VERSION 5.8 ;
BUSBITCHARS "[]" ;
DIVIDERCHAR "/" ;
UNITS
    DATABASE MICRONS 1000 ;
END UNITS

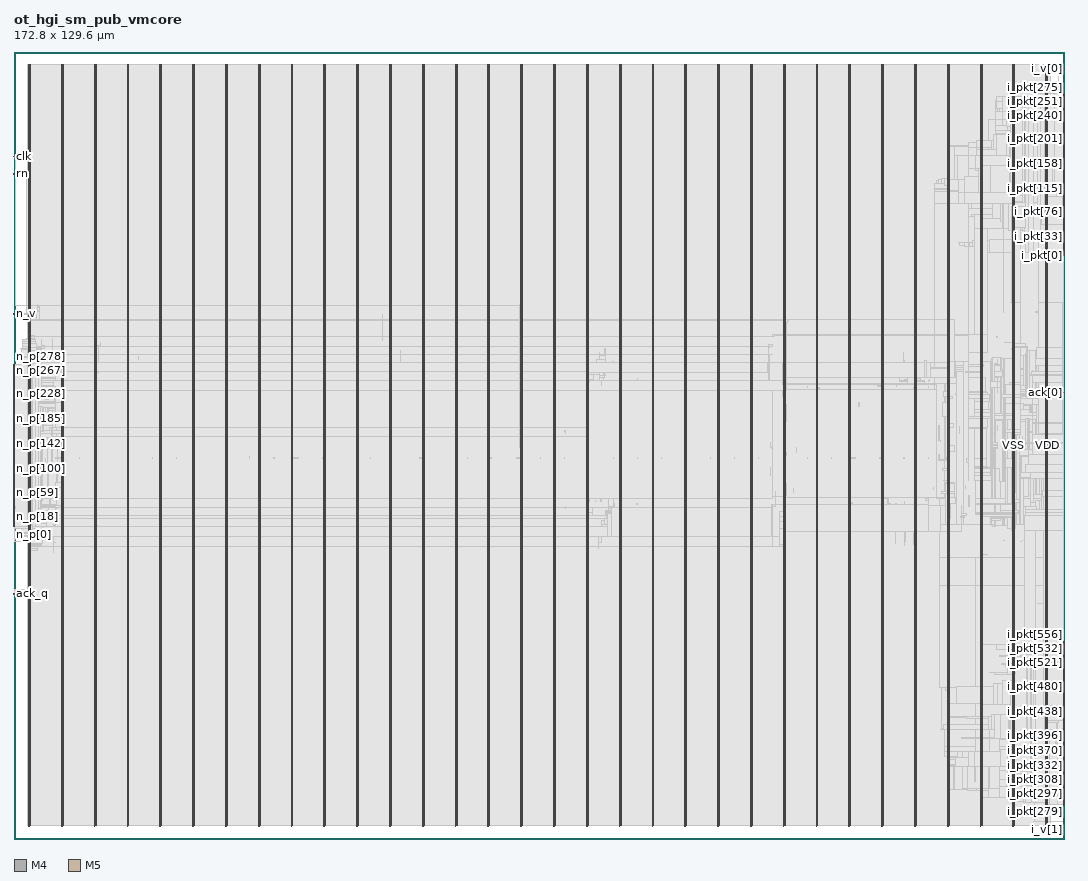
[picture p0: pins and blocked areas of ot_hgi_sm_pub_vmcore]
MACRO ot_hgi_sm_pub_vmcore
  FOREIGN ot_hgi_sm_pub_vmcore 0 0 ;
  CLASS BLOCK ;
  SIZE 172.8 BY 129.6 ;
  PIN ack[0]
    DIRECTION OUTPUT ;
    USE SIGNAL ;
    PORT
      LAYER M4 ;
        RECT  172.758 73.44 172.842 73.464 ;
    END
  END ack[0]
  PIN ack[1]
    DIRECTION OUTPUT ;
    USE SIGNAL ;
    PORT
      LAYER M4 ;
        RECT  172.758 73.536 172.842 73.56 ;
    END
  END ack[1]
  PIN ack_q
    DIRECTION INPUT ;
    USE SIGNAL ;
    PORT
      LAYER M4 ;
        RECT  -0.042 40.32 0.042 40.344 ;
    END
  END ack_q
  PIN clk
    DIRECTION INPUT ;
    USE SIGNAL ;
    PORT
      LAYER M4 ;
        RECT  -0.042 112.32 0.042 112.344 ;
    END
  END clk
  PIN i_pkt[0]
    DIRECTION INPUT ;
    USE SIGNAL ;
    PORT
      LAYER M4 ;
        RECT  172.758 96 172.842 96.024 ;
    END
  END i_pkt[0]
  PIN i_pkt[100]
    DIRECTION INPUT ;
    USE SIGNAL ;
    PORT
      LAYER M4 ;
        RECT  172.758 105.6 172.842 105.624 ;
    END
  END i_pkt[100]
  PIN i_pkt[101]
    DIRECTION INPUT ;
    USE SIGNAL ;
    PORT
      LAYER M4 ;
        RECT  172.758 105.696 172.842 105.72 ;
    END
  END i_pkt[101]
  PIN i_pkt[102]
    DIRECTION INPUT ;
    USE SIGNAL ;
    PORT
      LAYER M4 ;
        RECT  172.758 105.792 172.842 105.816 ;
    END
  END i_pkt[102]
  PIN i_pkt[103]
    DIRECTION INPUT ;
    USE SIGNAL ;
    PORT
      LAYER M4 ;
        RECT  172.758 105.888 172.842 105.912 ;
    END
  END i_pkt[103]
  PIN i_pkt[104]
    DIRECTION INPUT ;
    USE SIGNAL ;
    PORT
      LAYER M4 ;
        RECT  172.758 105.984 172.842 106.008 ;
    END
  END i_pkt[104]
  PIN i_pkt[105]
    DIRECTION INPUT ;
    USE SIGNAL ;
    PORT
      LAYER M4 ;
        RECT  172.758 106.08 172.842 106.104 ;
    END
  END i_pkt[105]
  PIN i_pkt[106]
    DIRECTION INPUT ;
    USE SIGNAL ;
    PORT
      LAYER M4 ;
        RECT  172.758 106.176 172.842 106.2 ;
    END
  END i_pkt[106]
  PIN i_pkt[107]
    DIRECTION INPUT ;
    USE SIGNAL ;
    PORT
      LAYER M4 ;
        RECT  172.758 106.272 172.842 106.296 ;
    END
  END i_pkt[107]
  PIN i_pkt[108]
    DIRECTION INPUT ;
    USE SIGNAL ;
    PORT
      LAYER M4 ;
        RECT  172.758 106.368 172.842 106.392 ;
    END
  END i_pkt[108]
  PIN i_pkt[109]
    DIRECTION INPUT ;
    USE SIGNAL ;
    PORT
      LAYER M4 ;
        RECT  172.758 106.464 172.842 106.488 ;
    END
  END i_pkt[109]
  PIN i_pkt[10]
    DIRECTION INPUT ;
    USE SIGNAL ;
    PORT
      LAYER M4 ;
        RECT  172.758 96.96 172.842 96.984 ;
    END
  END i_pkt[10]
  PIN i_pkt[110]
    DIRECTION INPUT ;
    USE SIGNAL ;
    PORT
      LAYER M4 ;
        RECT  172.758 106.56 172.842 106.584 ;
    END
  END i_pkt[110]
  PIN i_pkt[111]
    DIRECTION INPUT ;
    USE SIGNAL ;
    PORT
      LAYER M4 ;
        RECT  172.758 106.656 172.842 106.68 ;
    END
  END i_pkt[111]
  PIN i_pkt[112]
    DIRECTION INPUT ;
    USE SIGNAL ;
    PORT
      LAYER M4 ;
        RECT  172.758 106.752 172.842 106.776 ;
    END
  END i_pkt[112]
  PIN i_pkt[113]
    DIRECTION INPUT ;
    USE SIGNAL ;
    PORT
      LAYER M4 ;
        RECT  172.758 106.848 172.842 106.872 ;
    END
  END i_pkt[113]
  PIN i_pkt[114]
    DIRECTION INPUT ;
    USE SIGNAL ;
    PORT
      LAYER M4 ;
        RECT  172.758 106.944 172.842 106.968 ;
    END
  END i_pkt[114]
  PIN i_pkt[115]
    DIRECTION INPUT ;
    USE SIGNAL ;
    PORT
      LAYER M4 ;
        RECT  172.758 107.04 172.842 107.064 ;
    END
  END i_pkt[115]
  PIN i_pkt[116]
    DIRECTION INPUT ;
    USE SIGNAL ;
    PORT
      LAYER M4 ;
        RECT  172.758 107.136 172.842 107.16 ;
    END
  END i_pkt[116]
  PIN i_pkt[117]
    DIRECTION INPUT ;
    USE SIGNAL ;
    PORT
      LAYER M4 ;
        RECT  172.758 107.232 172.842 107.256 ;
    END
  END i_pkt[117]
  PIN i_pkt[118]
    DIRECTION INPUT ;
    USE SIGNAL ;
    PORT
      LAYER M4 ;
        RECT  172.758 107.328 172.842 107.352 ;
    END
  END i_pkt[118]
  PIN i_pkt[119]
    DIRECTION INPUT ;
    USE SIGNAL ;
    PORT
      LAYER M4 ;
        RECT  172.758 107.424 172.842 107.448 ;
    END
  END i_pkt[119]
  PIN i_pkt[11]
    DIRECTION INPUT ;
    USE SIGNAL ;
    PORT
      LAYER M4 ;
        RECT  172.758 97.056 172.842 97.08 ;
    END
  END i_pkt[11]
  PIN i_pkt[120]
    DIRECTION INPUT ;
    USE SIGNAL ;
    PORT
      LAYER M4 ;
        RECT  172.758 107.52 172.842 107.544 ;
    END
  END i_pkt[120]
  PIN i_pkt[121]
    DIRECTION INPUT ;
    USE SIGNAL ;
    PORT
      LAYER M4 ;
        RECT  172.758 107.616 172.842 107.64 ;
    END
  END i_pkt[121]
  PIN i_pkt[122]
    DIRECTION INPUT ;
    USE SIGNAL ;
    PORT
      LAYER M4 ;
        RECT  172.758 107.712 172.842 107.736 ;
    END
  END i_pkt[122]
  PIN i_pkt[123]
    DIRECTION INPUT ;
    USE SIGNAL ;
    PORT
      LAYER M4 ;
        RECT  172.758 107.808 172.842 107.832 ;
    END
  END i_pkt[123]
  PIN i_pkt[124]
    DIRECTION INPUT ;
    USE SIGNAL ;
    PORT
      LAYER M4 ;
        RECT  172.758 107.904 172.842 107.928 ;
    END
  END i_pkt[124]
  PIN i_pkt[125]
    DIRECTION INPUT ;
    USE SIGNAL ;
    PORT
      LAYER M4 ;
        RECT  172.758 108 172.842 108.024 ;
    END
  END i_pkt[125]
  PIN i_pkt[126]
    DIRECTION INPUT ;
    USE SIGNAL ;
    PORT
      LAYER M4 ;
        RECT  172.758 108.096 172.842 108.12 ;
    END
  END i_pkt[126]
  PIN i_pkt[127]
    DIRECTION INPUT ;
    USE SIGNAL ;
    PORT
      LAYER M4 ;
        RECT  172.758 108.192 172.842 108.216 ;
    END
  END i_pkt[127]
  PIN i_pkt[128]
    DIRECTION INPUT ;
    USE SIGNAL ;
    PORT
      LAYER M4 ;
        RECT  172.758 108.288 172.842 108.312 ;
    END
  END i_pkt[128]
  PIN i_pkt[129]
    DIRECTION INPUT ;
    USE SIGNAL ;
    PORT
      LAYER M4 ;
        RECT  172.758 108.384 172.842 108.408 ;
    END
  END i_pkt[129]
  PIN i_pkt[12]
    DIRECTION INPUT ;
    USE SIGNAL ;
    PORT
      LAYER M4 ;
        RECT  172.758 97.152 172.842 97.176 ;
    END
  END i_pkt[12]
  PIN i_pkt[130]
    DIRECTION INPUT ;
    USE SIGNAL ;
    PORT
      LAYER M4 ;
        RECT  172.758 108.48 172.842 108.504 ;
    END
  END i_pkt[130]
  PIN i_pkt[131]
    DIRECTION INPUT ;
    USE SIGNAL ;
    PORT
      LAYER M4 ;
        RECT  172.758 108.576 172.842 108.6 ;
    END
  END i_pkt[131]
  PIN i_pkt[132]
    DIRECTION INPUT ;
    USE SIGNAL ;
    PORT
      LAYER M4 ;
        RECT  172.758 108.672 172.842 108.696 ;
    END
  END i_pkt[132]
  PIN i_pkt[133]
    DIRECTION INPUT ;
    USE SIGNAL ;
    PORT
      LAYER M4 ;
        RECT  172.758 108.768 172.842 108.792 ;
    END
  END i_pkt[133]
  PIN i_pkt[134]
    DIRECTION INPUT ;
    USE SIGNAL ;
    PORT
      LAYER M4 ;
        RECT  172.758 108.864 172.842 108.888 ;
    END
  END i_pkt[134]
  PIN i_pkt[135]
    DIRECTION INPUT ;
    USE SIGNAL ;
    PORT
      LAYER M4 ;
        RECT  172.758 108.96 172.842 108.984 ;
    END
  END i_pkt[135]
  PIN i_pkt[136]
    DIRECTION INPUT ;
    USE SIGNAL ;
    PORT
      LAYER M4 ;
        RECT  172.758 109.056 172.842 109.08 ;
    END
  END i_pkt[136]
  PIN i_pkt[137]
    DIRECTION INPUT ;
    USE SIGNAL ;
    PORT
      LAYER M4 ;
        RECT  172.758 109.152 172.842 109.176 ;
    END
  END i_pkt[137]
  PIN i_pkt[138]
    DIRECTION INPUT ;
    USE SIGNAL ;
    PORT
      LAYER M4 ;
        RECT  172.758 109.248 172.842 109.272 ;
    END
  END i_pkt[138]
  PIN i_pkt[139]
    DIRECTION INPUT ;
    USE SIGNAL ;
    PORT
      LAYER M4 ;
        RECT  172.758 109.344 172.842 109.368 ;
    END
  END i_pkt[139]
  PIN i_pkt[13]
    DIRECTION INPUT ;
    USE SIGNAL ;
    PORT
      LAYER M4 ;
        RECT  172.758 97.248 172.842 97.272 ;
    END
  END i_pkt[13]
  PIN i_pkt[140]
    DIRECTION INPUT ;
    USE SIGNAL ;
    PORT
      LAYER M4 ;
        RECT  172.758 109.44 172.842 109.464 ;
    END
  END i_pkt[140]
  PIN i_pkt[141]
    DIRECTION INPUT ;
    USE SIGNAL ;
    PORT
      LAYER M4 ;
        RECT  172.758 109.536 172.842 109.56 ;
    END
  END i_pkt[141]
  PIN i_pkt[142]
    DIRECTION INPUT ;
    USE SIGNAL ;
    PORT
      LAYER M4 ;
        RECT  172.758 109.632 172.842 109.656 ;
    END
  END i_pkt[142]
  PIN i_pkt[143]
    DIRECTION INPUT ;
    USE SIGNAL ;
    PORT
      LAYER M4 ;
        RECT  172.758 109.728 172.842 109.752 ;
    END
  END i_pkt[143]
  PIN i_pkt[144]
    DIRECTION INPUT ;
    USE SIGNAL ;
    PORT
      LAYER M4 ;
        RECT  172.758 109.824 172.842 109.848 ;
    END
  END i_pkt[144]
  PIN i_pkt[145]
    DIRECTION INPUT ;
    USE SIGNAL ;
    PORT
      LAYER M4 ;
        RECT  172.758 109.92 172.842 109.944 ;
    END
  END i_pkt[145]
  PIN i_pkt[146]
    DIRECTION INPUT ;
    USE SIGNAL ;
    PORT
      LAYER M4 ;
        RECT  172.758 110.016 172.842 110.04 ;
    END
  END i_pkt[146]
  PIN i_pkt[147]
    DIRECTION INPUT ;
    USE SIGNAL ;
    PORT
      LAYER M4 ;
        RECT  172.758 110.112 172.842 110.136 ;
    END
  END i_pkt[147]
  PIN i_pkt[148]
    DIRECTION INPUT ;
    USE SIGNAL ;
    PORT
      LAYER M4 ;
        RECT  172.758 110.208 172.842 110.232 ;
    END
  END i_pkt[148]
  PIN i_pkt[149]
    DIRECTION INPUT ;
    USE SIGNAL ;
    PORT
      LAYER M4 ;
        RECT  172.758 110.304 172.842 110.328 ;
    END
  END i_pkt[149]
  PIN i_pkt[14]
    DIRECTION INPUT ;
    USE SIGNAL ;
    PORT
      LAYER M4 ;
        RECT  172.758 97.344 172.842 97.368 ;
    END
  END i_pkt[14]
  PIN i_pkt[150]
    DIRECTION INPUT ;
    USE SIGNAL ;
    PORT
      LAYER M4 ;
        RECT  172.758 110.4 172.842 110.424 ;
    END
  END i_pkt[150]
  PIN i_pkt[151]
    DIRECTION INPUT ;
    USE SIGNAL ;
    PORT
      LAYER M4 ;
        RECT  172.758 110.496 172.842 110.52 ;
    END
  END i_pkt[151]
  PIN i_pkt[152]
    DIRECTION INPUT ;
    USE SIGNAL ;
    PORT
      LAYER M4 ;
        RECT  172.758 110.592 172.842 110.616 ;
    END
  END i_pkt[152]
  PIN i_pkt[153]
    DIRECTION INPUT ;
    USE SIGNAL ;
    PORT
      LAYER M4 ;
        RECT  172.758 110.688 172.842 110.712 ;
    END
  END i_pkt[153]
  PIN i_pkt[154]
    DIRECTION INPUT ;
    USE SIGNAL ;
    PORT
      LAYER M4 ;
        RECT  172.758 110.784 172.842 110.808 ;
    END
  END i_pkt[154]
  PIN i_pkt[155]
    DIRECTION INPUT ;
    USE SIGNAL ;
    PORT
      LAYER M4 ;
        RECT  172.758 110.88 172.842 110.904 ;
    END
  END i_pkt[155]
  PIN i_pkt[156]
    DIRECTION INPUT ;
    USE SIGNAL ;
    PORT
      LAYER M4 ;
        RECT  172.758 110.976 172.842 111 ;
    END
  END i_pkt[156]
  PIN i_pkt[157]
    DIRECTION INPUT ;
    USE SIGNAL ;
    PORT
      LAYER M4 ;
        RECT  172.758 111.072 172.842 111.096 ;
    END
  END i_pkt[157]
  PIN i_pkt[158]
    DIRECTION INPUT ;
    USE SIGNAL ;
    PORT
      LAYER M4 ;
        RECT  172.758 111.168 172.842 111.192 ;
    END
  END i_pkt[158]
  PIN i_pkt[159]
    DIRECTION INPUT ;
    USE SIGNAL ;
    PORT
      LAYER M4 ;
        RECT  172.758 111.264 172.842 111.288 ;
    END
  END i_pkt[159]
  PIN i_pkt[15]
    DIRECTION INPUT ;
    USE SIGNAL ;
    PORT
      LAYER M4 ;
        RECT  172.758 97.44 172.842 97.464 ;
    END
  END i_pkt[15]
  PIN i_pkt[160]
    DIRECTION INPUT ;
    USE SIGNAL ;
    PORT
      LAYER M4 ;
        RECT  172.758 111.36 172.842 111.384 ;
    END
  END i_pkt[160]
  PIN i_pkt[161]
    DIRECTION INPUT ;
    USE SIGNAL ;
    PORT
      LAYER M4 ;
        RECT  172.758 111.456 172.842 111.48 ;
    END
  END i_pkt[161]
  PIN i_pkt[162]
    DIRECTION INPUT ;
    USE SIGNAL ;
    PORT
      LAYER M4 ;
        RECT  172.758 111.552 172.842 111.576 ;
    END
  END i_pkt[162]
  PIN i_pkt[163]
    DIRECTION INPUT ;
    USE SIGNAL ;
    PORT
      LAYER M4 ;
        RECT  172.758 111.648 172.842 111.672 ;
    END
  END i_pkt[163]
  PIN i_pkt[164]
    DIRECTION INPUT ;
    USE SIGNAL ;
    PORT
      LAYER M4 ;
        RECT  172.758 111.744 172.842 111.768 ;
    END
  END i_pkt[164]
  PIN i_pkt[165]
    DIRECTION INPUT ;
    USE SIGNAL ;
    PORT
      LAYER M4 ;
        RECT  172.758 111.84 172.842 111.864 ;
    END
  END i_pkt[165]
  PIN i_pkt[166]
    DIRECTION INPUT ;
    USE SIGNAL ;
    PORT
      LAYER M4 ;
        RECT  172.758 111.936 172.842 111.96 ;
    END
  END i_pkt[166]
  PIN i_pkt[167]
    DIRECTION INPUT ;
    USE SIGNAL ;
    PORT
      LAYER M4 ;
        RECT  172.758 112.032 172.842 112.056 ;
    END
  END i_pkt[167]
  PIN i_pkt[168]
    DIRECTION INPUT ;
    USE SIGNAL ;
    PORT
      LAYER M4 ;
        RECT  172.758 112.128 172.842 112.152 ;
    END
  END i_pkt[168]
  PIN i_pkt[169]
    DIRECTION INPUT ;
    USE SIGNAL ;
    PORT
      LAYER M4 ;
        RECT  172.758 112.224 172.842 112.248 ;
    END
  END i_pkt[169]
  PIN i_pkt[16]
    DIRECTION INPUT ;
    USE SIGNAL ;
    PORT
      LAYER M4 ;
        RECT  172.758 97.536 172.842 97.56 ;
    END
  END i_pkt[16]
  PIN i_pkt[170]
    DIRECTION INPUT ;
    USE SIGNAL ;
    PORT
      LAYER M4 ;
        RECT  172.758 112.32 172.842 112.344 ;
    END
  END i_pkt[170]
  PIN i_pkt[171]
    DIRECTION INPUT ;
    USE SIGNAL ;
    PORT
      LAYER M4 ;
        RECT  172.758 112.416 172.842 112.44 ;
    END
  END i_pkt[171]
  PIN i_pkt[172]
    DIRECTION INPUT ;
    USE SIGNAL ;
    PORT
      LAYER M4 ;
        RECT  172.758 112.512 172.842 112.536 ;
    END
  END i_pkt[172]
  PIN i_pkt[173]
    DIRECTION INPUT ;
    USE SIGNAL ;
    PORT
      LAYER M4 ;
        RECT  172.758 112.608 172.842 112.632 ;
    END
  END i_pkt[173]
  PIN i_pkt[174]
    DIRECTION INPUT ;
    USE SIGNAL ;
    PORT
      LAYER M4 ;
        RECT  172.758 112.704 172.842 112.728 ;
    END
  END i_pkt[174]
  PIN i_pkt[175]
    DIRECTION INPUT ;
    USE SIGNAL ;
    PORT
      LAYER M4 ;
        RECT  172.758 112.8 172.842 112.824 ;
    END
  END i_pkt[175]
  PIN i_pkt[176]
    DIRECTION INPUT ;
    USE SIGNAL ;
    PORT
      LAYER M4 ;
        RECT  172.758 112.896 172.842 112.92 ;
    END
  END i_pkt[176]
  PIN i_pkt[177]
    DIRECTION INPUT ;
    USE SIGNAL ;
    PORT
      LAYER M4 ;
        RECT  172.758 112.992 172.842 113.016 ;
    END
  END i_pkt[177]
  PIN i_pkt[178]
    DIRECTION INPUT ;
    USE SIGNAL ;
    PORT
      LAYER M4 ;
        RECT  172.758 113.088 172.842 113.112 ;
    END
  END i_pkt[178]
  PIN i_pkt[179]
    DIRECTION INPUT ;
    USE SIGNAL ;
    PORT
      LAYER M4 ;
        RECT  172.758 113.184 172.842 113.208 ;
    END
  END i_pkt[179]
  PIN i_pkt[17]
    DIRECTION INPUT ;
    USE SIGNAL ;
    PORT
      LAYER M4 ;
        RECT  172.758 97.632 172.842 97.656 ;
    END
  END i_pkt[17]
  PIN i_pkt[180]
    DIRECTION INPUT ;
    USE SIGNAL ;
    PORT
      LAYER M4 ;
        RECT  172.758 113.28 172.842 113.304 ;
    END
  END i_pkt[180]
  PIN i_pkt[181]
    DIRECTION INPUT ;
    USE SIGNAL ;
    PORT
      LAYER M4 ;
        RECT  172.758 113.376 172.842 113.4 ;
    END
  END i_pkt[181]
  PIN i_pkt[182]
    DIRECTION INPUT ;
    USE SIGNAL ;
    PORT
      LAYER M4 ;
        RECT  172.758 113.472 172.842 113.496 ;
    END
  END i_pkt[182]
  PIN i_pkt[183]
    DIRECTION INPUT ;
    USE SIGNAL ;
    PORT
      LAYER M4 ;
        RECT  172.758 113.568 172.842 113.592 ;
    END
  END i_pkt[183]
  PIN i_pkt[184]
    DIRECTION INPUT ;
    USE SIGNAL ;
    PORT
      LAYER M4 ;
        RECT  172.758 113.664 172.842 113.688 ;
    END
  END i_pkt[184]
  PIN i_pkt[185]
    DIRECTION INPUT ;
    USE SIGNAL ;
    PORT
      LAYER M4 ;
        RECT  172.758 113.76 172.842 113.784 ;
    END
  END i_pkt[185]
  PIN i_pkt[186]
    DIRECTION INPUT ;
    USE SIGNAL ;
    PORT
      LAYER M4 ;
        RECT  172.758 113.856 172.842 113.88 ;
    END
  END i_pkt[186]
  PIN i_pkt[187]
    DIRECTION INPUT ;
    USE SIGNAL ;
    PORT
      LAYER M4 ;
        RECT  172.758 113.952 172.842 113.976 ;
    END
  END i_pkt[187]
  PIN i_pkt[188]
    DIRECTION INPUT ;
    USE SIGNAL ;
    PORT
      LAYER M4 ;
        RECT  172.758 114.048 172.842 114.072 ;
    END
  END i_pkt[188]
  PIN i_pkt[189]
    DIRECTION INPUT ;
    USE SIGNAL ;
    PORT
      LAYER M4 ;
        RECT  172.758 114.144 172.842 114.168 ;
    END
  END i_pkt[189]
  PIN i_pkt[18]
    DIRECTION INPUT ;
    USE SIGNAL ;
    PORT
      LAYER M4 ;
        RECT  172.758 97.728 172.842 97.752 ;
    END
  END i_pkt[18]
  PIN i_pkt[190]
    DIRECTION INPUT ;
    USE SIGNAL ;
    PORT
      LAYER M4 ;
        RECT  172.758 114.24 172.842 114.264 ;
    END
  END i_pkt[190]
  PIN i_pkt[191]
    DIRECTION INPUT ;
    USE SIGNAL ;
    PORT
      LAYER M4 ;
        RECT  172.758 114.336 172.842 114.36 ;
    END
  END i_pkt[191]
  PIN i_pkt[192]
    DIRECTION INPUT ;
    USE SIGNAL ;
    PORT
      LAYER M4 ;
        RECT  172.758 114.432 172.842 114.456 ;
    END
  END i_pkt[192]
  PIN i_pkt[193]
    DIRECTION INPUT ;
    USE SIGNAL ;
    PORT
      LAYER M4 ;
        RECT  172.758 114.528 172.842 114.552 ;
    END
  END i_pkt[193]
  PIN i_pkt[194]
    DIRECTION INPUT ;
    USE SIGNAL ;
    PORT
      LAYER M4 ;
        RECT  172.758 114.624 172.842 114.648 ;
    END
  END i_pkt[194]
  PIN i_pkt[195]
    DIRECTION INPUT ;
    USE SIGNAL ;
    PORT
      LAYER M4 ;
        RECT  172.758 114.72 172.842 114.744 ;
    END
  END i_pkt[195]
  PIN i_pkt[196]
    DIRECTION INPUT ;
    USE SIGNAL ;
    PORT
      LAYER M4 ;
        RECT  172.758 114.816 172.842 114.84 ;
    END
  END i_pkt[196]
  PIN i_pkt[197]
    DIRECTION INPUT ;
    USE SIGNAL ;
    PORT
      LAYER M4 ;
        RECT  172.758 114.912 172.842 114.936 ;
    END
  END i_pkt[197]
  PIN i_pkt[198]
    DIRECTION INPUT ;
    USE SIGNAL ;
    PORT
      LAYER M4 ;
        RECT  172.758 115.008 172.842 115.032 ;
    END
  END i_pkt[198]
  PIN i_pkt[199]
    DIRECTION INPUT ;
    USE SIGNAL ;
    PORT
      LAYER M4 ;
        RECT  172.758 115.104 172.842 115.128 ;
    END
  END i_pkt[199]
  PIN i_pkt[19]
    DIRECTION INPUT ;
    USE SIGNAL ;
    PORT
      LAYER M4 ;
        RECT  172.758 97.824 172.842 97.848 ;
    END
  END i_pkt[19]
  PIN i_pkt[1]
    DIRECTION INPUT ;
    USE SIGNAL ;
    PORT
      LAYER M4 ;
        RECT  172.758 96.096 172.842 96.12 ;
    END
  END i_pkt[1]
  PIN i_pkt[200]
    DIRECTION INPUT ;
    USE SIGNAL ;
    PORT
      LAYER M4 ;
        RECT  172.758 115.2 172.842 115.224 ;
    END
  END i_pkt[200]
  PIN i_pkt[201]
    DIRECTION INPUT ;
    USE SIGNAL ;
    PORT
      LAYER M4 ;
        RECT  172.758 115.296 172.842 115.32 ;
    END
  END i_pkt[201]
  PIN i_pkt[202]
    DIRECTION INPUT ;
    USE SIGNAL ;
    PORT
      LAYER M4 ;
        RECT  172.758 115.392 172.842 115.416 ;
    END
  END i_pkt[202]
  PIN i_pkt[203]
    DIRECTION INPUT ;
    USE SIGNAL ;
    PORT
      LAYER M4 ;
        RECT  172.758 115.488 172.842 115.512 ;
    END
  END i_pkt[203]
  PIN i_pkt[204]
    DIRECTION INPUT ;
    USE SIGNAL ;
    PORT
      LAYER M4 ;
        RECT  172.758 115.584 172.842 115.608 ;
    END
  END i_pkt[204]
  PIN i_pkt[205]
    DIRECTION INPUT ;
    USE SIGNAL ;
    PORT
      LAYER M4 ;
        RECT  172.758 115.68 172.842 115.704 ;
    END
  END i_pkt[205]
  PIN i_pkt[206]
    DIRECTION INPUT ;
    USE SIGNAL ;
    PORT
      LAYER M4 ;
        RECT  172.758 115.776 172.842 115.8 ;
    END
  END i_pkt[206]
  PIN i_pkt[207]
    DIRECTION INPUT ;
    USE SIGNAL ;
    PORT
      LAYER M4 ;
        RECT  172.758 115.872 172.842 115.896 ;
    END
  END i_pkt[207]
  PIN i_pkt[208]
    DIRECTION INPUT ;
    USE SIGNAL ;
    PORT
      LAYER M4 ;
        RECT  172.758 115.968 172.842 115.992 ;
    END
  END i_pkt[208]
  PIN i_pkt[209]
    DIRECTION INPUT ;
    USE SIGNAL ;
    PORT
      LAYER M4 ;
        RECT  172.758 116.064 172.842 116.088 ;
    END
  END i_pkt[209]
  PIN i_pkt[20]
    DIRECTION INPUT ;
    USE SIGNAL ;
    PORT
      LAYER M4 ;
        RECT  172.758 97.92 172.842 97.944 ;
    END
  END i_pkt[20]
  PIN i_pkt[210]
    DIRECTION INPUT ;
    USE SIGNAL ;
    PORT
      LAYER M4 ;
        RECT  172.758 116.16 172.842 116.184 ;
    END
  END i_pkt[210]
  PIN i_pkt[211]
    DIRECTION INPUT ;
    USE SIGNAL ;
    PORT
      LAYER M4 ;
        RECT  172.758 116.256 172.842 116.28 ;
    END
  END i_pkt[211]
  PIN i_pkt[212]
    DIRECTION INPUT ;
    USE SIGNAL ;
    PORT
      LAYER M4 ;
        RECT  172.758 116.352 172.842 116.376 ;
    END
  END i_pkt[212]
  PIN i_pkt[213]
    DIRECTION INPUT ;
    USE SIGNAL ;
    PORT
      LAYER M4 ;
        RECT  172.758 116.448 172.842 116.472 ;
    END
  END i_pkt[213]
  PIN i_pkt[214]
    DIRECTION INPUT ;
    USE SIGNAL ;
    PORT
      LAYER M4 ;
        RECT  172.758 116.544 172.842 116.568 ;
    END
  END i_pkt[214]
  PIN i_pkt[215]
    DIRECTION INPUT ;
    USE SIGNAL ;
    PORT
      LAYER M4 ;
        RECT  172.758 116.64 172.842 116.664 ;
    END
  END i_pkt[215]
  PIN i_pkt[216]
    DIRECTION INPUT ;
    USE SIGNAL ;
    PORT
      LAYER M4 ;
        RECT  172.758 116.736 172.842 116.76 ;
    END
  END i_pkt[216]
  PIN i_pkt[217]
    DIRECTION INPUT ;
    USE SIGNAL ;
    PORT
      LAYER M4 ;
        RECT  172.758 116.832 172.842 116.856 ;
    END
  END i_pkt[217]
  PIN i_pkt[218]
    DIRECTION INPUT ;
    USE SIGNAL ;
    PORT
      LAYER M4 ;
        RECT  172.758 116.928 172.842 116.952 ;
    END
  END i_pkt[218]
  PIN i_pkt[219]
    DIRECTION INPUT ;
    USE SIGNAL ;
    PORT
      LAYER M4 ;
        RECT  172.758 117.024 172.842 117.048 ;
    END
  END i_pkt[219]
  PIN i_pkt[21]
    DIRECTION INPUT ;
    USE SIGNAL ;
    PORT
      LAYER M4 ;
        RECT  172.758 98.016 172.842 98.04 ;
    END
  END i_pkt[21]
  PIN i_pkt[220]
    DIRECTION INPUT ;
    USE SIGNAL ;
    PORT
      LAYER M4 ;
        RECT  172.758 117.12 172.842 117.144 ;
    END
  END i_pkt[220]
  PIN i_pkt[221]
    DIRECTION INPUT ;
    USE SIGNAL ;
    PORT
      LAYER M4 ;
        RECT  172.758 117.216 172.842 117.24 ;
    END
  END i_pkt[221]
  PIN i_pkt[222]
    DIRECTION INPUT ;
    USE SIGNAL ;
    PORT
      LAYER M4 ;
        RECT  172.758 117.312 172.842 117.336 ;
    END
  END i_pkt[222]
  PIN i_pkt[223]
    DIRECTION INPUT ;
    USE SIGNAL ;
    PORT
      LAYER M4 ;
        RECT  172.758 117.408 172.842 117.432 ;
    END
  END i_pkt[223]
  PIN i_pkt[224]
    DIRECTION INPUT ;
    USE SIGNAL ;
    PORT
      LAYER M4 ;
        RECT  172.758 117.504 172.842 117.528 ;
    END
  END i_pkt[224]
  PIN i_pkt[225]
    DIRECTION INPUT ;
    USE SIGNAL ;
    PORT
      LAYER M4 ;
        RECT  172.758 117.6 172.842 117.624 ;
    END
  END i_pkt[225]
  PIN i_pkt[226]
    DIRECTION INPUT ;
    USE SIGNAL ;
    PORT
      LAYER M4 ;
        RECT  172.758 117.696 172.842 117.72 ;
    END
  END i_pkt[226]
  PIN i_pkt[227]
    DIRECTION INPUT ;
    USE SIGNAL ;
    PORT
      LAYER M4 ;
        RECT  172.758 117.792 172.842 117.816 ;
    END
  END i_pkt[227]
  PIN i_pkt[228]
    DIRECTION INPUT ;
    USE SIGNAL ;
    PORT
      LAYER M4 ;
        RECT  172.758 117.888 172.842 117.912 ;
    END
  END i_pkt[228]
  PIN i_pkt[229]
    DIRECTION INPUT ;
    USE SIGNAL ;
    PORT
      LAYER M4 ;
        RECT  172.758 117.984 172.842 118.008 ;
    END
  END i_pkt[229]
  PIN i_pkt[22]
    DIRECTION INPUT ;
    USE SIGNAL ;
    PORT
      LAYER M4 ;
        RECT  172.758 98.112 172.842 98.136 ;
    END
  END i_pkt[22]
  PIN i_pkt[230]
    DIRECTION INPUT ;
    USE SIGNAL ;
    PORT
      LAYER M4 ;
        RECT  172.758 118.08 172.842 118.104 ;
    END
  END i_pkt[230]
  PIN i_pkt[231]
    DIRECTION INPUT ;
    USE SIGNAL ;
    PORT
      LAYER M4 ;
        RECT  172.758 118.176 172.842 118.2 ;
    END
  END i_pkt[231]
  PIN i_pkt[232]
    DIRECTION INPUT ;
    USE SIGNAL ;
    PORT
      LAYER M4 ;
        RECT  172.758 118.272 172.842 118.296 ;
    END
  END i_pkt[232]
  PIN i_pkt[233]
    DIRECTION INPUT ;
    USE SIGNAL ;
    PORT
      LAYER M4 ;
        RECT  172.758 118.368 172.842 118.392 ;
    END
  END i_pkt[233]
  PIN i_pkt[234]
    DIRECTION INPUT ;
    USE SIGNAL ;
    PORT
      LAYER M4 ;
        RECT  172.758 118.464 172.842 118.488 ;
    END
  END i_pkt[234]
  PIN i_pkt[235]
    DIRECTION INPUT ;
    USE SIGNAL ;
    PORT
      LAYER M4 ;
        RECT  172.758 118.56 172.842 118.584 ;
    END
  END i_pkt[235]
  PIN i_pkt[236]
    DIRECTION INPUT ;
    USE SIGNAL ;
    PORT
      LAYER M4 ;
        RECT  172.758 118.656 172.842 118.68 ;
    END
  END i_pkt[236]
  PIN i_pkt[237]
    DIRECTION INPUT ;
    USE SIGNAL ;
    PORT
      LAYER M4 ;
        RECT  172.758 118.752 172.842 118.776 ;
    END
  END i_pkt[237]
  PIN i_pkt[238]
    DIRECTION INPUT ;
    USE SIGNAL ;
    PORT
      LAYER M4 ;
        RECT  172.758 118.848 172.842 118.872 ;
    END
  END i_pkt[238]
  PIN i_pkt[239]
    DIRECTION INPUT ;
    USE SIGNAL ;
    PORT
      LAYER M4 ;
        RECT  172.758 118.944 172.842 118.968 ;
    END
  END i_pkt[239]
  PIN i_pkt[23]
    DIRECTION INPUT ;
    USE SIGNAL ;
    PORT
      LAYER M4 ;
        RECT  172.758 98.208 172.842 98.232 ;
    END
  END i_pkt[23]
  PIN i_pkt[240]
    DIRECTION INPUT ;
    USE SIGNAL ;
    PORT
      LAYER M4 ;
        RECT  172.758 119.04 172.842 119.064 ;
    END
  END i_pkt[240]
  PIN i_pkt[241]
    DIRECTION INPUT ;
    USE SIGNAL ;
    PORT
      LAYER M4 ;
        RECT  172.758 119.136 172.842 119.16 ;
    END
  END i_pkt[241]
  PIN i_pkt[242]
    DIRECTION INPUT ;
    USE SIGNAL ;
    PORT
      LAYER M4 ;
        RECT  172.758 119.232 172.842 119.256 ;
    END
  END i_pkt[242]
  PIN i_pkt[243]
    DIRECTION INPUT ;
    USE SIGNAL ;
    PORT
      LAYER M4 ;
        RECT  172.758 119.328 172.842 119.352 ;
    END
  END i_pkt[243]
  PIN i_pkt[244]
    DIRECTION INPUT ;
    USE SIGNAL ;
    PORT
      LAYER M4 ;
        RECT  172.758 119.424 172.842 119.448 ;
    END
  END i_pkt[244]
  PIN i_pkt[245]
    DIRECTION INPUT ;
    USE SIGNAL ;
    PORT
      LAYER M4 ;
        RECT  172.758 119.52 172.842 119.544 ;
    END
  END i_pkt[245]
  PIN i_pkt[246]
    DIRECTION INPUT ;
    USE SIGNAL ;
    PORT
      LAYER M4 ;
        RECT  172.758 119.616 172.842 119.64 ;
    END
  END i_pkt[246]
  PIN i_pkt[247]
    DIRECTION INPUT ;
    USE SIGNAL ;
    PORT
      LAYER M4 ;
        RECT  172.758 119.712 172.842 119.736 ;
    END
  END i_pkt[247]
  PIN i_pkt[248]
    DIRECTION INPUT ;
    USE SIGNAL ;
    PORT
      LAYER M4 ;
        RECT  172.758 119.808 172.842 119.832 ;
    END
  END i_pkt[248]
  PIN i_pkt[249]
    DIRECTION INPUT ;
    USE SIGNAL ;
    PORT
      LAYER M4 ;
        RECT  172.758 119.904 172.842 119.928 ;
    END
  END i_pkt[249]
  PIN i_pkt[24]
    DIRECTION INPUT ;
    USE SIGNAL ;
    PORT
      LAYER M4 ;
        RECT  172.758 98.304 172.842 98.328 ;
    END
  END i_pkt[24]
  PIN i_pkt[250]
    DIRECTION INPUT ;
    USE SIGNAL ;
    PORT
      LAYER M4 ;
        RECT  172.758 120 172.842 120.024 ;
    END
  END i_pkt[250]
  PIN i_pkt[251]
    DIRECTION INPUT ;
    USE SIGNAL ;
    PORT
      LAYER M4 ;
        RECT  172.758 120.096 172.842 120.12 ;
    END
  END i_pkt[251]
  PIN i_pkt[252]
    DIRECTION INPUT ;
    USE SIGNAL ;
    PORT
      LAYER M4 ;
        RECT  172.758 120.192 172.842 120.216 ;
    END
  END i_pkt[252]
  PIN i_pkt[253]
    DIRECTION INPUT ;
    USE SIGNAL ;
    PORT
      LAYER M4 ;
        RECT  172.758 120.288 172.842 120.312 ;
    END
  END i_pkt[253]
  PIN i_pkt[254]
    DIRECTION INPUT ;
    USE SIGNAL ;
    PORT
      LAYER M4 ;
        RECT  172.758 120.384 172.842 120.408 ;
    END
  END i_pkt[254]
  PIN i_pkt[255]
    DIRECTION INPUT ;
    USE SIGNAL ;
    PORT
      LAYER M4 ;
        RECT  172.758 120.48 172.842 120.504 ;
    END
  END i_pkt[255]
  PIN i_pkt[256]
    DIRECTION INPUT ;
    USE SIGNAL ;
    PORT
      LAYER M4 ;
        RECT  172.758 120.576 172.842 120.6 ;
    END
  END i_pkt[256]
  PIN i_pkt[257]
    DIRECTION INPUT ;
    USE SIGNAL ;
    PORT
      LAYER M4 ;
        RECT  172.758 120.672 172.842 120.696 ;
    END
  END i_pkt[257]
  PIN i_pkt[258]
    DIRECTION INPUT ;
    USE SIGNAL ;
    PORT
      LAYER M4 ;
        RECT  172.758 120.768 172.842 120.792 ;
    END
  END i_pkt[258]
  PIN i_pkt[259]
    DIRECTION INPUT ;
    USE SIGNAL ;
    PORT
      LAYER M4 ;
        RECT  172.758 120.864 172.842 120.888 ;
    END
  END i_pkt[259]
  PIN i_pkt[25]
    DIRECTION INPUT ;
    USE SIGNAL ;
    PORT
      LAYER M4 ;
        RECT  172.758 98.4 172.842 98.424 ;
    END
  END i_pkt[25]
  PIN i_pkt[260]
    DIRECTION INPUT ;
    USE SIGNAL ;
    PORT
      LAYER M4 ;
        RECT  172.758 120.96 172.842 120.984 ;
    END
  END i_pkt[260]
  PIN i_pkt[261]
    DIRECTION INPUT ;
    USE SIGNAL ;
    PORT
      LAYER M4 ;
        RECT  172.758 121.056 172.842 121.08 ;
    END
  END i_pkt[261]
  PIN i_pkt[262]
    DIRECTION INPUT ;
    USE SIGNAL ;
    PORT
      LAYER M4 ;
        RECT  172.758 121.152 172.842 121.176 ;
    END
  END i_pkt[262]
  PIN i_pkt[263]
    DIRECTION INPUT ;
    USE SIGNAL ;
    PORT
      LAYER M4 ;
        RECT  172.758 121.248 172.842 121.272 ;
    END
  END i_pkt[263]
  PIN i_pkt[264]
    DIRECTION INPUT ;
    USE SIGNAL ;
    PORT
      LAYER M4 ;
        RECT  172.758 121.344 172.842 121.368 ;
    END
  END i_pkt[264]
  PIN i_pkt[265]
    DIRECTION INPUT ;
    USE SIGNAL ;
    PORT
      LAYER M4 ;
        RECT  172.758 121.44 172.842 121.464 ;
    END
  END i_pkt[265]
  PIN i_pkt[266]
    DIRECTION INPUT ;
    USE SIGNAL ;
    PORT
      LAYER M4 ;
        RECT  172.758 121.536 172.842 121.56 ;
    END
  END i_pkt[266]
  PIN i_pkt[267]
    DIRECTION INPUT ;
    USE SIGNAL ;
    PORT
      LAYER M4 ;
        RECT  172.758 121.632 172.842 121.656 ;
    END
  END i_pkt[267]
  PIN i_pkt[268]
    DIRECTION INPUT ;
    USE SIGNAL ;
    PORT
      LAYER M4 ;
        RECT  172.758 121.728 172.842 121.752 ;
    END
  END i_pkt[268]
  PIN i_pkt[269]
    DIRECTION INPUT ;
    USE SIGNAL ;
    PORT
      LAYER M4 ;
        RECT  172.758 121.824 172.842 121.848 ;
    END
  END i_pkt[269]
  PIN i_pkt[26]
    DIRECTION INPUT ;
    USE SIGNAL ;
    PORT
      LAYER M4 ;
        RECT  172.758 98.496 172.842 98.52 ;
    END
  END i_pkt[26]
  PIN i_pkt[270]
    DIRECTION INPUT ;
    USE SIGNAL ;
    PORT
      LAYER M4 ;
        RECT  172.758 121.92 172.842 121.944 ;
    END
  END i_pkt[270]
  PIN i_pkt[271]
    DIRECTION INPUT ;
    USE SIGNAL ;
    PORT
      LAYER M4 ;
        RECT  172.758 122.016 172.842 122.04 ;
    END
  END i_pkt[271]
  PIN i_pkt[272]
    DIRECTION INPUT ;
    USE SIGNAL ;
    PORT
      LAYER M4 ;
        RECT  172.758 122.112 172.842 122.136 ;
    END
  END i_pkt[272]
  PIN i_pkt[273]
    DIRECTION INPUT ;
    USE SIGNAL ;
    PORT
      LAYER M4 ;
        RECT  172.758 122.208 172.842 122.232 ;
    END
  END i_pkt[273]
  PIN i_pkt[274]
    DIRECTION INPUT ;
    USE SIGNAL ;
    PORT
      LAYER M4 ;
        RECT  172.758 122.304 172.842 122.328 ;
    END
  END i_pkt[274]
  PIN i_pkt[275]
    DIRECTION INPUT ;
    USE SIGNAL ;
    PORT
      LAYER M4 ;
        RECT  172.758 122.4 172.842 122.424 ;
    END
  END i_pkt[275]
  PIN i_pkt[276]
    DIRECTION INPUT ;
    USE SIGNAL ;
    PORT
      LAYER M4 ;
        RECT  172.758 122.496 172.842 122.52 ;
    END
  END i_pkt[276]
  PIN i_pkt[277]
    DIRECTION INPUT ;
    USE SIGNAL ;
    PORT
      LAYER M4 ;
        RECT  172.758 122.592 172.842 122.616 ;
    END
  END i_pkt[277]
  PIN i_pkt[278]
    DIRECTION INPUT ;
    USE SIGNAL ;
    PORT
      LAYER M4 ;
        RECT  172.758 122.688 172.842 122.712 ;
    END
  END i_pkt[278]
  PIN i_pkt[279]
    DIRECTION INPUT ;
    USE SIGNAL ;
    PORT
      LAYER M4 ;
        RECT  172.758 5.76 172.842 5.784 ;
    END
  END i_pkt[279]
  PIN i_pkt[27]
    DIRECTION INPUT ;
    USE SIGNAL ;
    PORT
      LAYER M4 ;
        RECT  172.758 98.592 172.842 98.616 ;
    END
  END i_pkt[27]
  PIN i_pkt[280]
    DIRECTION INPUT ;
    USE SIGNAL ;
    PORT
      LAYER M4 ;
        RECT  172.758 5.856 172.842 5.88 ;
    END
  END i_pkt[280]
  PIN i_pkt[281]
    DIRECTION INPUT ;
    USE SIGNAL ;
    PORT
      LAYER M4 ;
        RECT  172.758 5.952 172.842 5.976 ;
    END
  END i_pkt[281]
  PIN i_pkt[282]
    DIRECTION INPUT ;
    USE SIGNAL ;
    PORT
      LAYER M4 ;
        RECT  172.758 6.048 172.842 6.072 ;
    END
  END i_pkt[282]
  PIN i_pkt[283]
    DIRECTION INPUT ;
    USE SIGNAL ;
    PORT
      LAYER M4 ;
        RECT  172.758 6.144 172.842 6.168 ;
    END
  END i_pkt[283]
  PIN i_pkt[284]
    DIRECTION INPUT ;
    USE SIGNAL ;
    PORT
      LAYER M4 ;
        RECT  172.758 6.24 172.842 6.264 ;
    END
  END i_pkt[284]
  PIN i_pkt[285]
    DIRECTION INPUT ;
    USE SIGNAL ;
    PORT
      LAYER M4 ;
        RECT  172.758 6.336 172.842 6.36 ;
    END
  END i_pkt[285]
  PIN i_pkt[286]
    DIRECTION INPUT ;
    USE SIGNAL ;
    PORT
      LAYER M4 ;
        RECT  172.758 6.432 172.842 6.456 ;
    END
  END i_pkt[286]
  PIN i_pkt[287]
    DIRECTION INPUT ;
    USE SIGNAL ;
    PORT
      LAYER M4 ;
        RECT  172.758 6.528 172.842 6.552 ;
    END
  END i_pkt[287]
  PIN i_pkt[288]
    DIRECTION INPUT ;
    USE SIGNAL ;
    PORT
      LAYER M4 ;
        RECT  172.758 6.624 172.842 6.648 ;
    END
  END i_pkt[288]
  PIN i_pkt[289]
    DIRECTION INPUT ;
    USE SIGNAL ;
    PORT
      LAYER M4 ;
        RECT  172.758 6.72 172.842 6.744 ;
    END
  END i_pkt[289]
  PIN i_pkt[28]
    DIRECTION INPUT ;
    USE SIGNAL ;
    PORT
      LAYER M4 ;
        RECT  172.758 98.688 172.842 98.712 ;
    END
  END i_pkt[28]
  PIN i_pkt[290]
    DIRECTION INPUT ;
    USE SIGNAL ;
    PORT
      LAYER M4 ;
        RECT  172.758 6.816 172.842 6.84 ;
    END
  END i_pkt[290]
  PIN i_pkt[291]
    DIRECTION INPUT ;
    USE SIGNAL ;
    PORT
      LAYER M4 ;
        RECT  172.758 6.912 172.842 6.936 ;
    END
  END i_pkt[291]
  PIN i_pkt[292]
    DIRECTION INPUT ;
    USE SIGNAL ;
    PORT
      LAYER M4 ;
        RECT  172.758 7.008 172.842 7.032 ;
    END
  END i_pkt[292]
  PIN i_pkt[293]
    DIRECTION INPUT ;
    USE SIGNAL ;
    PORT
      LAYER M4 ;
        RECT  172.758 7.104 172.842 7.128 ;
    END
  END i_pkt[293]
  PIN i_pkt[294]
    DIRECTION INPUT ;
    USE SIGNAL ;
    PORT
      LAYER M4 ;
        RECT  172.758 7.2 172.842 7.224 ;
    END
  END i_pkt[294]
  PIN i_pkt[295]
    DIRECTION INPUT ;
    USE SIGNAL ;
    PORT
      LAYER M4 ;
        RECT  172.758 7.296 172.842 7.32 ;
    END
  END i_pkt[295]
  PIN i_pkt[296]
    DIRECTION INPUT ;
    USE SIGNAL ;
    PORT
      LAYER M4 ;
        RECT  172.758 7.392 172.842 7.416 ;
    END
  END i_pkt[296]
  PIN i_pkt[297]
    DIRECTION INPUT ;
    USE SIGNAL ;
    PORT
      LAYER M4 ;
        RECT  172.758 7.488 172.842 7.512 ;
    END
  END i_pkt[297]
  PIN i_pkt[298]
    DIRECTION INPUT ;
    USE SIGNAL ;
    PORT
      LAYER M4 ;
        RECT  172.758 7.584 172.842 7.608 ;
    END
  END i_pkt[298]
  PIN i_pkt[299]
    DIRECTION INPUT ;
    USE SIGNAL ;
    PORT
      LAYER M4 ;
        RECT  172.758 7.68 172.842 7.704 ;
    END
  END i_pkt[299]
  PIN i_pkt[29]
    DIRECTION INPUT ;
    USE SIGNAL ;
    PORT
      LAYER M4 ;
        RECT  172.758 98.784 172.842 98.808 ;
    END
  END i_pkt[29]
  PIN i_pkt[2]
    DIRECTION INPUT ;
    USE SIGNAL ;
    PORT
      LAYER M4 ;
        RECT  172.758 96.192 172.842 96.216 ;
    END
  END i_pkt[2]
  PIN i_pkt[300]
    DIRECTION INPUT ;
    USE SIGNAL ;
    PORT
      LAYER M4 ;
        RECT  172.758 7.776 172.842 7.8 ;
    END
  END i_pkt[300]
  PIN i_pkt[301]
    DIRECTION INPUT ;
    USE SIGNAL ;
    PORT
      LAYER M4 ;
        RECT  172.758 7.872 172.842 7.896 ;
    END
  END i_pkt[301]
  PIN i_pkt[302]
    DIRECTION INPUT ;
    USE SIGNAL ;
    PORT
      LAYER M4 ;
        RECT  172.758 7.968 172.842 7.992 ;
    END
  END i_pkt[302]
  PIN i_pkt[303]
    DIRECTION INPUT ;
    USE SIGNAL ;
    PORT
      LAYER M4 ;
        RECT  172.758 8.064 172.842 8.088 ;
    END
  END i_pkt[303]
  PIN i_pkt[304]
    DIRECTION INPUT ;
    USE SIGNAL ;
    PORT
      LAYER M4 ;
        RECT  172.758 8.16 172.842 8.184 ;
    END
  END i_pkt[304]
  PIN i_pkt[305]
    DIRECTION INPUT ;
    USE SIGNAL ;
    PORT
      LAYER M4 ;
        RECT  172.758 8.256 172.842 8.28 ;
    END
  END i_pkt[305]
  PIN i_pkt[306]
    DIRECTION INPUT ;
    USE SIGNAL ;
    PORT
      LAYER M4 ;
        RECT  172.758 8.352 172.842 8.376 ;
    END
  END i_pkt[306]
  PIN i_pkt[307]
    DIRECTION INPUT ;
    USE SIGNAL ;
    PORT
      LAYER M4 ;
        RECT  172.758 8.448 172.842 8.472 ;
    END
  END i_pkt[307]
  PIN i_pkt[308]
    DIRECTION INPUT ;
    USE SIGNAL ;
    PORT
      LAYER M4 ;
        RECT  172.758 8.544 172.842 8.568 ;
    END
  END i_pkt[308]
  PIN i_pkt[309]
    DIRECTION INPUT ;
    USE SIGNAL ;
    PORT
      LAYER M4 ;
        RECT  172.758 8.64 172.842 8.664 ;
    END
  END i_pkt[309]
  PIN i_pkt[30]
    DIRECTION INPUT ;
    USE SIGNAL ;
    PORT
      LAYER M4 ;
        RECT  172.758 98.88 172.842 98.904 ;
    END
  END i_pkt[30]
  PIN i_pkt[310]
    DIRECTION INPUT ;
    USE SIGNAL ;
    PORT
      LAYER M4 ;
        RECT  172.758 8.736 172.842 8.76 ;
    END
  END i_pkt[310]
  PIN i_pkt[311]
    DIRECTION INPUT ;
    USE SIGNAL ;
    PORT
      LAYER M4 ;
        RECT  172.758 8.832 172.842 8.856 ;
    END
  END i_pkt[311]
  PIN i_pkt[312]
    DIRECTION INPUT ;
    USE SIGNAL ;
    PORT
      LAYER M4 ;
        RECT  172.758 8.928 172.842 8.952 ;
    END
  END i_pkt[312]
  PIN i_pkt[313]
    DIRECTION INPUT ;
    USE SIGNAL ;
    PORT
      LAYER M4 ;
        RECT  172.758 9.024 172.842 9.048 ;
    END
  END i_pkt[313]
  PIN i_pkt[314]
    DIRECTION INPUT ;
    USE SIGNAL ;
    PORT
      LAYER M4 ;
        RECT  172.758 9.12 172.842 9.144 ;
    END
  END i_pkt[314]
  PIN i_pkt[315]
    DIRECTION INPUT ;
    USE SIGNAL ;
    PORT
      LAYER M4 ;
        RECT  172.758 9.216 172.842 9.24 ;
    END
  END i_pkt[315]
  PIN i_pkt[316]
    DIRECTION INPUT ;
    USE SIGNAL ;
    PORT
      LAYER M4 ;
        RECT  172.758 9.312 172.842 9.336 ;
    END
  END i_pkt[316]
  PIN i_pkt[317]
    DIRECTION INPUT ;
    USE SIGNAL ;
    PORT
      LAYER M4 ;
        RECT  172.758 9.408 172.842 9.432 ;
    END
  END i_pkt[317]
  PIN i_pkt[318]
    DIRECTION INPUT ;
    USE SIGNAL ;
    PORT
      LAYER M4 ;
        RECT  172.758 9.504 172.842 9.528 ;
    END
  END i_pkt[318]
  PIN i_pkt[319]
    DIRECTION INPUT ;
    USE SIGNAL ;
    PORT
      LAYER M4 ;
        RECT  172.758 9.6 172.842 9.624 ;
    END
  END i_pkt[319]
  PIN i_pkt[31]
    DIRECTION INPUT ;
    USE SIGNAL ;
    PORT
      LAYER M4 ;
        RECT  172.758 98.976 172.842 99 ;
    END
  END i_pkt[31]
  PIN i_pkt[320]
    DIRECTION INPUT ;
    USE SIGNAL ;
    PORT
      LAYER M4 ;
        RECT  172.758 9.696 172.842 9.72 ;
    END
  END i_pkt[320]
  PIN i_pkt[321]
    DIRECTION INPUT ;
    USE SIGNAL ;
    PORT
      LAYER M4 ;
        RECT  172.758 9.792 172.842 9.816 ;
    END
  END i_pkt[321]
  PIN i_pkt[322]
    DIRECTION INPUT ;
    USE SIGNAL ;
    PORT
      LAYER M4 ;
        RECT  172.758 9.888 172.842 9.912 ;
    END
  END i_pkt[322]
  PIN i_pkt[323]
    DIRECTION INPUT ;
    USE SIGNAL ;
    PORT
      LAYER M4 ;
        RECT  172.758 9.984 172.842 10.008 ;
    END
  END i_pkt[323]
  PIN i_pkt[324]
    DIRECTION INPUT ;
    USE SIGNAL ;
    PORT
      LAYER M4 ;
        RECT  172.758 10.08 172.842 10.104 ;
    END
  END i_pkt[324]
  PIN i_pkt[325]
    DIRECTION INPUT ;
    USE SIGNAL ;
    PORT
      LAYER M4 ;
        RECT  172.758 10.176 172.842 10.2 ;
    END
  END i_pkt[325]
  PIN i_pkt[326]
    DIRECTION INPUT ;
    USE SIGNAL ;
    PORT
      LAYER M4 ;
        RECT  172.758 10.272 172.842 10.296 ;
    END
  END i_pkt[326]
  PIN i_pkt[327]
    DIRECTION INPUT ;
    USE SIGNAL ;
    PORT
      LAYER M4 ;
        RECT  172.758 10.368 172.842 10.392 ;
    END
  END i_pkt[327]
  PIN i_pkt[328]
    DIRECTION INPUT ;
    USE SIGNAL ;
    PORT
      LAYER M4 ;
        RECT  172.758 10.464 172.842 10.488 ;
    END
  END i_pkt[328]
  PIN i_pkt[329]
    DIRECTION INPUT ;
    USE SIGNAL ;
    PORT
      LAYER M4 ;
        RECT  172.758 10.56 172.842 10.584 ;
    END
  END i_pkt[329]
  PIN i_pkt[32]
    DIRECTION INPUT ;
    USE SIGNAL ;
    PORT
      LAYER M4 ;
        RECT  172.758 99.072 172.842 99.096 ;
    END
  END i_pkt[32]
  PIN i_pkt[330]
    DIRECTION INPUT ;
    USE SIGNAL ;
    PORT
      LAYER M4 ;
        RECT  172.758 10.656 172.842 10.68 ;
    END
  END i_pkt[330]
  PIN i_pkt[331]
    DIRECTION INPUT ;
    USE SIGNAL ;
    PORT
      LAYER M4 ;
        RECT  172.758 10.752 172.842 10.776 ;
    END
  END i_pkt[331]
  PIN i_pkt[332]
    DIRECTION INPUT ;
    USE SIGNAL ;
    PORT
      LAYER M4 ;
        RECT  172.758 10.848 172.842 10.872 ;
    END
  END i_pkt[332]
  PIN i_pkt[333]
    DIRECTION INPUT ;
    USE SIGNAL ;
    PORT
      LAYER M4 ;
        RECT  172.758 10.944 172.842 10.968 ;
    END
  END i_pkt[333]
  PIN i_pkt[334]
    DIRECTION INPUT ;
    USE SIGNAL ;
    PORT
      LAYER M4 ;
        RECT  172.758 11.04 172.842 11.064 ;
    END
  END i_pkt[334]
  PIN i_pkt[335]
    DIRECTION INPUT ;
    USE SIGNAL ;
    PORT
      LAYER M4 ;
        RECT  172.758 11.136 172.842 11.16 ;
    END
  END i_pkt[335]
  PIN i_pkt[336]
    DIRECTION INPUT ;
    USE SIGNAL ;
    PORT
      LAYER M4 ;
        RECT  172.758 11.232 172.842 11.256 ;
    END
  END i_pkt[336]
  PIN i_pkt[337]
    DIRECTION INPUT ;
    USE SIGNAL ;
    PORT
      LAYER M4 ;
        RECT  172.758 11.328 172.842 11.352 ;
    END
  END i_pkt[337]
  PIN i_pkt[338]
    DIRECTION INPUT ;
    USE SIGNAL ;
    PORT
      LAYER M4 ;
        RECT  172.758 11.424 172.842 11.448 ;
    END
  END i_pkt[338]
  PIN i_pkt[339]
    DIRECTION INPUT ;
    USE SIGNAL ;
    PORT
      LAYER M4 ;
        RECT  172.758 11.52 172.842 11.544 ;
    END
  END i_pkt[339]
  PIN i_pkt[33]
    DIRECTION INPUT ;
    USE SIGNAL ;
    PORT
      LAYER M4 ;
        RECT  172.758 99.168 172.842 99.192 ;
    END
  END i_pkt[33]
  PIN i_pkt[340]
    DIRECTION INPUT ;
    USE SIGNAL ;
    PORT
      LAYER M4 ;
        RECT  172.758 11.616 172.842 11.64 ;
    END
  END i_pkt[340]
  PIN i_pkt[341]
    DIRECTION INPUT ;
    USE SIGNAL ;
    PORT
      LAYER M4 ;
        RECT  172.758 11.712 172.842 11.736 ;
    END
  END i_pkt[341]
  PIN i_pkt[342]
    DIRECTION INPUT ;
    USE SIGNAL ;
    PORT
      LAYER M4 ;
        RECT  172.758 11.808 172.842 11.832 ;
    END
  END i_pkt[342]
  PIN i_pkt[343]
    DIRECTION INPUT ;
    USE SIGNAL ;
    PORT
      LAYER M4 ;
        RECT  172.758 11.904 172.842 11.928 ;
    END
  END i_pkt[343]
  PIN i_pkt[344]
    DIRECTION INPUT ;
    USE SIGNAL ;
    PORT
      LAYER M4 ;
        RECT  172.758 12 172.842 12.024 ;
    END
  END i_pkt[344]
  PIN i_pkt[345]
    DIRECTION INPUT ;
    USE SIGNAL ;
    PORT
      LAYER M4 ;
        RECT  172.758 12.096 172.842 12.12 ;
    END
  END i_pkt[345]
  PIN i_pkt[346]
    DIRECTION INPUT ;
    USE SIGNAL ;
    PORT
      LAYER M4 ;
        RECT  172.758 12.192 172.842 12.216 ;
    END
  END i_pkt[346]
  PIN i_pkt[347]
    DIRECTION INPUT ;
    USE SIGNAL ;
    PORT
      LAYER M4 ;
        RECT  172.758 12.288 172.842 12.312 ;
    END
  END i_pkt[347]
  PIN i_pkt[348]
    DIRECTION INPUT ;
    USE SIGNAL ;
    PORT
      LAYER M4 ;
        RECT  172.758 12.384 172.842 12.408 ;
    END
  END i_pkt[348]
  PIN i_pkt[349]
    DIRECTION INPUT ;
    USE SIGNAL ;
    PORT
      LAYER M4 ;
        RECT  172.758 12.48 172.842 12.504 ;
    END
  END i_pkt[349]
  PIN i_pkt[34]
    DIRECTION INPUT ;
    USE SIGNAL ;
    PORT
      LAYER M4 ;
        RECT  172.758 99.264 172.842 99.288 ;
    END
  END i_pkt[34]
  PIN i_pkt[350]
    DIRECTION INPUT ;
    USE SIGNAL ;
    PORT
      LAYER M4 ;
        RECT  172.758 12.576 172.842 12.6 ;
    END
  END i_pkt[350]
  PIN i_pkt[351]
    DIRECTION INPUT ;
    USE SIGNAL ;
    PORT
      LAYER M4 ;
        RECT  172.758 12.672 172.842 12.696 ;
    END
  END i_pkt[351]
  PIN i_pkt[352]
    DIRECTION INPUT ;
    USE SIGNAL ;
    PORT
      LAYER M4 ;
        RECT  172.758 12.768 172.842 12.792 ;
    END
  END i_pkt[352]
  PIN i_pkt[353]
    DIRECTION INPUT ;
    USE SIGNAL ;
    PORT
      LAYER M4 ;
        RECT  172.758 12.864 172.842 12.888 ;
    END
  END i_pkt[353]
  PIN i_pkt[354]
    DIRECTION INPUT ;
    USE SIGNAL ;
    PORT
      LAYER M4 ;
        RECT  172.758 12.96 172.842 12.984 ;
    END
  END i_pkt[354]
  PIN i_pkt[355]
    DIRECTION INPUT ;
    USE SIGNAL ;
    PORT
      LAYER M4 ;
        RECT  172.758 13.056 172.842 13.08 ;
    END
  END i_pkt[355]
  PIN i_pkt[356]
    DIRECTION INPUT ;
    USE SIGNAL ;
    PORT
      LAYER M4 ;
        RECT  172.758 13.152 172.842 13.176 ;
    END
  END i_pkt[356]
  PIN i_pkt[357]
    DIRECTION INPUT ;
    USE SIGNAL ;
    PORT
      LAYER M4 ;
        RECT  172.758 13.248 172.842 13.272 ;
    END
  END i_pkt[357]
  PIN i_pkt[358]
    DIRECTION INPUT ;
    USE SIGNAL ;
    PORT
      LAYER M4 ;
        RECT  172.758 13.344 172.842 13.368 ;
    END
  END i_pkt[358]
  PIN i_pkt[359]
    DIRECTION INPUT ;
    USE SIGNAL ;
    PORT
      LAYER M4 ;
        RECT  172.758 13.44 172.842 13.464 ;
    END
  END i_pkt[359]
  PIN i_pkt[35]
    DIRECTION INPUT ;
    USE SIGNAL ;
    PORT
      LAYER M4 ;
        RECT  172.758 99.36 172.842 99.384 ;
    END
  END i_pkt[35]
  PIN i_pkt[360]
    DIRECTION INPUT ;
    USE SIGNAL ;
    PORT
      LAYER M4 ;
        RECT  172.758 13.536 172.842 13.56 ;
    END
  END i_pkt[360]
  PIN i_pkt[361]
    DIRECTION INPUT ;
    USE SIGNAL ;
    PORT
      LAYER M4 ;
        RECT  172.758 13.632 172.842 13.656 ;
    END
  END i_pkt[361]
  PIN i_pkt[362]
    DIRECTION INPUT ;
    USE SIGNAL ;
    PORT
      LAYER M4 ;
        RECT  172.758 13.728 172.842 13.752 ;
    END
  END i_pkt[362]
  PIN i_pkt[363]
    DIRECTION INPUT ;
    USE SIGNAL ;
    PORT
      LAYER M4 ;
        RECT  172.758 13.824 172.842 13.848 ;
    END
  END i_pkt[363]
  PIN i_pkt[364]
    DIRECTION INPUT ;
    USE SIGNAL ;
    PORT
      LAYER M4 ;
        RECT  172.758 13.92 172.842 13.944 ;
    END
  END i_pkt[364]
  PIN i_pkt[365]
    DIRECTION INPUT ;
    USE SIGNAL ;
    PORT
      LAYER M4 ;
        RECT  172.758 14.016 172.842 14.04 ;
    END
  END i_pkt[365]
  PIN i_pkt[366]
    DIRECTION INPUT ;
    USE SIGNAL ;
    PORT
      LAYER M4 ;
        RECT  172.758 14.112 172.842 14.136 ;
    END
  END i_pkt[366]
  PIN i_pkt[367]
    DIRECTION INPUT ;
    USE SIGNAL ;
    PORT
      LAYER M4 ;
        RECT  172.758 14.208 172.842 14.232 ;
    END
  END i_pkt[367]
  PIN i_pkt[368]
    DIRECTION INPUT ;
    USE SIGNAL ;
    PORT
      LAYER M4 ;
        RECT  172.758 14.304 172.842 14.328 ;
    END
  END i_pkt[368]
  PIN i_pkt[369]
    DIRECTION INPUT ;
    USE SIGNAL ;
    PORT
      LAYER M4 ;
        RECT  172.758 14.4 172.842 14.424 ;
    END
  END i_pkt[369]
  PIN i_pkt[36]
    DIRECTION INPUT ;
    USE SIGNAL ;
    PORT
      LAYER M4 ;
        RECT  172.758 99.456 172.842 99.48 ;
    END
  END i_pkt[36]
  PIN i_pkt[370]
    DIRECTION INPUT ;
    USE SIGNAL ;
    PORT
      LAYER M4 ;
        RECT  172.758 14.496 172.842 14.52 ;
    END
  END i_pkt[370]
  PIN i_pkt[371]
    DIRECTION INPUT ;
    USE SIGNAL ;
    PORT
      LAYER M4 ;
        RECT  172.758 14.592 172.842 14.616 ;
    END
  END i_pkt[371]
  PIN i_pkt[372]
    DIRECTION INPUT ;
    USE SIGNAL ;
    PORT
      LAYER M4 ;
        RECT  172.758 14.688 172.842 14.712 ;
    END
  END i_pkt[372]
  PIN i_pkt[373]
    DIRECTION INPUT ;
    USE SIGNAL ;
    PORT
      LAYER M4 ;
        RECT  172.758 14.784 172.842 14.808 ;
    END
  END i_pkt[373]
  PIN i_pkt[374]
    DIRECTION INPUT ;
    USE SIGNAL ;
    PORT
      LAYER M4 ;
        RECT  172.758 14.88 172.842 14.904 ;
    END
  END i_pkt[374]
  PIN i_pkt[375]
    DIRECTION INPUT ;
    USE SIGNAL ;
    PORT
      LAYER M4 ;
        RECT  172.758 14.976 172.842 15 ;
    END
  END i_pkt[375]
  PIN i_pkt[376]
    DIRECTION INPUT ;
    USE SIGNAL ;
    PORT
      LAYER M4 ;
        RECT  172.758 15.072 172.842 15.096 ;
    END
  END i_pkt[376]
  PIN i_pkt[377]
    DIRECTION INPUT ;
    USE SIGNAL ;
    PORT
      LAYER M4 ;
        RECT  172.758 15.168 172.842 15.192 ;
    END
  END i_pkt[377]
  PIN i_pkt[378]
    DIRECTION INPUT ;
    USE SIGNAL ;
    PORT
      LAYER M4 ;
        RECT  172.758 15.264 172.842 15.288 ;
    END
  END i_pkt[378]
  PIN i_pkt[379]
    DIRECTION INPUT ;
    USE SIGNAL ;
    PORT
      LAYER M4 ;
        RECT  172.758 15.36 172.842 15.384 ;
    END
  END i_pkt[379]
  PIN i_pkt[37]
    DIRECTION INPUT ;
    USE SIGNAL ;
    PORT
      LAYER M4 ;
        RECT  172.758 99.552 172.842 99.576 ;
    END
  END i_pkt[37]
  PIN i_pkt[380]
    DIRECTION INPUT ;
    USE SIGNAL ;
    PORT
      LAYER M4 ;
        RECT  172.758 15.456 172.842 15.48 ;
    END
  END i_pkt[380]
  PIN i_pkt[381]
    DIRECTION INPUT ;
    USE SIGNAL ;
    PORT
      LAYER M4 ;
        RECT  172.758 15.552 172.842 15.576 ;
    END
  END i_pkt[381]
  PIN i_pkt[382]
    DIRECTION INPUT ;
    USE SIGNAL ;
    PORT
      LAYER M4 ;
        RECT  172.758 15.648 172.842 15.672 ;
    END
  END i_pkt[382]
  PIN i_pkt[383]
    DIRECTION INPUT ;
    USE SIGNAL ;
    PORT
      LAYER M4 ;
        RECT  172.758 15.744 172.842 15.768 ;
    END
  END i_pkt[383]
  PIN i_pkt[384]
    DIRECTION INPUT ;
    USE SIGNAL ;
    PORT
      LAYER M4 ;
        RECT  172.758 15.84 172.842 15.864 ;
    END
  END i_pkt[384]
  PIN i_pkt[385]
    DIRECTION INPUT ;
    USE SIGNAL ;
    PORT
      LAYER M4 ;
        RECT  172.758 15.936 172.842 15.96 ;
    END
  END i_pkt[385]
  PIN i_pkt[386]
    DIRECTION INPUT ;
    USE SIGNAL ;
    PORT
      LAYER M4 ;
        RECT  172.758 16.032 172.842 16.056 ;
    END
  END i_pkt[386]
  PIN i_pkt[387]
    DIRECTION INPUT ;
    USE SIGNAL ;
    PORT
      LAYER M4 ;
        RECT  172.758 16.128 172.842 16.152 ;
    END
  END i_pkt[387]
  PIN i_pkt[388]
    DIRECTION INPUT ;
    USE SIGNAL ;
    PORT
      LAYER M4 ;
        RECT  172.758 16.224 172.842 16.248 ;
    END
  END i_pkt[388]
  PIN i_pkt[389]
    DIRECTION INPUT ;
    USE SIGNAL ;
    PORT
      LAYER M4 ;
        RECT  172.758 16.32 172.842 16.344 ;
    END
  END i_pkt[389]
  PIN i_pkt[38]
    DIRECTION INPUT ;
    USE SIGNAL ;
    PORT
      LAYER M4 ;
        RECT  172.758 99.648 172.842 99.672 ;
    END
  END i_pkt[38]
  PIN i_pkt[390]
    DIRECTION INPUT ;
    USE SIGNAL ;
    PORT
      LAYER M4 ;
        RECT  172.758 16.416 172.842 16.44 ;
    END
  END i_pkt[390]
  PIN i_pkt[391]
    DIRECTION INPUT ;
    USE SIGNAL ;
    PORT
      LAYER M4 ;
        RECT  172.758 16.512 172.842 16.536 ;
    END
  END i_pkt[391]
  PIN i_pkt[392]
    DIRECTION INPUT ;
    USE SIGNAL ;
    PORT
      LAYER M4 ;
        RECT  172.758 16.608 172.842 16.632 ;
    END
  END i_pkt[392]
  PIN i_pkt[393]
    DIRECTION INPUT ;
    USE SIGNAL ;
    PORT
      LAYER M4 ;
        RECT  172.758 16.704 172.842 16.728 ;
    END
  END i_pkt[393]
  PIN i_pkt[394]
    DIRECTION INPUT ;
    USE SIGNAL ;
    PORT
      LAYER M4 ;
        RECT  172.758 16.8 172.842 16.824 ;
    END
  END i_pkt[394]
  PIN i_pkt[395]
    DIRECTION INPUT ;
    USE SIGNAL ;
    PORT
      LAYER M4 ;
        RECT  172.758 16.896 172.842 16.92 ;
    END
  END i_pkt[395]
  PIN i_pkt[396]
    DIRECTION INPUT ;
    USE SIGNAL ;
    PORT
      LAYER M4 ;
        RECT  172.758 16.992 172.842 17.016 ;
    END
  END i_pkt[396]
  PIN i_pkt[397]
    DIRECTION INPUT ;
    USE SIGNAL ;
    PORT
      LAYER M4 ;
        RECT  172.758 17.088 172.842 17.112 ;
    END
  END i_pkt[397]
  PIN i_pkt[398]
    DIRECTION INPUT ;
    USE SIGNAL ;
    PORT
      LAYER M4 ;
        RECT  172.758 17.184 172.842 17.208 ;
    END
  END i_pkt[398]
  PIN i_pkt[399]
    DIRECTION INPUT ;
    USE SIGNAL ;
    PORT
      LAYER M4 ;
        RECT  172.758 17.28 172.842 17.304 ;
    END
  END i_pkt[399]
  PIN i_pkt[39]
    DIRECTION INPUT ;
    USE SIGNAL ;
    PORT
      LAYER M4 ;
        RECT  172.758 99.744 172.842 99.768 ;
    END
  END i_pkt[39]
  PIN i_pkt[3]
    DIRECTION INPUT ;
    USE SIGNAL ;
    PORT
      LAYER M4 ;
        RECT  172.758 96.288 172.842 96.312 ;
    END
  END i_pkt[3]
  PIN i_pkt[400]
    DIRECTION INPUT ;
    USE SIGNAL ;
    PORT
      LAYER M4 ;
        RECT  172.758 17.376 172.842 17.4 ;
    END
  END i_pkt[400]
  PIN i_pkt[401]
    DIRECTION INPUT ;
    USE SIGNAL ;
    PORT
      LAYER M4 ;
        RECT  172.758 17.472 172.842 17.496 ;
    END
  END i_pkt[401]
  PIN i_pkt[402]
    DIRECTION INPUT ;
    USE SIGNAL ;
    PORT
      LAYER M4 ;
        RECT  172.758 17.568 172.842 17.592 ;
    END
  END i_pkt[402]
  PIN i_pkt[403]
    DIRECTION INPUT ;
    USE SIGNAL ;
    PORT
      LAYER M4 ;
        RECT  172.758 17.664 172.842 17.688 ;
    END
  END i_pkt[403]
  PIN i_pkt[404]
    DIRECTION INPUT ;
    USE SIGNAL ;
    PORT
      LAYER M4 ;
        RECT  172.758 17.76 172.842 17.784 ;
    END
  END i_pkt[404]
  PIN i_pkt[405]
    DIRECTION INPUT ;
    USE SIGNAL ;
    PORT
      LAYER M4 ;
        RECT  172.758 17.856 172.842 17.88 ;
    END
  END i_pkt[405]
  PIN i_pkt[406]
    DIRECTION INPUT ;
    USE SIGNAL ;
    PORT
      LAYER M4 ;
        RECT  172.758 17.952 172.842 17.976 ;
    END
  END i_pkt[406]
  PIN i_pkt[407]
    DIRECTION INPUT ;
    USE SIGNAL ;
    PORT
      LAYER M4 ;
        RECT  172.758 18.048 172.842 18.072 ;
    END
  END i_pkt[407]
  PIN i_pkt[408]
    DIRECTION INPUT ;
    USE SIGNAL ;
    PORT
      LAYER M4 ;
        RECT  172.758 18.144 172.842 18.168 ;
    END
  END i_pkt[408]
  PIN i_pkt[409]
    DIRECTION INPUT ;
    USE SIGNAL ;
    PORT
      LAYER M4 ;
        RECT  172.758 18.24 172.842 18.264 ;
    END
  END i_pkt[409]
  PIN i_pkt[40]
    DIRECTION INPUT ;
    USE SIGNAL ;
    PORT
      LAYER M4 ;
        RECT  172.758 99.84 172.842 99.864 ;
    END
  END i_pkt[40]
  PIN i_pkt[410]
    DIRECTION INPUT ;
    USE SIGNAL ;
    PORT
      LAYER M4 ;
        RECT  172.758 18.336 172.842 18.36 ;
    END
  END i_pkt[410]
  PIN i_pkt[411]
    DIRECTION INPUT ;
    USE SIGNAL ;
    PORT
      LAYER M4 ;
        RECT  172.758 18.432 172.842 18.456 ;
    END
  END i_pkt[411]
  PIN i_pkt[412]
    DIRECTION INPUT ;
    USE SIGNAL ;
    PORT
      LAYER M4 ;
        RECT  172.758 18.528 172.842 18.552 ;
    END
  END i_pkt[412]
  PIN i_pkt[413]
    DIRECTION INPUT ;
    USE SIGNAL ;
    PORT
      LAYER M4 ;
        RECT  172.758 18.624 172.842 18.648 ;
    END
  END i_pkt[413]
  PIN i_pkt[414]
    DIRECTION INPUT ;
    USE SIGNAL ;
    PORT
      LAYER M4 ;
        RECT  172.758 18.72 172.842 18.744 ;
    END
  END i_pkt[414]
  PIN i_pkt[415]
    DIRECTION INPUT ;
    USE SIGNAL ;
    PORT
      LAYER M4 ;
        RECT  172.758 18.816 172.842 18.84 ;
    END
  END i_pkt[415]
  PIN i_pkt[416]
    DIRECTION INPUT ;
    USE SIGNAL ;
    PORT
      LAYER M4 ;
        RECT  172.758 18.912 172.842 18.936 ;
    END
  END i_pkt[416]
  PIN i_pkt[417]
    DIRECTION INPUT ;
    USE SIGNAL ;
    PORT
      LAYER M4 ;
        RECT  172.758 19.008 172.842 19.032 ;
    END
  END i_pkt[417]
  PIN i_pkt[418]
    DIRECTION INPUT ;
    USE SIGNAL ;
    PORT
      LAYER M4 ;
        RECT  172.758 19.104 172.842 19.128 ;
    END
  END i_pkt[418]
  PIN i_pkt[419]
    DIRECTION INPUT ;
    USE SIGNAL ;
    PORT
      LAYER M4 ;
        RECT  172.758 19.2 172.842 19.224 ;
    END
  END i_pkt[419]
  PIN i_pkt[41]
    DIRECTION INPUT ;
    USE SIGNAL ;
    PORT
      LAYER M4 ;
        RECT  172.758 99.936 172.842 99.96 ;
    END
  END i_pkt[41]
  PIN i_pkt[420]
    DIRECTION INPUT ;
    USE SIGNAL ;
    PORT
      LAYER M4 ;
        RECT  172.758 19.296 172.842 19.32 ;
    END
  END i_pkt[420]
  PIN i_pkt[421]
    DIRECTION INPUT ;
    USE SIGNAL ;
    PORT
      LAYER M4 ;
        RECT  172.758 19.392 172.842 19.416 ;
    END
  END i_pkt[421]
  PIN i_pkt[422]
    DIRECTION INPUT ;
    USE SIGNAL ;
    PORT
      LAYER M4 ;
        RECT  172.758 19.488 172.842 19.512 ;
    END
  END i_pkt[422]
  PIN i_pkt[423]
    DIRECTION INPUT ;
    USE SIGNAL ;
    PORT
      LAYER M4 ;
        RECT  172.758 19.584 172.842 19.608 ;
    END
  END i_pkt[423]
  PIN i_pkt[424]
    DIRECTION INPUT ;
    USE SIGNAL ;
    PORT
      LAYER M4 ;
        RECT  172.758 19.68 172.842 19.704 ;
    END
  END i_pkt[424]
  PIN i_pkt[425]
    DIRECTION INPUT ;
    USE SIGNAL ;
    PORT
      LAYER M4 ;
        RECT  172.758 19.776 172.842 19.8 ;
    END
  END i_pkt[425]
  PIN i_pkt[426]
    DIRECTION INPUT ;
    USE SIGNAL ;
    PORT
      LAYER M4 ;
        RECT  172.758 19.872 172.842 19.896 ;
    END
  END i_pkt[426]
  PIN i_pkt[427]
    DIRECTION INPUT ;
    USE SIGNAL ;
    PORT
      LAYER M4 ;
        RECT  172.758 19.968 172.842 19.992 ;
    END
  END i_pkt[427]
  PIN i_pkt[428]
    DIRECTION INPUT ;
    USE SIGNAL ;
    PORT
      LAYER M4 ;
        RECT  172.758 20.064 172.842 20.088 ;
    END
  END i_pkt[428]
  PIN i_pkt[429]
    DIRECTION INPUT ;
    USE SIGNAL ;
    PORT
      LAYER M4 ;
        RECT  172.758 20.16 172.842 20.184 ;
    END
  END i_pkt[429]
  PIN i_pkt[42]
    DIRECTION INPUT ;
    USE SIGNAL ;
    PORT
      LAYER M4 ;
        RECT  172.758 100.032 172.842 100.056 ;
    END
  END i_pkt[42]
  PIN i_pkt[430]
    DIRECTION INPUT ;
    USE SIGNAL ;
    PORT
      LAYER M4 ;
        RECT  172.758 20.256 172.842 20.28 ;
    END
  END i_pkt[430]
  PIN i_pkt[431]
    DIRECTION INPUT ;
    USE SIGNAL ;
    PORT
      LAYER M4 ;
        RECT  172.758 20.352 172.842 20.376 ;
    END
  END i_pkt[431]
  PIN i_pkt[432]
    DIRECTION INPUT ;
    USE SIGNAL ;
    PORT
      LAYER M4 ;
        RECT  172.758 20.448 172.842 20.472 ;
    END
  END i_pkt[432]
  PIN i_pkt[433]
    DIRECTION INPUT ;
    USE SIGNAL ;
    PORT
      LAYER M4 ;
        RECT  172.758 20.544 172.842 20.568 ;
    END
  END i_pkt[433]
  PIN i_pkt[434]
    DIRECTION INPUT ;
    USE SIGNAL ;
    PORT
      LAYER M4 ;
        RECT  172.758 20.64 172.842 20.664 ;
    END
  END i_pkt[434]
  PIN i_pkt[435]
    DIRECTION INPUT ;
    USE SIGNAL ;
    PORT
      LAYER M4 ;
        RECT  172.758 20.736 172.842 20.76 ;
    END
  END i_pkt[435]
  PIN i_pkt[436]
    DIRECTION INPUT ;
    USE SIGNAL ;
    PORT
      LAYER M4 ;
        RECT  172.758 20.832 172.842 20.856 ;
    END
  END i_pkt[436]
  PIN i_pkt[437]
    DIRECTION INPUT ;
    USE SIGNAL ;
    PORT
      LAYER M4 ;
        RECT  172.758 20.928 172.842 20.952 ;
    END
  END i_pkt[437]
  PIN i_pkt[438]
    DIRECTION INPUT ;
    USE SIGNAL ;
    PORT
      LAYER M4 ;
        RECT  172.758 21.024 172.842 21.048 ;
    END
  END i_pkt[438]
  PIN i_pkt[439]
    DIRECTION INPUT ;
    USE SIGNAL ;
    PORT
      LAYER M4 ;
        RECT  172.758 21.12 172.842 21.144 ;
    END
  END i_pkt[439]
  PIN i_pkt[43]
    DIRECTION INPUT ;
    USE SIGNAL ;
    PORT
      LAYER M4 ;
        RECT  172.758 100.128 172.842 100.152 ;
    END
  END i_pkt[43]
  PIN i_pkt[440]
    DIRECTION INPUT ;
    USE SIGNAL ;
    PORT
      LAYER M4 ;
        RECT  172.758 21.216 172.842 21.24 ;
    END
  END i_pkt[440]
  PIN i_pkt[441]
    DIRECTION INPUT ;
    USE SIGNAL ;
    PORT
      LAYER M4 ;
        RECT  172.758 21.312 172.842 21.336 ;
    END
  END i_pkt[441]
  PIN i_pkt[442]
    DIRECTION INPUT ;
    USE SIGNAL ;
    PORT
      LAYER M4 ;
        RECT  172.758 21.408 172.842 21.432 ;
    END
  END i_pkt[442]
  PIN i_pkt[443]
    DIRECTION INPUT ;
    USE SIGNAL ;
    PORT
      LAYER M4 ;
        RECT  172.758 21.504 172.842 21.528 ;
    END
  END i_pkt[443]
  PIN i_pkt[444]
    DIRECTION INPUT ;
    USE SIGNAL ;
    PORT
      LAYER M4 ;
        RECT  172.758 21.6 172.842 21.624 ;
    END
  END i_pkt[444]
  PIN i_pkt[445]
    DIRECTION INPUT ;
    USE SIGNAL ;
    PORT
      LAYER M4 ;
        RECT  172.758 21.696 172.842 21.72 ;
    END
  END i_pkt[445]
  PIN i_pkt[446]
    DIRECTION INPUT ;
    USE SIGNAL ;
    PORT
      LAYER M4 ;
        RECT  172.758 21.792 172.842 21.816 ;
    END
  END i_pkt[446]
  PIN i_pkt[447]
    DIRECTION INPUT ;
    USE SIGNAL ;
    PORT
      LAYER M4 ;
        RECT  172.758 21.888 172.842 21.912 ;
    END
  END i_pkt[447]
  PIN i_pkt[448]
    DIRECTION INPUT ;
    USE SIGNAL ;
    PORT
      LAYER M4 ;
        RECT  172.758 21.984 172.842 22.008 ;
    END
  END i_pkt[448]
  PIN i_pkt[449]
    DIRECTION INPUT ;
    USE SIGNAL ;
    PORT
      LAYER M4 ;
        RECT  172.758 22.08 172.842 22.104 ;
    END
  END i_pkt[449]
  PIN i_pkt[44]
    DIRECTION INPUT ;
    USE SIGNAL ;
    PORT
      LAYER M4 ;
        RECT  172.758 100.224 172.842 100.248 ;
    END
  END i_pkt[44]
  PIN i_pkt[450]
    DIRECTION INPUT ;
    USE SIGNAL ;
    PORT
      LAYER M4 ;
        RECT  172.758 22.176 172.842 22.2 ;
    END
  END i_pkt[450]
  PIN i_pkt[451]
    DIRECTION INPUT ;
    USE SIGNAL ;
    PORT
      LAYER M4 ;
        RECT  172.758 22.272 172.842 22.296 ;
    END
  END i_pkt[451]
  PIN i_pkt[452]
    DIRECTION INPUT ;
    USE SIGNAL ;
    PORT
      LAYER M4 ;
        RECT  172.758 22.368 172.842 22.392 ;
    END
  END i_pkt[452]
  PIN i_pkt[453]
    DIRECTION INPUT ;
    USE SIGNAL ;
    PORT
      LAYER M4 ;
        RECT  172.758 22.464 172.842 22.488 ;
    END
  END i_pkt[453]
  PIN i_pkt[454]
    DIRECTION INPUT ;
    USE SIGNAL ;
    PORT
      LAYER M4 ;
        RECT  172.758 22.56 172.842 22.584 ;
    END
  END i_pkt[454]
  PIN i_pkt[455]
    DIRECTION INPUT ;
    USE SIGNAL ;
    PORT
      LAYER M4 ;
        RECT  172.758 22.656 172.842 22.68 ;
    END
  END i_pkt[455]
  PIN i_pkt[456]
    DIRECTION INPUT ;
    USE SIGNAL ;
    PORT
      LAYER M4 ;
        RECT  172.758 22.752 172.842 22.776 ;
    END
  END i_pkt[456]
  PIN i_pkt[457]
    DIRECTION INPUT ;
    USE SIGNAL ;
    PORT
      LAYER M4 ;
        RECT  172.758 22.848 172.842 22.872 ;
    END
  END i_pkt[457]
  PIN i_pkt[458]
    DIRECTION INPUT ;
    USE SIGNAL ;
    PORT
      LAYER M4 ;
        RECT  172.758 22.944 172.842 22.968 ;
    END
  END i_pkt[458]
  PIN i_pkt[459]
    DIRECTION INPUT ;
    USE SIGNAL ;
    PORT
      LAYER M4 ;
        RECT  172.758 23.04 172.842 23.064 ;
    END
  END i_pkt[459]
  PIN i_pkt[45]
    DIRECTION INPUT ;
    USE SIGNAL ;
    PORT
      LAYER M4 ;
        RECT  172.758 100.32 172.842 100.344 ;
    END
  END i_pkt[45]
  PIN i_pkt[460]
    DIRECTION INPUT ;
    USE SIGNAL ;
    PORT
      LAYER M4 ;
        RECT  172.758 23.136 172.842 23.16 ;
    END
  END i_pkt[460]
  PIN i_pkt[461]
    DIRECTION INPUT ;
    USE SIGNAL ;
    PORT
      LAYER M4 ;
        RECT  172.758 23.232 172.842 23.256 ;
    END
  END i_pkt[461]
  PIN i_pkt[462]
    DIRECTION INPUT ;
    USE SIGNAL ;
    PORT
      LAYER M4 ;
        RECT  172.758 23.328 172.842 23.352 ;
    END
  END i_pkt[462]
  PIN i_pkt[463]
    DIRECTION INPUT ;
    USE SIGNAL ;
    PORT
      LAYER M4 ;
        RECT  172.758 23.424 172.842 23.448 ;
    END
  END i_pkt[463]
  PIN i_pkt[464]
    DIRECTION INPUT ;
    USE SIGNAL ;
    PORT
      LAYER M4 ;
        RECT  172.758 23.52 172.842 23.544 ;
    END
  END i_pkt[464]
  PIN i_pkt[465]
    DIRECTION INPUT ;
    USE SIGNAL ;
    PORT
      LAYER M4 ;
        RECT  172.758 23.616 172.842 23.64 ;
    END
  END i_pkt[465]
  PIN i_pkt[466]
    DIRECTION INPUT ;
    USE SIGNAL ;
    PORT
      LAYER M4 ;
        RECT  172.758 23.712 172.842 23.736 ;
    END
  END i_pkt[466]
  PIN i_pkt[467]
    DIRECTION INPUT ;
    USE SIGNAL ;
    PORT
      LAYER M4 ;
        RECT  172.758 23.808 172.842 23.832 ;
    END
  END i_pkt[467]
  PIN i_pkt[468]
    DIRECTION INPUT ;
    USE SIGNAL ;
    PORT
      LAYER M4 ;
        RECT  172.758 23.904 172.842 23.928 ;
    END
  END i_pkt[468]
  PIN i_pkt[469]
    DIRECTION INPUT ;
    USE SIGNAL ;
    PORT
      LAYER M4 ;
        RECT  172.758 24 172.842 24.024 ;
    END
  END i_pkt[469]
  PIN i_pkt[46]
    DIRECTION INPUT ;
    USE SIGNAL ;
    PORT
      LAYER M4 ;
        RECT  172.758 100.416 172.842 100.44 ;
    END
  END i_pkt[46]
  PIN i_pkt[470]
    DIRECTION INPUT ;
    USE SIGNAL ;
    PORT
      LAYER M4 ;
        RECT  172.758 24.096 172.842 24.12 ;
    END
  END i_pkt[470]
  PIN i_pkt[471]
    DIRECTION INPUT ;
    USE SIGNAL ;
    PORT
      LAYER M4 ;
        RECT  172.758 24.192 172.842 24.216 ;
    END
  END i_pkt[471]
  PIN i_pkt[472]
    DIRECTION INPUT ;
    USE SIGNAL ;
    PORT
      LAYER M4 ;
        RECT  172.758 24.288 172.842 24.312 ;
    END
  END i_pkt[472]
  PIN i_pkt[473]
    DIRECTION INPUT ;
    USE SIGNAL ;
    PORT
      LAYER M4 ;
        RECT  172.758 24.384 172.842 24.408 ;
    END
  END i_pkt[473]
  PIN i_pkt[474]
    DIRECTION INPUT ;
    USE SIGNAL ;
    PORT
      LAYER M4 ;
        RECT  172.758 24.48 172.842 24.504 ;
    END
  END i_pkt[474]
  PIN i_pkt[475]
    DIRECTION INPUT ;
    USE SIGNAL ;
    PORT
      LAYER M4 ;
        RECT  172.758 24.576 172.842 24.6 ;
    END
  END i_pkt[475]
  PIN i_pkt[476]
    DIRECTION INPUT ;
    USE SIGNAL ;
    PORT
      LAYER M4 ;
        RECT  172.758 24.672 172.842 24.696 ;
    END
  END i_pkt[476]
  PIN i_pkt[477]
    DIRECTION INPUT ;
    USE SIGNAL ;
    PORT
      LAYER M4 ;
        RECT  172.758 24.768 172.842 24.792 ;
    END
  END i_pkt[477]
  PIN i_pkt[478]
    DIRECTION INPUT ;
    USE SIGNAL ;
    PORT
      LAYER M4 ;
        RECT  172.758 24.864 172.842 24.888 ;
    END
  END i_pkt[478]
  PIN i_pkt[479]
    DIRECTION INPUT ;
    USE SIGNAL ;
    PORT
      LAYER M4 ;
        RECT  172.758 24.96 172.842 24.984 ;
    END
  END i_pkt[479]
  PIN i_pkt[47]
    DIRECTION INPUT ;
    USE SIGNAL ;
    PORT
      LAYER M4 ;
        RECT  172.758 100.512 172.842 100.536 ;
    END
  END i_pkt[47]
  PIN i_pkt[480]
    DIRECTION INPUT ;
    USE SIGNAL ;
    PORT
      LAYER M4 ;
        RECT  172.758 25.056 172.842 25.08 ;
    END
  END i_pkt[480]
  PIN i_pkt[481]
    DIRECTION INPUT ;
    USE SIGNAL ;
    PORT
      LAYER M4 ;
        RECT  172.758 25.152 172.842 25.176 ;
    END
  END i_pkt[481]
  PIN i_pkt[482]
    DIRECTION INPUT ;
    USE SIGNAL ;
    PORT
      LAYER M4 ;
        RECT  172.758 25.248 172.842 25.272 ;
    END
  END i_pkt[482]
  PIN i_pkt[483]
    DIRECTION INPUT ;
    USE SIGNAL ;
    PORT
      LAYER M4 ;
        RECT  172.758 25.344 172.842 25.368 ;
    END
  END i_pkt[483]
  PIN i_pkt[484]
    DIRECTION INPUT ;
    USE SIGNAL ;
    PORT
      LAYER M4 ;
        RECT  172.758 25.44 172.842 25.464 ;
    END
  END i_pkt[484]
  PIN i_pkt[485]
    DIRECTION INPUT ;
    USE SIGNAL ;
    PORT
      LAYER M4 ;
        RECT  172.758 25.536 172.842 25.56 ;
    END
  END i_pkt[485]
  PIN i_pkt[486]
    DIRECTION INPUT ;
    USE SIGNAL ;
    PORT
      LAYER M4 ;
        RECT  172.758 25.632 172.842 25.656 ;
    END
  END i_pkt[486]
  PIN i_pkt[487]
    DIRECTION INPUT ;
    USE SIGNAL ;
    PORT
      LAYER M4 ;
        RECT  172.758 25.728 172.842 25.752 ;
    END
  END i_pkt[487]
  PIN i_pkt[488]
    DIRECTION INPUT ;
    USE SIGNAL ;
    PORT
      LAYER M4 ;
        RECT  172.758 25.824 172.842 25.848 ;
    END
  END i_pkt[488]
  PIN i_pkt[489]
    DIRECTION INPUT ;
    USE SIGNAL ;
    PORT
      LAYER M4 ;
        RECT  172.758 25.92 172.842 25.944 ;
    END
  END i_pkt[489]
  PIN i_pkt[48]
    DIRECTION INPUT ;
    USE SIGNAL ;
    PORT
      LAYER M4 ;
        RECT  172.758 100.608 172.842 100.632 ;
    END
  END i_pkt[48]
  PIN i_pkt[490]
    DIRECTION INPUT ;
    USE SIGNAL ;
    PORT
      LAYER M4 ;
        RECT  172.758 26.016 172.842 26.04 ;
    END
  END i_pkt[490]
  PIN i_pkt[491]
    DIRECTION INPUT ;
    USE SIGNAL ;
    PORT
      LAYER M4 ;
        RECT  172.758 26.112 172.842 26.136 ;
    END
  END i_pkt[491]
  PIN i_pkt[492]
    DIRECTION INPUT ;
    USE SIGNAL ;
    PORT
      LAYER M4 ;
        RECT  172.758 26.208 172.842 26.232 ;
    END
  END i_pkt[492]
  PIN i_pkt[493]
    DIRECTION INPUT ;
    USE SIGNAL ;
    PORT
      LAYER M4 ;
        RECT  172.758 26.304 172.842 26.328 ;
    END
  END i_pkt[493]
  PIN i_pkt[494]
    DIRECTION INPUT ;
    USE SIGNAL ;
    PORT
      LAYER M4 ;
        RECT  172.758 26.4 172.842 26.424 ;
    END
  END i_pkt[494]
  PIN i_pkt[495]
    DIRECTION INPUT ;
    USE SIGNAL ;
    PORT
      LAYER M4 ;
        RECT  172.758 26.496 172.842 26.52 ;
    END
  END i_pkt[495]
  PIN i_pkt[496]
    DIRECTION INPUT ;
    USE SIGNAL ;
    PORT
      LAYER M4 ;
        RECT  172.758 26.592 172.842 26.616 ;
    END
  END i_pkt[496]
  PIN i_pkt[497]
    DIRECTION INPUT ;
    USE SIGNAL ;
    PORT
      LAYER M4 ;
        RECT  172.758 26.688 172.842 26.712 ;
    END
  END i_pkt[497]
  PIN i_pkt[498]
    DIRECTION INPUT ;
    USE SIGNAL ;
    PORT
      LAYER M4 ;
        RECT  172.758 26.784 172.842 26.808 ;
    END
  END i_pkt[498]
  PIN i_pkt[499]
    DIRECTION INPUT ;
    USE SIGNAL ;
    PORT
      LAYER M4 ;
        RECT  172.758 26.88 172.842 26.904 ;
    END
  END i_pkt[499]
  PIN i_pkt[49]
    DIRECTION INPUT ;
    USE SIGNAL ;
    PORT
      LAYER M4 ;
        RECT  172.758 100.704 172.842 100.728 ;
    END
  END i_pkt[49]
  PIN i_pkt[4]
    DIRECTION INPUT ;
    USE SIGNAL ;
    PORT
      LAYER M4 ;
        RECT  172.758 96.384 172.842 96.408 ;
    END
  END i_pkt[4]
  PIN i_pkt[500]
    DIRECTION INPUT ;
    USE SIGNAL ;
    PORT
      LAYER M4 ;
        RECT  172.758 26.976 172.842 27 ;
    END
  END i_pkt[500]
  PIN i_pkt[501]
    DIRECTION INPUT ;
    USE SIGNAL ;
    PORT
      LAYER M4 ;
        RECT  172.758 27.072 172.842 27.096 ;
    END
  END i_pkt[501]
  PIN i_pkt[502]
    DIRECTION INPUT ;
    USE SIGNAL ;
    PORT
      LAYER M4 ;
        RECT  172.758 27.168 172.842 27.192 ;
    END
  END i_pkt[502]
  PIN i_pkt[503]
    DIRECTION INPUT ;
    USE SIGNAL ;
    PORT
      LAYER M4 ;
        RECT  172.758 27.264 172.842 27.288 ;
    END
  END i_pkt[503]
  PIN i_pkt[504]
    DIRECTION INPUT ;
    USE SIGNAL ;
    PORT
      LAYER M4 ;
        RECT  172.758 27.36 172.842 27.384 ;
    END
  END i_pkt[504]
  PIN i_pkt[505]
    DIRECTION INPUT ;
    USE SIGNAL ;
    PORT
      LAYER M4 ;
        RECT  172.758 27.456 172.842 27.48 ;
    END
  END i_pkt[505]
  PIN i_pkt[506]
    DIRECTION INPUT ;
    USE SIGNAL ;
    PORT
      LAYER M4 ;
        RECT  172.758 27.552 172.842 27.576 ;
    END
  END i_pkt[506]
  PIN i_pkt[507]
    DIRECTION INPUT ;
    USE SIGNAL ;
    PORT
      LAYER M4 ;
        RECT  172.758 27.648 172.842 27.672 ;
    END
  END i_pkt[507]
  PIN i_pkt[508]
    DIRECTION INPUT ;
    USE SIGNAL ;
    PORT
      LAYER M4 ;
        RECT  172.758 27.744 172.842 27.768 ;
    END
  END i_pkt[508]
  PIN i_pkt[509]
    DIRECTION INPUT ;
    USE SIGNAL ;
    PORT
      LAYER M4 ;
        RECT  172.758 27.84 172.842 27.864 ;
    END
  END i_pkt[509]
  PIN i_pkt[50]
    DIRECTION INPUT ;
    USE SIGNAL ;
    PORT
      LAYER M4 ;
        RECT  172.758 100.8 172.842 100.824 ;
    END
  END i_pkt[50]
  PIN i_pkt[510]
    DIRECTION INPUT ;
    USE SIGNAL ;
    PORT
      LAYER M4 ;
        RECT  172.758 27.936 172.842 27.96 ;
    END
  END i_pkt[510]
  PIN i_pkt[511]
    DIRECTION INPUT ;
    USE SIGNAL ;
    PORT
      LAYER M4 ;
        RECT  172.758 28.032 172.842 28.056 ;
    END
  END i_pkt[511]
  PIN i_pkt[512]
    DIRECTION INPUT ;
    USE SIGNAL ;
    PORT
      LAYER M4 ;
        RECT  172.758 28.128 172.842 28.152 ;
    END
  END i_pkt[512]
  PIN i_pkt[513]
    DIRECTION INPUT ;
    USE SIGNAL ;
    PORT
      LAYER M4 ;
        RECT  172.758 28.224 172.842 28.248 ;
    END
  END i_pkt[513]
  PIN i_pkt[514]
    DIRECTION INPUT ;
    USE SIGNAL ;
    PORT
      LAYER M4 ;
        RECT  172.758 28.32 172.842 28.344 ;
    END
  END i_pkt[514]
  PIN i_pkt[515]
    DIRECTION INPUT ;
    USE SIGNAL ;
    PORT
      LAYER M4 ;
        RECT  172.758 28.416 172.842 28.44 ;
    END
  END i_pkt[515]
  PIN i_pkt[516]
    DIRECTION INPUT ;
    USE SIGNAL ;
    PORT
      LAYER M4 ;
        RECT  172.758 28.512 172.842 28.536 ;
    END
  END i_pkt[516]
  PIN i_pkt[517]
    DIRECTION INPUT ;
    USE SIGNAL ;
    PORT
      LAYER M4 ;
        RECT  172.758 28.608 172.842 28.632 ;
    END
  END i_pkt[517]
  PIN i_pkt[518]
    DIRECTION INPUT ;
    USE SIGNAL ;
    PORT
      LAYER M4 ;
        RECT  172.758 28.704 172.842 28.728 ;
    END
  END i_pkt[518]
  PIN i_pkt[519]
    DIRECTION INPUT ;
    USE SIGNAL ;
    PORT
      LAYER M4 ;
        RECT  172.758 28.8 172.842 28.824 ;
    END
  END i_pkt[519]
  PIN i_pkt[51]
    DIRECTION INPUT ;
    USE SIGNAL ;
    PORT
      LAYER M4 ;
        RECT  172.758 100.896 172.842 100.92 ;
    END
  END i_pkt[51]
  PIN i_pkt[520]
    DIRECTION INPUT ;
    USE SIGNAL ;
    PORT
      LAYER M4 ;
        RECT  172.758 28.896 172.842 28.92 ;
    END
  END i_pkt[520]
  PIN i_pkt[521]
    DIRECTION INPUT ;
    USE SIGNAL ;
    PORT
      LAYER M4 ;
        RECT  172.758 28.992 172.842 29.016 ;
    END
  END i_pkt[521]
  PIN i_pkt[522]
    DIRECTION INPUT ;
    USE SIGNAL ;
    PORT
      LAYER M4 ;
        RECT  172.758 29.088 172.842 29.112 ;
    END
  END i_pkt[522]
  PIN i_pkt[523]
    DIRECTION INPUT ;
    USE SIGNAL ;
    PORT
      LAYER M4 ;
        RECT  172.758 29.184 172.842 29.208 ;
    END
  END i_pkt[523]
  PIN i_pkt[524]
    DIRECTION INPUT ;
    USE SIGNAL ;
    PORT
      LAYER M4 ;
        RECT  172.758 29.28 172.842 29.304 ;
    END
  END i_pkt[524]
  PIN i_pkt[525]
    DIRECTION INPUT ;
    USE SIGNAL ;
    PORT
      LAYER M4 ;
        RECT  172.758 29.376 172.842 29.4 ;
    END
  END i_pkt[525]
  PIN i_pkt[526]
    DIRECTION INPUT ;
    USE SIGNAL ;
    PORT
      LAYER M4 ;
        RECT  172.758 29.472 172.842 29.496 ;
    END
  END i_pkt[526]
  PIN i_pkt[527]
    DIRECTION INPUT ;
    USE SIGNAL ;
    PORT
      LAYER M4 ;
        RECT  172.758 29.568 172.842 29.592 ;
    END
  END i_pkt[527]
  PIN i_pkt[528]
    DIRECTION INPUT ;
    USE SIGNAL ;
    PORT
      LAYER M4 ;
        RECT  172.758 29.664 172.842 29.688 ;
    END
  END i_pkt[528]
  PIN i_pkt[529]
    DIRECTION INPUT ;
    USE SIGNAL ;
    PORT
      LAYER M4 ;
        RECT  172.758 29.76 172.842 29.784 ;
    END
  END i_pkt[529]
  PIN i_pkt[52]
    DIRECTION INPUT ;
    USE SIGNAL ;
    PORT
      LAYER M4 ;
        RECT  172.758 100.992 172.842 101.016 ;
    END
  END i_pkt[52]
  PIN i_pkt[530]
    DIRECTION INPUT ;
    USE SIGNAL ;
    PORT
      LAYER M4 ;
        RECT  172.758 29.856 172.842 29.88 ;
    END
  END i_pkt[530]
  PIN i_pkt[531]
    DIRECTION INPUT ;
    USE SIGNAL ;
    PORT
      LAYER M4 ;
        RECT  172.758 29.952 172.842 29.976 ;
    END
  END i_pkt[531]
  PIN i_pkt[532]
    DIRECTION INPUT ;
    USE SIGNAL ;
    PORT
      LAYER M4 ;
        RECT  172.758 30.048 172.842 30.072 ;
    END
  END i_pkt[532]
  PIN i_pkt[533]
    DIRECTION INPUT ;
    USE SIGNAL ;
    PORT
      LAYER M4 ;
        RECT  172.758 30.144 172.842 30.168 ;
    END
  END i_pkt[533]
  PIN i_pkt[534]
    DIRECTION INPUT ;
    USE SIGNAL ;
    PORT
      LAYER M4 ;
        RECT  172.758 30.24 172.842 30.264 ;
    END
  END i_pkt[534]
  PIN i_pkt[535]
    DIRECTION INPUT ;
    USE SIGNAL ;
    PORT
      LAYER M4 ;
        RECT  172.758 30.336 172.842 30.36 ;
    END
  END i_pkt[535]
  PIN i_pkt[536]
    DIRECTION INPUT ;
    USE SIGNAL ;
    PORT
      LAYER M4 ;
        RECT  172.758 30.432 172.842 30.456 ;
    END
  END i_pkt[536]
  PIN i_pkt[537]
    DIRECTION INPUT ;
    USE SIGNAL ;
    PORT
      LAYER M4 ;
        RECT  172.758 30.528 172.842 30.552 ;
    END
  END i_pkt[537]
  PIN i_pkt[538]
    DIRECTION INPUT ;
    USE SIGNAL ;
    PORT
      LAYER M4 ;
        RECT  172.758 30.624 172.842 30.648 ;
    END
  END i_pkt[538]
  PIN i_pkt[539]
    DIRECTION INPUT ;
    USE SIGNAL ;
    PORT
      LAYER M4 ;
        RECT  172.758 30.72 172.842 30.744 ;
    END
  END i_pkt[539]
  PIN i_pkt[53]
    DIRECTION INPUT ;
    USE SIGNAL ;
    PORT
      LAYER M4 ;
        RECT  172.758 101.088 172.842 101.112 ;
    END
  END i_pkt[53]
  PIN i_pkt[540]
    DIRECTION INPUT ;
    USE SIGNAL ;
    PORT
      LAYER M4 ;
        RECT  172.758 30.816 172.842 30.84 ;
    END
  END i_pkt[540]
  PIN i_pkt[541]
    DIRECTION INPUT ;
    USE SIGNAL ;
    PORT
      LAYER M4 ;
        RECT  172.758 30.912 172.842 30.936 ;
    END
  END i_pkt[541]
  PIN i_pkt[542]
    DIRECTION INPUT ;
    USE SIGNAL ;
    PORT
      LAYER M4 ;
        RECT  172.758 31.008 172.842 31.032 ;
    END
  END i_pkt[542]
  PIN i_pkt[543]
    DIRECTION INPUT ;
    USE SIGNAL ;
    PORT
      LAYER M4 ;
        RECT  172.758 31.104 172.842 31.128 ;
    END
  END i_pkt[543]
  PIN i_pkt[544]
    DIRECTION INPUT ;
    USE SIGNAL ;
    PORT
      LAYER M4 ;
        RECT  172.758 31.2 172.842 31.224 ;
    END
  END i_pkt[544]
  PIN i_pkt[545]
    DIRECTION INPUT ;
    USE SIGNAL ;
    PORT
      LAYER M4 ;
        RECT  172.758 31.296 172.842 31.32 ;
    END
  END i_pkt[545]
  PIN i_pkt[546]
    DIRECTION INPUT ;
    USE SIGNAL ;
    PORT
      LAYER M4 ;
        RECT  172.758 31.392 172.842 31.416 ;
    END
  END i_pkt[546]
  PIN i_pkt[547]
    DIRECTION INPUT ;
    USE SIGNAL ;
    PORT
      LAYER M4 ;
        RECT  172.758 31.488 172.842 31.512 ;
    END
  END i_pkt[547]
  PIN i_pkt[548]
    DIRECTION INPUT ;
    USE SIGNAL ;
    PORT
      LAYER M4 ;
        RECT  172.758 31.584 172.842 31.608 ;
    END
  END i_pkt[548]
  PIN i_pkt[549]
    DIRECTION INPUT ;
    USE SIGNAL ;
    PORT
      LAYER M4 ;
        RECT  172.758 31.68 172.842 31.704 ;
    END
  END i_pkt[549]
  PIN i_pkt[54]
    DIRECTION INPUT ;
    USE SIGNAL ;
    PORT
      LAYER M4 ;
        RECT  172.758 101.184 172.842 101.208 ;
    END
  END i_pkt[54]
  PIN i_pkt[550]
    DIRECTION INPUT ;
    USE SIGNAL ;
    PORT
      LAYER M4 ;
        RECT  172.758 31.776 172.842 31.8 ;
    END
  END i_pkt[550]
  PIN i_pkt[551]
    DIRECTION INPUT ;
    USE SIGNAL ;
    PORT
      LAYER M4 ;
        RECT  172.758 31.872 172.842 31.896 ;
    END
  END i_pkt[551]
  PIN i_pkt[552]
    DIRECTION INPUT ;
    USE SIGNAL ;
    PORT
      LAYER M4 ;
        RECT  172.758 31.968 172.842 31.992 ;
    END
  END i_pkt[552]
  PIN i_pkt[553]
    DIRECTION INPUT ;
    USE SIGNAL ;
    PORT
      LAYER M4 ;
        RECT  172.758 32.064 172.842 32.088 ;
    END
  END i_pkt[553]
  PIN i_pkt[554]
    DIRECTION INPUT ;
    USE SIGNAL ;
    PORT
      LAYER M4 ;
        RECT  172.758 32.16 172.842 32.184 ;
    END
  END i_pkt[554]
  PIN i_pkt[555]
    DIRECTION INPUT ;
    USE SIGNAL ;
    PORT
      LAYER M4 ;
        RECT  172.758 32.256 172.842 32.28 ;
    END
  END i_pkt[555]
  PIN i_pkt[556]
    DIRECTION INPUT ;
    USE SIGNAL ;
    PORT
      LAYER M4 ;
        RECT  172.758 32.352 172.842 32.376 ;
    END
  END i_pkt[556]
  PIN i_pkt[557]
    DIRECTION INPUT ;
    USE SIGNAL ;
    PORT
      LAYER M4 ;
        RECT  172.758 32.448 172.842 32.472 ;
    END
  END i_pkt[557]
  PIN i_pkt[55]
    DIRECTION INPUT ;
    USE SIGNAL ;
    PORT
      LAYER M4 ;
        RECT  172.758 101.28 172.842 101.304 ;
    END
  END i_pkt[55]
  PIN i_pkt[56]
    DIRECTION INPUT ;
    USE SIGNAL ;
    PORT
      LAYER M4 ;
        RECT  172.758 101.376 172.842 101.4 ;
    END
  END i_pkt[56]
  PIN i_pkt[57]
    DIRECTION INPUT ;
    USE SIGNAL ;
    PORT
      LAYER M4 ;
        RECT  172.758 101.472 172.842 101.496 ;
    END
  END i_pkt[57]
  PIN i_pkt[58]
    DIRECTION INPUT ;
    USE SIGNAL ;
    PORT
      LAYER M4 ;
        RECT  172.758 101.568 172.842 101.592 ;
    END
  END i_pkt[58]
  PIN i_pkt[59]
    DIRECTION INPUT ;
    USE SIGNAL ;
    PORT
      LAYER M4 ;
        RECT  172.758 101.664 172.842 101.688 ;
    END
  END i_pkt[59]
  PIN i_pkt[5]
    DIRECTION INPUT ;
    USE SIGNAL ;
    PORT
      LAYER M4 ;
        RECT  172.758 96.48 172.842 96.504 ;
    END
  END i_pkt[5]
  PIN i_pkt[60]
    DIRECTION INPUT ;
    USE SIGNAL ;
    PORT
      LAYER M4 ;
        RECT  172.758 101.76 172.842 101.784 ;
    END
  END i_pkt[60]
  PIN i_pkt[61]
    DIRECTION INPUT ;
    USE SIGNAL ;
    PORT
      LAYER M4 ;
        RECT  172.758 101.856 172.842 101.88 ;
    END
  END i_pkt[61]
  PIN i_pkt[62]
    DIRECTION INPUT ;
    USE SIGNAL ;
    PORT
      LAYER M4 ;
        RECT  172.758 101.952 172.842 101.976 ;
    END
  END i_pkt[62]
  PIN i_pkt[63]
    DIRECTION INPUT ;
    USE SIGNAL ;
    PORT
      LAYER M4 ;
        RECT  172.758 102.048 172.842 102.072 ;
    END
  END i_pkt[63]
  PIN i_pkt[64]
    DIRECTION INPUT ;
    USE SIGNAL ;
    PORT
      LAYER M4 ;
        RECT  172.758 102.144 172.842 102.168 ;
    END
  END i_pkt[64]
  PIN i_pkt[65]
    DIRECTION INPUT ;
    USE SIGNAL ;
    PORT
      LAYER M4 ;
        RECT  172.758 102.24 172.842 102.264 ;
    END
  END i_pkt[65]
  PIN i_pkt[66]
    DIRECTION INPUT ;
    USE SIGNAL ;
    PORT
      LAYER M4 ;
        RECT  172.758 102.336 172.842 102.36 ;
    END
  END i_pkt[66]
  PIN i_pkt[67]
    DIRECTION INPUT ;
    USE SIGNAL ;
    PORT
      LAYER M4 ;
        RECT  172.758 102.432 172.842 102.456 ;
    END
  END i_pkt[67]
  PIN i_pkt[68]
    DIRECTION INPUT ;
    USE SIGNAL ;
    PORT
      LAYER M4 ;
        RECT  172.758 102.528 172.842 102.552 ;
    END
  END i_pkt[68]
  PIN i_pkt[69]
    DIRECTION INPUT ;
    USE SIGNAL ;
    PORT
      LAYER M4 ;
        RECT  172.758 102.624 172.842 102.648 ;
    END
  END i_pkt[69]
  PIN i_pkt[6]
    DIRECTION INPUT ;
    USE SIGNAL ;
    PORT
      LAYER M4 ;
        RECT  172.758 96.576 172.842 96.6 ;
    END
  END i_pkt[6]
  PIN i_pkt[70]
    DIRECTION INPUT ;
    USE SIGNAL ;
    PORT
      LAYER M4 ;
        RECT  172.758 102.72 172.842 102.744 ;
    END
  END i_pkt[70]
  PIN i_pkt[71]
    DIRECTION INPUT ;
    USE SIGNAL ;
    PORT
      LAYER M4 ;
        RECT  172.758 102.816 172.842 102.84 ;
    END
  END i_pkt[71]
  PIN i_pkt[72]
    DIRECTION INPUT ;
    USE SIGNAL ;
    PORT
      LAYER M4 ;
        RECT  172.758 102.912 172.842 102.936 ;
    END
  END i_pkt[72]
  PIN i_pkt[73]
    DIRECTION INPUT ;
    USE SIGNAL ;
    PORT
      LAYER M4 ;
        RECT  172.758 103.008 172.842 103.032 ;
    END
  END i_pkt[73]
  PIN i_pkt[74]
    DIRECTION INPUT ;
    USE SIGNAL ;
    PORT
      LAYER M4 ;
        RECT  172.758 103.104 172.842 103.128 ;
    END
  END i_pkt[74]
  PIN i_pkt[75]
    DIRECTION INPUT ;
    USE SIGNAL ;
    PORT
      LAYER M4 ;
        RECT  172.758 103.2 172.842 103.224 ;
    END
  END i_pkt[75]
  PIN i_pkt[76]
    DIRECTION INPUT ;
    USE SIGNAL ;
    PORT
      LAYER M4 ;
        RECT  172.758 103.296 172.842 103.32 ;
    END
  END i_pkt[76]
  PIN i_pkt[77]
    DIRECTION INPUT ;
    USE SIGNAL ;
    PORT
      LAYER M4 ;
        RECT  172.758 103.392 172.842 103.416 ;
    END
  END i_pkt[77]
  PIN i_pkt[78]
    DIRECTION INPUT ;
    USE SIGNAL ;
    PORT
      LAYER M4 ;
        RECT  172.758 103.488 172.842 103.512 ;
    END
  END i_pkt[78]
  PIN i_pkt[79]
    DIRECTION INPUT ;
    USE SIGNAL ;
    PORT
      LAYER M4 ;
        RECT  172.758 103.584 172.842 103.608 ;
    END
  END i_pkt[79]
  PIN i_pkt[7]
    DIRECTION INPUT ;
    USE SIGNAL ;
    PORT
      LAYER M4 ;
        RECT  172.758 96.672 172.842 96.696 ;
    END
  END i_pkt[7]
  PIN i_pkt[80]
    DIRECTION INPUT ;
    USE SIGNAL ;
    PORT
      LAYER M4 ;
        RECT  172.758 103.68 172.842 103.704 ;
    END
  END i_pkt[80]
  PIN i_pkt[81]
    DIRECTION INPUT ;
    USE SIGNAL ;
    PORT
      LAYER M4 ;
        RECT  172.758 103.776 172.842 103.8 ;
    END
  END i_pkt[81]
  PIN i_pkt[82]
    DIRECTION INPUT ;
    USE SIGNAL ;
    PORT
      LAYER M4 ;
        RECT  172.758 103.872 172.842 103.896 ;
    END
  END i_pkt[82]
  PIN i_pkt[83]
    DIRECTION INPUT ;
    USE SIGNAL ;
    PORT
      LAYER M4 ;
        RECT  172.758 103.968 172.842 103.992 ;
    END
  END i_pkt[83]
  PIN i_pkt[84]
    DIRECTION INPUT ;
    USE SIGNAL ;
    PORT
      LAYER M4 ;
        RECT  172.758 104.064 172.842 104.088 ;
    END
  END i_pkt[84]
  PIN i_pkt[85]
    DIRECTION INPUT ;
    USE SIGNAL ;
    PORT
      LAYER M4 ;
        RECT  172.758 104.16 172.842 104.184 ;
    END
  END i_pkt[85]
  PIN i_pkt[86]
    DIRECTION INPUT ;
    USE SIGNAL ;
    PORT
      LAYER M4 ;
        RECT  172.758 104.256 172.842 104.28 ;
    END
  END i_pkt[86]
  PIN i_pkt[87]
    DIRECTION INPUT ;
    USE SIGNAL ;
    PORT
      LAYER M4 ;
        RECT  172.758 104.352 172.842 104.376 ;
    END
  END i_pkt[87]
  PIN i_pkt[88]
    DIRECTION INPUT ;
    USE SIGNAL ;
    PORT
      LAYER M4 ;
        RECT  172.758 104.448 172.842 104.472 ;
    END
  END i_pkt[88]
  PIN i_pkt[89]
    DIRECTION INPUT ;
    USE SIGNAL ;
    PORT
      LAYER M4 ;
        RECT  172.758 104.544 172.842 104.568 ;
    END
  END i_pkt[89]
  PIN i_pkt[8]
    DIRECTION INPUT ;
    USE SIGNAL ;
    PORT
      LAYER M4 ;
        RECT  172.758 96.768 172.842 96.792 ;
    END
  END i_pkt[8]
  PIN i_pkt[90]
    DIRECTION INPUT ;
    USE SIGNAL ;
    PORT
      LAYER M4 ;
        RECT  172.758 104.64 172.842 104.664 ;
    END
  END i_pkt[90]
  PIN i_pkt[91]
    DIRECTION INPUT ;
    USE SIGNAL ;
    PORT
      LAYER M4 ;
        RECT  172.758 104.736 172.842 104.76 ;
    END
  END i_pkt[91]
  PIN i_pkt[92]
    DIRECTION INPUT ;
    USE SIGNAL ;
    PORT
      LAYER M4 ;
        RECT  172.758 104.832 172.842 104.856 ;
    END
  END i_pkt[92]
  PIN i_pkt[93]
    DIRECTION INPUT ;
    USE SIGNAL ;
    PORT
      LAYER M4 ;
        RECT  172.758 104.928 172.842 104.952 ;
    END
  END i_pkt[93]
  PIN i_pkt[94]
    DIRECTION INPUT ;
    USE SIGNAL ;
    PORT
      LAYER M4 ;
        RECT  172.758 105.024 172.842 105.048 ;
    END
  END i_pkt[94]
  PIN i_pkt[95]
    DIRECTION INPUT ;
    USE SIGNAL ;
    PORT
      LAYER M4 ;
        RECT  172.758 105.12 172.842 105.144 ;
    END
  END i_pkt[95]
  PIN i_pkt[96]
    DIRECTION INPUT ;
    USE SIGNAL ;
    PORT
      LAYER M4 ;
        RECT  172.758 105.216 172.842 105.24 ;
    END
  END i_pkt[96]
  PIN i_pkt[97]
    DIRECTION INPUT ;
    USE SIGNAL ;
    PORT
      LAYER M4 ;
        RECT  172.758 105.312 172.842 105.336 ;
    END
  END i_pkt[97]
  PIN i_pkt[98]
    DIRECTION INPUT ;
    USE SIGNAL ;
    PORT
      LAYER M4 ;
        RECT  172.758 105.408 172.842 105.432 ;
    END
  END i_pkt[98]
  PIN i_pkt[99]
    DIRECTION INPUT ;
    USE SIGNAL ;
    PORT
      LAYER M4 ;
        RECT  172.758 105.504 172.842 105.528 ;
    END
  END i_pkt[99]
  PIN i_pkt[9]
    DIRECTION INPUT ;
    USE SIGNAL ;
    PORT
      LAYER M4 ;
        RECT  172.758 96.864 172.842 96.888 ;
    END
  END i_pkt[9]
  PIN i_v[0]
    DIRECTION INPUT ;
    USE SIGNAL ;
    PORT
      LAYER M4 ;
        RECT  172.758 126.72 172.842 126.744 ;
    END
  END i_v[0]
  PIN i_v[1]
    DIRECTION INPUT ;
    USE SIGNAL ;
    PORT
      LAYER M4 ;
        RECT  172.758 2.88 172.842 2.904 ;
    END
  END i_v[1]
  PIN n_p[0]
    DIRECTION OUTPUT ;
    USE SIGNAL ;
    PORT
      LAYER M4 ;
        RECT  -0.042 51.408 0.042 51.432 ;
    END
  END n_p[0]
  PIN n_p[100]
    DIRECTION OUTPUT ;
    USE SIGNAL ;
    PORT
      LAYER M4 ;
        RECT  -0.042 61.008 0.042 61.032 ;
    END
  END n_p[100]
  PIN n_p[101]
    DIRECTION OUTPUT ;
    USE SIGNAL ;
    PORT
      LAYER M4 ;
        RECT  -0.042 61.104 0.042 61.128 ;
    END
  END n_p[101]
  PIN n_p[102]
    DIRECTION OUTPUT ;
    USE SIGNAL ;
    PORT
      LAYER M4 ;
        RECT  -0.042 61.2 0.042 61.224 ;
    END
  END n_p[102]
  PIN n_p[103]
    DIRECTION OUTPUT ;
    USE SIGNAL ;
    PORT
      LAYER M4 ;
        RECT  -0.042 61.296 0.042 61.32 ;
    END
  END n_p[103]
  PIN n_p[104]
    DIRECTION OUTPUT ;
    USE SIGNAL ;
    PORT
      LAYER M4 ;
        RECT  -0.042 61.392 0.042 61.416 ;
    END
  END n_p[104]
  PIN n_p[105]
    DIRECTION OUTPUT ;
    USE SIGNAL ;
    PORT
      LAYER M4 ;
        RECT  -0.042 61.488 0.042 61.512 ;
    END
  END n_p[105]
  PIN n_p[106]
    DIRECTION OUTPUT ;
    USE SIGNAL ;
    PORT
      LAYER M4 ;
        RECT  -0.042 61.584 0.042 61.608 ;
    END
  END n_p[106]
  PIN n_p[107]
    DIRECTION OUTPUT ;
    USE SIGNAL ;
    PORT
      LAYER M4 ;
        RECT  -0.042 61.68 0.042 61.704 ;
    END
  END n_p[107]
  PIN n_p[108]
    DIRECTION OUTPUT ;
    USE SIGNAL ;
    PORT
      LAYER M4 ;
        RECT  -0.042 61.776 0.042 61.8 ;
    END
  END n_p[108]
  PIN n_p[109]
    DIRECTION OUTPUT ;
    USE SIGNAL ;
    PORT
      LAYER M4 ;
        RECT  -0.042 61.872 0.042 61.896 ;
    END
  END n_p[109]
  PIN n_p[10]
    DIRECTION OUTPUT ;
    USE SIGNAL ;
    PORT
      LAYER M4 ;
        RECT  -0.042 52.368 0.042 52.392 ;
    END
  END n_p[10]
  PIN n_p[110]
    DIRECTION OUTPUT ;
    USE SIGNAL ;
    PORT
      LAYER M4 ;
        RECT  -0.042 61.968 0.042 61.992 ;
    END
  END n_p[110]
  PIN n_p[111]
    DIRECTION OUTPUT ;
    USE SIGNAL ;
    PORT
      LAYER M4 ;
        RECT  -0.042 62.064 0.042 62.088 ;
    END
  END n_p[111]
  PIN n_p[112]
    DIRECTION OUTPUT ;
    USE SIGNAL ;
    PORT
      LAYER M4 ;
        RECT  -0.042 62.16 0.042 62.184 ;
    END
  END n_p[112]
  PIN n_p[113]
    DIRECTION OUTPUT ;
    USE SIGNAL ;
    PORT
      LAYER M4 ;
        RECT  -0.042 62.256 0.042 62.28 ;
    END
  END n_p[113]
  PIN n_p[114]
    DIRECTION OUTPUT ;
    USE SIGNAL ;
    PORT
      LAYER M4 ;
        RECT  -0.042 62.352 0.042 62.376 ;
    END
  END n_p[114]
  PIN n_p[115]
    DIRECTION OUTPUT ;
    USE SIGNAL ;
    PORT
      LAYER M4 ;
        RECT  -0.042 62.448 0.042 62.472 ;
    END
  END n_p[115]
  PIN n_p[116]
    DIRECTION OUTPUT ;
    USE SIGNAL ;
    PORT
      LAYER M4 ;
        RECT  -0.042 62.544 0.042 62.568 ;
    END
  END n_p[116]
  PIN n_p[117]
    DIRECTION OUTPUT ;
    USE SIGNAL ;
    PORT
      LAYER M4 ;
        RECT  -0.042 62.64 0.042 62.664 ;
    END
  END n_p[117]
  PIN n_p[118]
    DIRECTION OUTPUT ;
    USE SIGNAL ;
    PORT
      LAYER M4 ;
        RECT  -0.042 62.736 0.042 62.76 ;
    END
  END n_p[118]
  PIN n_p[119]
    DIRECTION OUTPUT ;
    USE SIGNAL ;
    PORT
      LAYER M4 ;
        RECT  -0.042 62.832 0.042 62.856 ;
    END
  END n_p[119]
  PIN n_p[11]
    DIRECTION OUTPUT ;
    USE SIGNAL ;
    PORT
      LAYER M4 ;
        RECT  -0.042 52.464 0.042 52.488 ;
    END
  END n_p[11]
  PIN n_p[120]
    DIRECTION OUTPUT ;
    USE SIGNAL ;
    PORT
      LAYER M4 ;
        RECT  -0.042 62.928 0.042 62.952 ;
    END
  END n_p[120]
  PIN n_p[121]
    DIRECTION OUTPUT ;
    USE SIGNAL ;
    PORT
      LAYER M4 ;
        RECT  -0.042 63.024 0.042 63.048 ;
    END
  END n_p[121]
  PIN n_p[122]
    DIRECTION OUTPUT ;
    USE SIGNAL ;
    PORT
      LAYER M4 ;
        RECT  -0.042 63.12 0.042 63.144 ;
    END
  END n_p[122]
  PIN n_p[123]
    DIRECTION OUTPUT ;
    USE SIGNAL ;
    PORT
      LAYER M4 ;
        RECT  -0.042 63.216 0.042 63.24 ;
    END
  END n_p[123]
  PIN n_p[124]
    DIRECTION OUTPUT ;
    USE SIGNAL ;
    PORT
      LAYER M4 ;
        RECT  -0.042 63.312 0.042 63.336 ;
    END
  END n_p[124]
  PIN n_p[125]
    DIRECTION OUTPUT ;
    USE SIGNAL ;
    PORT
      LAYER M4 ;
        RECT  -0.042 63.408 0.042 63.432 ;
    END
  END n_p[125]
  PIN n_p[126]
    DIRECTION OUTPUT ;
    USE SIGNAL ;
    PORT
      LAYER M4 ;
        RECT  -0.042 63.504 0.042 63.528 ;
    END
  END n_p[126]
  PIN n_p[127]
    DIRECTION OUTPUT ;
    USE SIGNAL ;
    PORT
      LAYER M4 ;
        RECT  -0.042 63.6 0.042 63.624 ;
    END
  END n_p[127]
  PIN n_p[128]
    DIRECTION OUTPUT ;
    USE SIGNAL ;
    PORT
      LAYER M4 ;
        RECT  -0.042 63.696 0.042 63.72 ;
    END
  END n_p[128]
  PIN n_p[129]
    DIRECTION OUTPUT ;
    USE SIGNAL ;
    PORT
      LAYER M4 ;
        RECT  -0.042 63.792 0.042 63.816 ;
    END
  END n_p[129]
  PIN n_p[12]
    DIRECTION OUTPUT ;
    USE SIGNAL ;
    PORT
      LAYER M4 ;
        RECT  -0.042 52.56 0.042 52.584 ;
    END
  END n_p[12]
  PIN n_p[130]
    DIRECTION OUTPUT ;
    USE SIGNAL ;
    PORT
      LAYER M4 ;
        RECT  -0.042 63.888 0.042 63.912 ;
    END
  END n_p[130]
  PIN n_p[131]
    DIRECTION OUTPUT ;
    USE SIGNAL ;
    PORT
      LAYER M4 ;
        RECT  -0.042 63.984 0.042 64.008 ;
    END
  END n_p[131]
  PIN n_p[132]
    DIRECTION OUTPUT ;
    USE SIGNAL ;
    PORT
      LAYER M4 ;
        RECT  -0.042 64.08 0.042 64.104 ;
    END
  END n_p[132]
  PIN n_p[133]
    DIRECTION OUTPUT ;
    USE SIGNAL ;
    PORT
      LAYER M4 ;
        RECT  -0.042 64.176 0.042 64.2 ;
    END
  END n_p[133]
  PIN n_p[134]
    DIRECTION OUTPUT ;
    USE SIGNAL ;
    PORT
      LAYER M4 ;
        RECT  -0.042 64.272 0.042 64.296 ;
    END
  END n_p[134]
  PIN n_p[135]
    DIRECTION OUTPUT ;
    USE SIGNAL ;
    PORT
      LAYER M4 ;
        RECT  -0.042 64.368 0.042 64.392 ;
    END
  END n_p[135]
  PIN n_p[136]
    DIRECTION OUTPUT ;
    USE SIGNAL ;
    PORT
      LAYER M4 ;
        RECT  -0.042 64.464 0.042 64.488 ;
    END
  END n_p[136]
  PIN n_p[137]
    DIRECTION OUTPUT ;
    USE SIGNAL ;
    PORT
      LAYER M4 ;
        RECT  -0.042 64.56 0.042 64.584 ;
    END
  END n_p[137]
  PIN n_p[138]
    DIRECTION OUTPUT ;
    USE SIGNAL ;
    PORT
      LAYER M4 ;
        RECT  -0.042 64.656 0.042 64.68 ;
    END
  END n_p[138]
  PIN n_p[139]
    DIRECTION OUTPUT ;
    USE SIGNAL ;
    PORT
      LAYER M4 ;
        RECT  -0.042 64.752 0.042 64.776 ;
    END
  END n_p[139]
  PIN n_p[13]
    DIRECTION OUTPUT ;
    USE SIGNAL ;
    PORT
      LAYER M4 ;
        RECT  -0.042 52.656 0.042 52.68 ;
    END
  END n_p[13]
  PIN n_p[140]
    DIRECTION OUTPUT ;
    USE SIGNAL ;
    PORT
      LAYER M4 ;
        RECT  -0.042 64.848 0.042 64.872 ;
    END
  END n_p[140]
  PIN n_p[141]
    DIRECTION OUTPUT ;
    USE SIGNAL ;
    PORT
      LAYER M4 ;
        RECT  -0.042 64.944 0.042 64.968 ;
    END
  END n_p[141]
  PIN n_p[142]
    DIRECTION OUTPUT ;
    USE SIGNAL ;
    PORT
      LAYER M4 ;
        RECT  -0.042 65.04 0.042 65.064 ;
    END
  END n_p[142]
  PIN n_p[143]
    DIRECTION OUTPUT ;
    USE SIGNAL ;
    PORT
      LAYER M4 ;
        RECT  -0.042 65.136 0.042 65.16 ;
    END
  END n_p[143]
  PIN n_p[144]
    DIRECTION OUTPUT ;
    USE SIGNAL ;
    PORT
      LAYER M4 ;
        RECT  -0.042 65.232 0.042 65.256 ;
    END
  END n_p[144]
  PIN n_p[145]
    DIRECTION OUTPUT ;
    USE SIGNAL ;
    PORT
      LAYER M4 ;
        RECT  -0.042 65.328 0.042 65.352 ;
    END
  END n_p[145]
  PIN n_p[146]
    DIRECTION OUTPUT ;
    USE SIGNAL ;
    PORT
      LAYER M4 ;
        RECT  -0.042 65.424 0.042 65.448 ;
    END
  END n_p[146]
  PIN n_p[147]
    DIRECTION OUTPUT ;
    USE SIGNAL ;
    PORT
      LAYER M4 ;
        RECT  -0.042 65.52 0.042 65.544 ;
    END
  END n_p[147]
  PIN n_p[148]
    DIRECTION OUTPUT ;
    USE SIGNAL ;
    PORT
      LAYER M4 ;
        RECT  -0.042 65.616 0.042 65.64 ;
    END
  END n_p[148]
  PIN n_p[149]
    DIRECTION OUTPUT ;
    USE SIGNAL ;
    PORT
      LAYER M4 ;
        RECT  -0.042 65.712 0.042 65.736 ;
    END
  END n_p[149]
  PIN n_p[14]
    DIRECTION OUTPUT ;
    USE SIGNAL ;
    PORT
      LAYER M4 ;
        RECT  -0.042 52.752 0.042 52.776 ;
    END
  END n_p[14]
  PIN n_p[150]
    DIRECTION OUTPUT ;
    USE SIGNAL ;
    PORT
      LAYER M4 ;
        RECT  -0.042 65.808 0.042 65.832 ;
    END
  END n_p[150]
  PIN n_p[151]
    DIRECTION OUTPUT ;
    USE SIGNAL ;
    PORT
      LAYER M4 ;
        RECT  -0.042 65.904 0.042 65.928 ;
    END
  END n_p[151]
  PIN n_p[152]
    DIRECTION OUTPUT ;
    USE SIGNAL ;
    PORT
      LAYER M4 ;
        RECT  -0.042 66 0.042 66.024 ;
    END
  END n_p[152]
  PIN n_p[153]
    DIRECTION OUTPUT ;
    USE SIGNAL ;
    PORT
      LAYER M4 ;
        RECT  -0.042 66.096 0.042 66.12 ;
    END
  END n_p[153]
  PIN n_p[154]
    DIRECTION OUTPUT ;
    USE SIGNAL ;
    PORT
      LAYER M4 ;
        RECT  -0.042 66.192 0.042 66.216 ;
    END
  END n_p[154]
  PIN n_p[155]
    DIRECTION OUTPUT ;
    USE SIGNAL ;
    PORT
      LAYER M4 ;
        RECT  -0.042 66.288 0.042 66.312 ;
    END
  END n_p[155]
  PIN n_p[156]
    DIRECTION OUTPUT ;
    USE SIGNAL ;
    PORT
      LAYER M4 ;
        RECT  -0.042 66.384 0.042 66.408 ;
    END
  END n_p[156]
  PIN n_p[157]
    DIRECTION OUTPUT ;
    USE SIGNAL ;
    PORT
      LAYER M4 ;
        RECT  -0.042 66.48 0.042 66.504 ;
    END
  END n_p[157]
  PIN n_p[158]
    DIRECTION OUTPUT ;
    USE SIGNAL ;
    PORT
      LAYER M4 ;
        RECT  -0.042 66.576 0.042 66.6 ;
    END
  END n_p[158]
  PIN n_p[159]
    DIRECTION OUTPUT ;
    USE SIGNAL ;
    PORT
      LAYER M4 ;
        RECT  -0.042 66.672 0.042 66.696 ;
    END
  END n_p[159]
  PIN n_p[15]
    DIRECTION OUTPUT ;
    USE SIGNAL ;
    PORT
      LAYER M4 ;
        RECT  -0.042 52.848 0.042 52.872 ;
    END
  END n_p[15]
  PIN n_p[160]
    DIRECTION OUTPUT ;
    USE SIGNAL ;
    PORT
      LAYER M4 ;
        RECT  -0.042 66.768 0.042 66.792 ;
    END
  END n_p[160]
  PIN n_p[161]
    DIRECTION OUTPUT ;
    USE SIGNAL ;
    PORT
      LAYER M4 ;
        RECT  -0.042 66.864 0.042 66.888 ;
    END
  END n_p[161]
  PIN n_p[162]
    DIRECTION OUTPUT ;
    USE SIGNAL ;
    PORT
      LAYER M4 ;
        RECT  -0.042 66.96 0.042 66.984 ;
    END
  END n_p[162]
  PIN n_p[163]
    DIRECTION OUTPUT ;
    USE SIGNAL ;
    PORT
      LAYER M4 ;
        RECT  -0.042 67.056 0.042 67.08 ;
    END
  END n_p[163]
  PIN n_p[164]
    DIRECTION OUTPUT ;
    USE SIGNAL ;
    PORT
      LAYER M4 ;
        RECT  -0.042 67.152 0.042 67.176 ;
    END
  END n_p[164]
  PIN n_p[165]
    DIRECTION OUTPUT ;
    USE SIGNAL ;
    PORT
      LAYER M4 ;
        RECT  -0.042 67.248 0.042 67.272 ;
    END
  END n_p[165]
  PIN n_p[166]
    DIRECTION OUTPUT ;
    USE SIGNAL ;
    PORT
      LAYER M4 ;
        RECT  -0.042 67.344 0.042 67.368 ;
    END
  END n_p[166]
  PIN n_p[167]
    DIRECTION OUTPUT ;
    USE SIGNAL ;
    PORT
      LAYER M4 ;
        RECT  -0.042 67.44 0.042 67.464 ;
    END
  END n_p[167]
  PIN n_p[168]
    DIRECTION OUTPUT ;
    USE SIGNAL ;
    PORT
      LAYER M4 ;
        RECT  -0.042 67.536 0.042 67.56 ;
    END
  END n_p[168]
  PIN n_p[169]
    DIRECTION OUTPUT ;
    USE SIGNAL ;
    PORT
      LAYER M4 ;
        RECT  -0.042 67.632 0.042 67.656 ;
    END
  END n_p[169]
  PIN n_p[16]
    DIRECTION OUTPUT ;
    USE SIGNAL ;
    PORT
      LAYER M4 ;
        RECT  -0.042 52.944 0.042 52.968 ;
    END
  END n_p[16]
  PIN n_p[170]
    DIRECTION OUTPUT ;
    USE SIGNAL ;
    PORT
      LAYER M4 ;
        RECT  -0.042 67.728 0.042 67.752 ;
    END
  END n_p[170]
  PIN n_p[171]
    DIRECTION OUTPUT ;
    USE SIGNAL ;
    PORT
      LAYER M4 ;
        RECT  -0.042 67.824 0.042 67.848 ;
    END
  END n_p[171]
  PIN n_p[172]
    DIRECTION OUTPUT ;
    USE SIGNAL ;
    PORT
      LAYER M4 ;
        RECT  -0.042 67.92 0.042 67.944 ;
    END
  END n_p[172]
  PIN n_p[173]
    DIRECTION OUTPUT ;
    USE SIGNAL ;
    PORT
      LAYER M4 ;
        RECT  -0.042 68.016 0.042 68.04 ;
    END
  END n_p[173]
  PIN n_p[174]
    DIRECTION OUTPUT ;
    USE SIGNAL ;
    PORT
      LAYER M4 ;
        RECT  -0.042 68.112 0.042 68.136 ;
    END
  END n_p[174]
  PIN n_p[175]
    DIRECTION OUTPUT ;
    USE SIGNAL ;
    PORT
      LAYER M4 ;
        RECT  -0.042 68.208 0.042 68.232 ;
    END
  END n_p[175]
  PIN n_p[176]
    DIRECTION OUTPUT ;
    USE SIGNAL ;
    PORT
      LAYER M4 ;
        RECT  -0.042 68.304 0.042 68.328 ;
    END
  END n_p[176]
  PIN n_p[177]
    DIRECTION OUTPUT ;
    USE SIGNAL ;
    PORT
      LAYER M4 ;
        RECT  -0.042 68.4 0.042 68.424 ;
    END
  END n_p[177]
  PIN n_p[178]
    DIRECTION OUTPUT ;
    USE SIGNAL ;
    PORT
      LAYER M4 ;
        RECT  -0.042 68.496 0.042 68.52 ;
    END
  END n_p[178]
  PIN n_p[179]
    DIRECTION OUTPUT ;
    USE SIGNAL ;
    PORT
      LAYER M4 ;
        RECT  -0.042 68.592 0.042 68.616 ;
    END
  END n_p[179]
  PIN n_p[17]
    DIRECTION OUTPUT ;
    USE SIGNAL ;
    PORT
      LAYER M4 ;
        RECT  -0.042 53.04 0.042 53.064 ;
    END
  END n_p[17]
  PIN n_p[180]
    DIRECTION OUTPUT ;
    USE SIGNAL ;
    PORT
      LAYER M4 ;
        RECT  -0.042 68.688 0.042 68.712 ;
    END
  END n_p[180]
  PIN n_p[181]
    DIRECTION OUTPUT ;
    USE SIGNAL ;
    PORT
      LAYER M4 ;
        RECT  -0.042 68.784 0.042 68.808 ;
    END
  END n_p[181]
  PIN n_p[182]
    DIRECTION OUTPUT ;
    USE SIGNAL ;
    PORT
      LAYER M4 ;
        RECT  -0.042 68.88 0.042 68.904 ;
    END
  END n_p[182]
  PIN n_p[183]
    DIRECTION OUTPUT ;
    USE SIGNAL ;
    PORT
      LAYER M4 ;
        RECT  -0.042 68.976 0.042 69 ;
    END
  END n_p[183]
  PIN n_p[184]
    DIRECTION OUTPUT ;
    USE SIGNAL ;
    PORT
      LAYER M4 ;
        RECT  -0.042 69.072 0.042 69.096 ;
    END
  END n_p[184]
  PIN n_p[185]
    DIRECTION OUTPUT ;
    USE SIGNAL ;
    PORT
      LAYER M4 ;
        RECT  -0.042 69.168 0.042 69.192 ;
    END
  END n_p[185]
  PIN n_p[186]
    DIRECTION OUTPUT ;
    USE SIGNAL ;
    PORT
      LAYER M4 ;
        RECT  -0.042 69.264 0.042 69.288 ;
    END
  END n_p[186]
  PIN n_p[187]
    DIRECTION OUTPUT ;
    USE SIGNAL ;
    PORT
      LAYER M4 ;
        RECT  -0.042 69.36 0.042 69.384 ;
    END
  END n_p[187]
  PIN n_p[188]
    DIRECTION OUTPUT ;
    USE SIGNAL ;
    PORT
      LAYER M4 ;
        RECT  -0.042 69.456 0.042 69.48 ;
    END
  END n_p[188]
  PIN n_p[189]
    DIRECTION OUTPUT ;
    USE SIGNAL ;
    PORT
      LAYER M4 ;
        RECT  -0.042 69.552 0.042 69.576 ;
    END
  END n_p[189]
  PIN n_p[18]
    DIRECTION OUTPUT ;
    USE SIGNAL ;
    PORT
      LAYER M4 ;
        RECT  -0.042 53.136 0.042 53.16 ;
    END
  END n_p[18]
  PIN n_p[190]
    DIRECTION OUTPUT ;
    USE SIGNAL ;
    PORT
      LAYER M4 ;
        RECT  -0.042 69.648 0.042 69.672 ;
    END
  END n_p[190]
  PIN n_p[191]
    DIRECTION OUTPUT ;
    USE SIGNAL ;
    PORT
      LAYER M4 ;
        RECT  -0.042 69.744 0.042 69.768 ;
    END
  END n_p[191]
  PIN n_p[192]
    DIRECTION OUTPUT ;
    USE SIGNAL ;
    PORT
      LAYER M4 ;
        RECT  -0.042 69.84 0.042 69.864 ;
    END
  END n_p[192]
  PIN n_p[193]
    DIRECTION OUTPUT ;
    USE SIGNAL ;
    PORT
      LAYER M4 ;
        RECT  -0.042 69.936 0.042 69.96 ;
    END
  END n_p[193]
  PIN n_p[194]
    DIRECTION OUTPUT ;
    USE SIGNAL ;
    PORT
      LAYER M4 ;
        RECT  -0.042 70.032 0.042 70.056 ;
    END
  END n_p[194]
  PIN n_p[195]
    DIRECTION OUTPUT ;
    USE SIGNAL ;
    PORT
      LAYER M4 ;
        RECT  -0.042 70.128 0.042 70.152 ;
    END
  END n_p[195]
  PIN n_p[196]
    DIRECTION OUTPUT ;
    USE SIGNAL ;
    PORT
      LAYER M4 ;
        RECT  -0.042 70.224 0.042 70.248 ;
    END
  END n_p[196]
  PIN n_p[197]
    DIRECTION OUTPUT ;
    USE SIGNAL ;
    PORT
      LAYER M4 ;
        RECT  -0.042 70.32 0.042 70.344 ;
    END
  END n_p[197]
  PIN n_p[198]
    DIRECTION OUTPUT ;
    USE SIGNAL ;
    PORT
      LAYER M4 ;
        RECT  -0.042 70.416 0.042 70.44 ;
    END
  END n_p[198]
  PIN n_p[199]
    DIRECTION OUTPUT ;
    USE SIGNAL ;
    PORT
      LAYER M4 ;
        RECT  -0.042 70.512 0.042 70.536 ;
    END
  END n_p[199]
  PIN n_p[19]
    DIRECTION OUTPUT ;
    USE SIGNAL ;
    PORT
      LAYER M4 ;
        RECT  -0.042 53.232 0.042 53.256 ;
    END
  END n_p[19]
  PIN n_p[1]
    DIRECTION OUTPUT ;
    USE SIGNAL ;
    PORT
      LAYER M4 ;
        RECT  -0.042 51.504 0.042 51.528 ;
    END
  END n_p[1]
  PIN n_p[200]
    DIRECTION OUTPUT ;
    USE SIGNAL ;
    PORT
      LAYER M4 ;
        RECT  -0.042 70.608 0.042 70.632 ;
    END
  END n_p[200]
  PIN n_p[201]
    DIRECTION OUTPUT ;
    USE SIGNAL ;
    PORT
      LAYER M4 ;
        RECT  -0.042 70.704 0.042 70.728 ;
    END
  END n_p[201]
  PIN n_p[202]
    DIRECTION OUTPUT ;
    USE SIGNAL ;
    PORT
      LAYER M4 ;
        RECT  -0.042 70.8 0.042 70.824 ;
    END
  END n_p[202]
  PIN n_p[203]
    DIRECTION OUTPUT ;
    USE SIGNAL ;
    PORT
      LAYER M4 ;
        RECT  -0.042 70.896 0.042 70.92 ;
    END
  END n_p[203]
  PIN n_p[204]
    DIRECTION OUTPUT ;
    USE SIGNAL ;
    PORT
      LAYER M4 ;
        RECT  -0.042 70.992 0.042 71.016 ;
    END
  END n_p[204]
  PIN n_p[205]
    DIRECTION OUTPUT ;
    USE SIGNAL ;
    PORT
      LAYER M4 ;
        RECT  -0.042 71.088 0.042 71.112 ;
    END
  END n_p[205]
  PIN n_p[206]
    DIRECTION OUTPUT ;
    USE SIGNAL ;
    PORT
      LAYER M4 ;
        RECT  -0.042 71.184 0.042 71.208 ;
    END
  END n_p[206]
  PIN n_p[207]
    DIRECTION OUTPUT ;
    USE SIGNAL ;
    PORT
      LAYER M4 ;
        RECT  -0.042 71.28 0.042 71.304 ;
    END
  END n_p[207]
  PIN n_p[208]
    DIRECTION OUTPUT ;
    USE SIGNAL ;
    PORT
      LAYER M4 ;
        RECT  -0.042 71.376 0.042 71.4 ;
    END
  END n_p[208]
  PIN n_p[209]
    DIRECTION OUTPUT ;
    USE SIGNAL ;
    PORT
      LAYER M4 ;
        RECT  -0.042 71.472 0.042 71.496 ;
    END
  END n_p[209]
  PIN n_p[20]
    DIRECTION OUTPUT ;
    USE SIGNAL ;
    PORT
      LAYER M4 ;
        RECT  -0.042 53.328 0.042 53.352 ;
    END
  END n_p[20]
  PIN n_p[210]
    DIRECTION OUTPUT ;
    USE SIGNAL ;
    PORT
      LAYER M4 ;
        RECT  -0.042 71.568 0.042 71.592 ;
    END
  END n_p[210]
  PIN n_p[211]
    DIRECTION OUTPUT ;
    USE SIGNAL ;
    PORT
      LAYER M4 ;
        RECT  -0.042 71.664 0.042 71.688 ;
    END
  END n_p[211]
  PIN n_p[212]
    DIRECTION OUTPUT ;
    USE SIGNAL ;
    PORT
      LAYER M4 ;
        RECT  -0.042 71.76 0.042 71.784 ;
    END
  END n_p[212]
  PIN n_p[213]
    DIRECTION OUTPUT ;
    USE SIGNAL ;
    PORT
      LAYER M4 ;
        RECT  -0.042 71.856 0.042 71.88 ;
    END
  END n_p[213]
  PIN n_p[214]
    DIRECTION OUTPUT ;
    USE SIGNAL ;
    PORT
      LAYER M4 ;
        RECT  -0.042 71.952 0.042 71.976 ;
    END
  END n_p[214]
  PIN n_p[215]
    DIRECTION OUTPUT ;
    USE SIGNAL ;
    PORT
      LAYER M4 ;
        RECT  -0.042 72.048 0.042 72.072 ;
    END
  END n_p[215]
  PIN n_p[216]
    DIRECTION OUTPUT ;
    USE SIGNAL ;
    PORT
      LAYER M4 ;
        RECT  -0.042 72.144 0.042 72.168 ;
    END
  END n_p[216]
  PIN n_p[217]
    DIRECTION OUTPUT ;
    USE SIGNAL ;
    PORT
      LAYER M4 ;
        RECT  -0.042 72.24 0.042 72.264 ;
    END
  END n_p[217]
  PIN n_p[218]
    DIRECTION OUTPUT ;
    USE SIGNAL ;
    PORT
      LAYER M4 ;
        RECT  -0.042 72.336 0.042 72.36 ;
    END
  END n_p[218]
  PIN n_p[219]
    DIRECTION OUTPUT ;
    USE SIGNAL ;
    PORT
      LAYER M4 ;
        RECT  -0.042 72.432 0.042 72.456 ;
    END
  END n_p[219]
  PIN n_p[21]
    DIRECTION OUTPUT ;
    USE SIGNAL ;
    PORT
      LAYER M4 ;
        RECT  -0.042 53.424 0.042 53.448 ;
    END
  END n_p[21]
  PIN n_p[220]
    DIRECTION OUTPUT ;
    USE SIGNAL ;
    PORT
      LAYER M4 ;
        RECT  -0.042 72.528 0.042 72.552 ;
    END
  END n_p[220]
  PIN n_p[221]
    DIRECTION OUTPUT ;
    USE SIGNAL ;
    PORT
      LAYER M4 ;
        RECT  -0.042 72.624 0.042 72.648 ;
    END
  END n_p[221]
  PIN n_p[222]
    DIRECTION OUTPUT ;
    USE SIGNAL ;
    PORT
      LAYER M4 ;
        RECT  -0.042 72.72 0.042 72.744 ;
    END
  END n_p[222]
  PIN n_p[223]
    DIRECTION OUTPUT ;
    USE SIGNAL ;
    PORT
      LAYER M4 ;
        RECT  -0.042 72.816 0.042 72.84 ;
    END
  END n_p[223]
  PIN n_p[224]
    DIRECTION OUTPUT ;
    USE SIGNAL ;
    PORT
      LAYER M4 ;
        RECT  -0.042 72.912 0.042 72.936 ;
    END
  END n_p[224]
  PIN n_p[225]
    DIRECTION OUTPUT ;
    USE SIGNAL ;
    PORT
      LAYER M4 ;
        RECT  -0.042 73.008 0.042 73.032 ;
    END
  END n_p[225]
  PIN n_p[226]
    DIRECTION OUTPUT ;
    USE SIGNAL ;
    PORT
      LAYER M4 ;
        RECT  -0.042 73.104 0.042 73.128 ;
    END
  END n_p[226]
  PIN n_p[227]
    DIRECTION OUTPUT ;
    USE SIGNAL ;
    PORT
      LAYER M4 ;
        RECT  -0.042 73.2 0.042 73.224 ;
    END
  END n_p[227]
  PIN n_p[228]
    DIRECTION OUTPUT ;
    USE SIGNAL ;
    PORT
      LAYER M4 ;
        RECT  -0.042 73.296 0.042 73.32 ;
    END
  END n_p[228]
  PIN n_p[229]
    DIRECTION OUTPUT ;
    USE SIGNAL ;
    PORT
      LAYER M4 ;
        RECT  -0.042 73.392 0.042 73.416 ;
    END
  END n_p[229]
  PIN n_p[22]
    DIRECTION OUTPUT ;
    USE SIGNAL ;
    PORT
      LAYER M4 ;
        RECT  -0.042 53.52 0.042 53.544 ;
    END
  END n_p[22]
  PIN n_p[230]
    DIRECTION OUTPUT ;
    USE SIGNAL ;
    PORT
      LAYER M4 ;
        RECT  -0.042 73.488 0.042 73.512 ;
    END
  END n_p[230]
  PIN n_p[231]
    DIRECTION OUTPUT ;
    USE SIGNAL ;
    PORT
      LAYER M4 ;
        RECT  -0.042 73.584 0.042 73.608 ;
    END
  END n_p[231]
  PIN n_p[232]
    DIRECTION OUTPUT ;
    USE SIGNAL ;
    PORT
      LAYER M4 ;
        RECT  -0.042 73.68 0.042 73.704 ;
    END
  END n_p[232]
  PIN n_p[233]
    DIRECTION OUTPUT ;
    USE SIGNAL ;
    PORT
      LAYER M4 ;
        RECT  -0.042 73.776 0.042 73.8 ;
    END
  END n_p[233]
  PIN n_p[234]
    DIRECTION OUTPUT ;
    USE SIGNAL ;
    PORT
      LAYER M4 ;
        RECT  -0.042 73.872 0.042 73.896 ;
    END
  END n_p[234]
  PIN n_p[235]
    DIRECTION OUTPUT ;
    USE SIGNAL ;
    PORT
      LAYER M4 ;
        RECT  -0.042 73.968 0.042 73.992 ;
    END
  END n_p[235]
  PIN n_p[236]
    DIRECTION OUTPUT ;
    USE SIGNAL ;
    PORT
      LAYER M4 ;
        RECT  -0.042 74.064 0.042 74.088 ;
    END
  END n_p[236]
  PIN n_p[237]
    DIRECTION OUTPUT ;
    USE SIGNAL ;
    PORT
      LAYER M4 ;
        RECT  -0.042 74.16 0.042 74.184 ;
    END
  END n_p[237]
  PIN n_p[238]
    DIRECTION OUTPUT ;
    USE SIGNAL ;
    PORT
      LAYER M4 ;
        RECT  -0.042 74.256 0.042 74.28 ;
    END
  END n_p[238]
  PIN n_p[239]
    DIRECTION OUTPUT ;
    USE SIGNAL ;
    PORT
      LAYER M4 ;
        RECT  -0.042 74.352 0.042 74.376 ;
    END
  END n_p[239]
  PIN n_p[23]
    DIRECTION OUTPUT ;
    USE SIGNAL ;
    PORT
      LAYER M4 ;
        RECT  -0.042 53.616 0.042 53.64 ;
    END
  END n_p[23]
  PIN n_p[240]
    DIRECTION OUTPUT ;
    USE SIGNAL ;
    PORT
      LAYER M4 ;
        RECT  -0.042 74.448 0.042 74.472 ;
    END
  END n_p[240]
  PIN n_p[241]
    DIRECTION OUTPUT ;
    USE SIGNAL ;
    PORT
      LAYER M4 ;
        RECT  -0.042 74.544 0.042 74.568 ;
    END
  END n_p[241]
  PIN n_p[242]
    DIRECTION OUTPUT ;
    USE SIGNAL ;
    PORT
      LAYER M4 ;
        RECT  -0.042 74.64 0.042 74.664 ;
    END
  END n_p[242]
  PIN n_p[243]
    DIRECTION OUTPUT ;
    USE SIGNAL ;
    PORT
      LAYER M4 ;
        RECT  -0.042 74.736 0.042 74.76 ;
    END
  END n_p[243]
  PIN n_p[244]
    DIRECTION OUTPUT ;
    USE SIGNAL ;
    PORT
      LAYER M4 ;
        RECT  -0.042 74.832 0.042 74.856 ;
    END
  END n_p[244]
  PIN n_p[245]
    DIRECTION OUTPUT ;
    USE SIGNAL ;
    PORT
      LAYER M4 ;
        RECT  -0.042 74.928 0.042 74.952 ;
    END
  END n_p[245]
  PIN n_p[246]
    DIRECTION OUTPUT ;
    USE SIGNAL ;
    PORT
      LAYER M4 ;
        RECT  -0.042 75.024 0.042 75.048 ;
    END
  END n_p[246]
  PIN n_p[247]
    DIRECTION OUTPUT ;
    USE SIGNAL ;
    PORT
      LAYER M4 ;
        RECT  -0.042 75.12 0.042 75.144 ;
    END
  END n_p[247]
  PIN n_p[248]
    DIRECTION OUTPUT ;
    USE SIGNAL ;
    PORT
      LAYER M4 ;
        RECT  -0.042 75.216 0.042 75.24 ;
    END
  END n_p[248]
  PIN n_p[249]
    DIRECTION OUTPUT ;
    USE SIGNAL ;
    PORT
      LAYER M4 ;
        RECT  -0.042 75.312 0.042 75.336 ;
    END
  END n_p[249]
  PIN n_p[24]
    DIRECTION OUTPUT ;
    USE SIGNAL ;
    PORT
      LAYER M4 ;
        RECT  -0.042 53.712 0.042 53.736 ;
    END
  END n_p[24]
  PIN n_p[250]
    DIRECTION OUTPUT ;
    USE SIGNAL ;
    PORT
      LAYER M4 ;
        RECT  -0.042 75.408 0.042 75.432 ;
    END
  END n_p[250]
  PIN n_p[251]
    DIRECTION OUTPUT ;
    USE SIGNAL ;
    PORT
      LAYER M4 ;
        RECT  -0.042 75.504 0.042 75.528 ;
    END
  END n_p[251]
  PIN n_p[252]
    DIRECTION OUTPUT ;
    USE SIGNAL ;
    PORT
      LAYER M4 ;
        RECT  -0.042 75.6 0.042 75.624 ;
    END
  END n_p[252]
  PIN n_p[253]
    DIRECTION OUTPUT ;
    USE SIGNAL ;
    PORT
      LAYER M4 ;
        RECT  -0.042 75.696 0.042 75.72 ;
    END
  END n_p[253]
  PIN n_p[254]
    DIRECTION OUTPUT ;
    USE SIGNAL ;
    PORT
      LAYER M4 ;
        RECT  -0.042 75.792 0.042 75.816 ;
    END
  END n_p[254]
  PIN n_p[255]
    DIRECTION OUTPUT ;
    USE SIGNAL ;
    PORT
      LAYER M4 ;
        RECT  -0.042 75.888 0.042 75.912 ;
    END
  END n_p[255]
  PIN n_p[256]
    DIRECTION OUTPUT ;
    USE SIGNAL ;
    PORT
      LAYER M4 ;
        RECT  -0.042 75.984 0.042 76.008 ;
    END
  END n_p[256]
  PIN n_p[257]
    DIRECTION OUTPUT ;
    USE SIGNAL ;
    PORT
      LAYER M4 ;
        RECT  -0.042 76.08 0.042 76.104 ;
    END
  END n_p[257]
  PIN n_p[258]
    DIRECTION OUTPUT ;
    USE SIGNAL ;
    PORT
      LAYER M4 ;
        RECT  -0.042 76.176 0.042 76.2 ;
    END
  END n_p[258]
  PIN n_p[259]
    DIRECTION OUTPUT ;
    USE SIGNAL ;
    PORT
      LAYER M4 ;
        RECT  -0.042 76.272 0.042 76.296 ;
    END
  END n_p[259]
  PIN n_p[25]
    DIRECTION OUTPUT ;
    USE SIGNAL ;
    PORT
      LAYER M4 ;
        RECT  -0.042 53.808 0.042 53.832 ;
    END
  END n_p[25]
  PIN n_p[260]
    DIRECTION OUTPUT ;
    USE SIGNAL ;
    PORT
      LAYER M4 ;
        RECT  -0.042 76.368 0.042 76.392 ;
    END
  END n_p[260]
  PIN n_p[261]
    DIRECTION OUTPUT ;
    USE SIGNAL ;
    PORT
      LAYER M4 ;
        RECT  -0.042 76.464 0.042 76.488 ;
    END
  END n_p[261]
  PIN n_p[262]
    DIRECTION OUTPUT ;
    USE SIGNAL ;
    PORT
      LAYER M4 ;
        RECT  -0.042 76.56 0.042 76.584 ;
    END
  END n_p[262]
  PIN n_p[263]
    DIRECTION OUTPUT ;
    USE SIGNAL ;
    PORT
      LAYER M4 ;
        RECT  -0.042 76.656 0.042 76.68 ;
    END
  END n_p[263]
  PIN n_p[264]
    DIRECTION OUTPUT ;
    USE SIGNAL ;
    PORT
      LAYER M4 ;
        RECT  -0.042 76.752 0.042 76.776 ;
    END
  END n_p[264]
  PIN n_p[265]
    DIRECTION OUTPUT ;
    USE SIGNAL ;
    PORT
      LAYER M4 ;
        RECT  -0.042 76.848 0.042 76.872 ;
    END
  END n_p[265]
  PIN n_p[266]
    DIRECTION OUTPUT ;
    USE SIGNAL ;
    PORT
      LAYER M4 ;
        RECT  -0.042 76.944 0.042 76.968 ;
    END
  END n_p[266]
  PIN n_p[267]
    DIRECTION OUTPUT ;
    USE SIGNAL ;
    PORT
      LAYER M4 ;
        RECT  -0.042 77.04 0.042 77.064 ;
    END
  END n_p[267]
  PIN n_p[268]
    DIRECTION OUTPUT ;
    USE SIGNAL ;
    PORT
      LAYER M4 ;
        RECT  -0.042 77.136 0.042 77.16 ;
    END
  END n_p[268]
  PIN n_p[269]
    DIRECTION OUTPUT ;
    USE SIGNAL ;
    PORT
      LAYER M4 ;
        RECT  -0.042 77.232 0.042 77.256 ;
    END
  END n_p[269]
  PIN n_p[26]
    DIRECTION OUTPUT ;
    USE SIGNAL ;
    PORT
      LAYER M4 ;
        RECT  -0.042 53.904 0.042 53.928 ;
    END
  END n_p[26]
  PIN n_p[270]
    DIRECTION OUTPUT ;
    USE SIGNAL ;
    PORT
      LAYER M4 ;
        RECT  -0.042 77.328 0.042 77.352 ;
    END
  END n_p[270]
  PIN n_p[271]
    DIRECTION OUTPUT ;
    USE SIGNAL ;
    PORT
      LAYER M4 ;
        RECT  -0.042 77.424 0.042 77.448 ;
    END
  END n_p[271]
  PIN n_p[272]
    DIRECTION OUTPUT ;
    USE SIGNAL ;
    PORT
      LAYER M4 ;
        RECT  -0.042 77.52 0.042 77.544 ;
    END
  END n_p[272]
  PIN n_p[273]
    DIRECTION OUTPUT ;
    USE SIGNAL ;
    PORT
      LAYER M4 ;
        RECT  -0.042 77.616 0.042 77.64 ;
    END
  END n_p[273]
  PIN n_p[274]
    DIRECTION OUTPUT ;
    USE SIGNAL ;
    PORT
      LAYER M4 ;
        RECT  -0.042 77.712 0.042 77.736 ;
    END
  END n_p[274]
  PIN n_p[275]
    DIRECTION OUTPUT ;
    USE SIGNAL ;
    PORT
      LAYER M4 ;
        RECT  -0.042 77.808 0.042 77.832 ;
    END
  END n_p[275]
  PIN n_p[276]
    DIRECTION OUTPUT ;
    USE SIGNAL ;
    PORT
      LAYER M4 ;
        RECT  -0.042 77.904 0.042 77.928 ;
    END
  END n_p[276]
  PIN n_p[277]
    DIRECTION OUTPUT ;
    USE SIGNAL ;
    PORT
      LAYER M4 ;
        RECT  -0.042 78 0.042 78.024 ;
    END
  END n_p[277]
  PIN n_p[278]
    DIRECTION OUTPUT ;
    USE SIGNAL ;
    PORT
      LAYER M4 ;
        RECT  -0.042 78.096 0.042 78.12 ;
    END
  END n_p[278]
  PIN n_p[27]
    DIRECTION OUTPUT ;
    USE SIGNAL ;
    PORT
      LAYER M4 ;
        RECT  -0.042 54 0.042 54.024 ;
    END
  END n_p[27]
  PIN n_p[28]
    DIRECTION OUTPUT ;
    USE SIGNAL ;
    PORT
      LAYER M4 ;
        RECT  -0.042 54.096 0.042 54.12 ;
    END
  END n_p[28]
  PIN n_p[29]
    DIRECTION OUTPUT ;
    USE SIGNAL ;
    PORT
      LAYER M4 ;
        RECT  -0.042 54.192 0.042 54.216 ;
    END
  END n_p[29]
  PIN n_p[2]
    DIRECTION OUTPUT ;
    USE SIGNAL ;
    PORT
      LAYER M4 ;
        RECT  -0.042 51.6 0.042 51.624 ;
    END
  END n_p[2]
  PIN n_p[30]
    DIRECTION OUTPUT ;
    USE SIGNAL ;
    PORT
      LAYER M4 ;
        RECT  -0.042 54.288 0.042 54.312 ;
    END
  END n_p[30]
  PIN n_p[31]
    DIRECTION OUTPUT ;
    USE SIGNAL ;
    PORT
      LAYER M4 ;
        RECT  -0.042 54.384 0.042 54.408 ;
    END
  END n_p[31]
  PIN n_p[32]
    DIRECTION OUTPUT ;
    USE SIGNAL ;
    PORT
      LAYER M4 ;
        RECT  -0.042 54.48 0.042 54.504 ;
    END
  END n_p[32]
  PIN n_p[33]
    DIRECTION OUTPUT ;
    USE SIGNAL ;
    PORT
      LAYER M4 ;
        RECT  -0.042 54.576 0.042 54.6 ;
    END
  END n_p[33]
  PIN n_p[34]
    DIRECTION OUTPUT ;
    USE SIGNAL ;
    PORT
      LAYER M4 ;
        RECT  -0.042 54.672 0.042 54.696 ;
    END
  END n_p[34]
  PIN n_p[35]
    DIRECTION OUTPUT ;
    USE SIGNAL ;
    PORT
      LAYER M4 ;
        RECT  -0.042 54.768 0.042 54.792 ;
    END
  END n_p[35]
  PIN n_p[36]
    DIRECTION OUTPUT ;
    USE SIGNAL ;
    PORT
      LAYER M4 ;
        RECT  -0.042 54.864 0.042 54.888 ;
    END
  END n_p[36]
  PIN n_p[37]
    DIRECTION OUTPUT ;
    USE SIGNAL ;
    PORT
      LAYER M4 ;
        RECT  -0.042 54.96 0.042 54.984 ;
    END
  END n_p[37]
  PIN n_p[38]
    DIRECTION OUTPUT ;
    USE SIGNAL ;
    PORT
      LAYER M4 ;
        RECT  -0.042 55.056 0.042 55.08 ;
    END
  END n_p[38]
  PIN n_p[39]
    DIRECTION OUTPUT ;
    USE SIGNAL ;
    PORT
      LAYER M4 ;
        RECT  -0.042 55.152 0.042 55.176 ;
    END
  END n_p[39]
  PIN n_p[3]
    DIRECTION OUTPUT ;
    USE SIGNAL ;
    PORT
      LAYER M4 ;
        RECT  -0.042 51.696 0.042 51.72 ;
    END
  END n_p[3]
  PIN n_p[40]
    DIRECTION OUTPUT ;
    USE SIGNAL ;
    PORT
      LAYER M4 ;
        RECT  -0.042 55.248 0.042 55.272 ;
    END
  END n_p[40]
  PIN n_p[41]
    DIRECTION OUTPUT ;
    USE SIGNAL ;
    PORT
      LAYER M4 ;
        RECT  -0.042 55.344 0.042 55.368 ;
    END
  END n_p[41]
  PIN n_p[42]
    DIRECTION OUTPUT ;
    USE SIGNAL ;
    PORT
      LAYER M4 ;
        RECT  -0.042 55.44 0.042 55.464 ;
    END
  END n_p[42]
  PIN n_p[43]
    DIRECTION OUTPUT ;
    USE SIGNAL ;
    PORT
      LAYER M4 ;
        RECT  -0.042 55.536 0.042 55.56 ;
    END
  END n_p[43]
  PIN n_p[44]
    DIRECTION OUTPUT ;
    USE SIGNAL ;
    PORT
      LAYER M4 ;
        RECT  -0.042 55.632 0.042 55.656 ;
    END
  END n_p[44]
  PIN n_p[45]
    DIRECTION OUTPUT ;
    USE SIGNAL ;
    PORT
      LAYER M4 ;
        RECT  -0.042 55.728 0.042 55.752 ;
    END
  END n_p[45]
  PIN n_p[46]
    DIRECTION OUTPUT ;
    USE SIGNAL ;
    PORT
      LAYER M4 ;
        RECT  -0.042 55.824 0.042 55.848 ;
    END
  END n_p[46]
  PIN n_p[47]
    DIRECTION OUTPUT ;
    USE SIGNAL ;
    PORT
      LAYER M4 ;
        RECT  -0.042 55.92 0.042 55.944 ;
    END
  END n_p[47]
  PIN n_p[48]
    DIRECTION OUTPUT ;
    USE SIGNAL ;
    PORT
      LAYER M4 ;
        RECT  -0.042 56.016 0.042 56.04 ;
    END
  END n_p[48]
  PIN n_p[49]
    DIRECTION OUTPUT ;
    USE SIGNAL ;
    PORT
      LAYER M4 ;
        RECT  -0.042 56.112 0.042 56.136 ;
    END
  END n_p[49]
  PIN n_p[4]
    DIRECTION OUTPUT ;
    USE SIGNAL ;
    PORT
      LAYER M4 ;
        RECT  -0.042 51.792 0.042 51.816 ;
    END
  END n_p[4]
  PIN n_p[50]
    DIRECTION OUTPUT ;
    USE SIGNAL ;
    PORT
      LAYER M4 ;
        RECT  -0.042 56.208 0.042 56.232 ;
    END
  END n_p[50]
  PIN n_p[51]
    DIRECTION OUTPUT ;
    USE SIGNAL ;
    PORT
      LAYER M4 ;
        RECT  -0.042 56.304 0.042 56.328 ;
    END
  END n_p[51]
  PIN n_p[52]
    DIRECTION OUTPUT ;
    USE SIGNAL ;
    PORT
      LAYER M4 ;
        RECT  -0.042 56.4 0.042 56.424 ;
    END
  END n_p[52]
  PIN n_p[53]
    DIRECTION OUTPUT ;
    USE SIGNAL ;
    PORT
      LAYER M4 ;
        RECT  -0.042 56.496 0.042 56.52 ;
    END
  END n_p[53]
  PIN n_p[54]
    DIRECTION OUTPUT ;
    USE SIGNAL ;
    PORT
      LAYER M4 ;
        RECT  -0.042 56.592 0.042 56.616 ;
    END
  END n_p[54]
  PIN n_p[55]
    DIRECTION OUTPUT ;
    USE SIGNAL ;
    PORT
      LAYER M4 ;
        RECT  -0.042 56.688 0.042 56.712 ;
    END
  END n_p[55]
  PIN n_p[56]
    DIRECTION OUTPUT ;
    USE SIGNAL ;
    PORT
      LAYER M4 ;
        RECT  -0.042 56.784 0.042 56.808 ;
    END
  END n_p[56]
  PIN n_p[57]
    DIRECTION OUTPUT ;
    USE SIGNAL ;
    PORT
      LAYER M4 ;
        RECT  -0.042 56.88 0.042 56.904 ;
    END
  END n_p[57]
  PIN n_p[58]
    DIRECTION OUTPUT ;
    USE SIGNAL ;
    PORT
      LAYER M4 ;
        RECT  -0.042 56.976 0.042 57 ;
    END
  END n_p[58]
  PIN n_p[59]
    DIRECTION OUTPUT ;
    USE SIGNAL ;
    PORT
      LAYER M4 ;
        RECT  -0.042 57.072 0.042 57.096 ;
    END
  END n_p[59]
  PIN n_p[5]
    DIRECTION OUTPUT ;
    USE SIGNAL ;
    PORT
      LAYER M4 ;
        RECT  -0.042 51.888 0.042 51.912 ;
    END
  END n_p[5]
  PIN n_p[60]
    DIRECTION OUTPUT ;
    USE SIGNAL ;
    PORT
      LAYER M4 ;
        RECT  -0.042 57.168 0.042 57.192 ;
    END
  END n_p[60]
  PIN n_p[61]
    DIRECTION OUTPUT ;
    USE SIGNAL ;
    PORT
      LAYER M4 ;
        RECT  -0.042 57.264 0.042 57.288 ;
    END
  END n_p[61]
  PIN n_p[62]
    DIRECTION OUTPUT ;
    USE SIGNAL ;
    PORT
      LAYER M4 ;
        RECT  -0.042 57.36 0.042 57.384 ;
    END
  END n_p[62]
  PIN n_p[63]
    DIRECTION OUTPUT ;
    USE SIGNAL ;
    PORT
      LAYER M4 ;
        RECT  -0.042 57.456 0.042 57.48 ;
    END
  END n_p[63]
  PIN n_p[64]
    DIRECTION OUTPUT ;
    USE SIGNAL ;
    PORT
      LAYER M4 ;
        RECT  -0.042 57.552 0.042 57.576 ;
    END
  END n_p[64]
  PIN n_p[65]
    DIRECTION OUTPUT ;
    USE SIGNAL ;
    PORT
      LAYER M4 ;
        RECT  -0.042 57.648 0.042 57.672 ;
    END
  END n_p[65]
  PIN n_p[66]
    DIRECTION OUTPUT ;
    USE SIGNAL ;
    PORT
      LAYER M4 ;
        RECT  -0.042 57.744 0.042 57.768 ;
    END
  END n_p[66]
  PIN n_p[67]
    DIRECTION OUTPUT ;
    USE SIGNAL ;
    PORT
      LAYER M4 ;
        RECT  -0.042 57.84 0.042 57.864 ;
    END
  END n_p[67]
  PIN n_p[68]
    DIRECTION OUTPUT ;
    USE SIGNAL ;
    PORT
      LAYER M4 ;
        RECT  -0.042 57.936 0.042 57.96 ;
    END
  END n_p[68]
  PIN n_p[69]
    DIRECTION OUTPUT ;
    USE SIGNAL ;
    PORT
      LAYER M4 ;
        RECT  -0.042 58.032 0.042 58.056 ;
    END
  END n_p[69]
  PIN n_p[6]
    DIRECTION OUTPUT ;
    USE SIGNAL ;
    PORT
      LAYER M4 ;
        RECT  -0.042 51.984 0.042 52.008 ;
    END
  END n_p[6]
  PIN n_p[70]
    DIRECTION OUTPUT ;
    USE SIGNAL ;
    PORT
      LAYER M4 ;
        RECT  -0.042 58.128 0.042 58.152 ;
    END
  END n_p[70]
  PIN n_p[71]
    DIRECTION OUTPUT ;
    USE SIGNAL ;
    PORT
      LAYER M4 ;
        RECT  -0.042 58.224 0.042 58.248 ;
    END
  END n_p[71]
  PIN n_p[72]
    DIRECTION OUTPUT ;
    USE SIGNAL ;
    PORT
      LAYER M4 ;
        RECT  -0.042 58.32 0.042 58.344 ;
    END
  END n_p[72]
  PIN n_p[73]
    DIRECTION OUTPUT ;
    USE SIGNAL ;
    PORT
      LAYER M4 ;
        RECT  -0.042 58.416 0.042 58.44 ;
    END
  END n_p[73]
  PIN n_p[74]
    DIRECTION OUTPUT ;
    USE SIGNAL ;
    PORT
      LAYER M4 ;
        RECT  -0.042 58.512 0.042 58.536 ;
    END
  END n_p[74]
  PIN n_p[75]
    DIRECTION OUTPUT ;
    USE SIGNAL ;
    PORT
      LAYER M4 ;
        RECT  -0.042 58.608 0.042 58.632 ;
    END
  END n_p[75]
  PIN n_p[76]
    DIRECTION OUTPUT ;
    USE SIGNAL ;
    PORT
      LAYER M4 ;
        RECT  -0.042 58.704 0.042 58.728 ;
    END
  END n_p[76]
  PIN n_p[77]
    DIRECTION OUTPUT ;
    USE SIGNAL ;
    PORT
      LAYER M4 ;
        RECT  -0.042 58.8 0.042 58.824 ;
    END
  END n_p[77]
  PIN n_p[78]
    DIRECTION OUTPUT ;
    USE SIGNAL ;
    PORT
      LAYER M4 ;
        RECT  -0.042 58.896 0.042 58.92 ;
    END
  END n_p[78]
  PIN n_p[79]
    DIRECTION OUTPUT ;
    USE SIGNAL ;
    PORT
      LAYER M4 ;
        RECT  -0.042 58.992 0.042 59.016 ;
    END
  END n_p[79]
  PIN n_p[7]
    DIRECTION OUTPUT ;
    USE SIGNAL ;
    PORT
      LAYER M4 ;
        RECT  -0.042 52.08 0.042 52.104 ;
    END
  END n_p[7]
  PIN n_p[80]
    DIRECTION OUTPUT ;
    USE SIGNAL ;
    PORT
      LAYER M4 ;
        RECT  -0.042 59.088 0.042 59.112 ;
    END
  END n_p[80]
  PIN n_p[81]
    DIRECTION OUTPUT ;
    USE SIGNAL ;
    PORT
      LAYER M4 ;
        RECT  -0.042 59.184 0.042 59.208 ;
    END
  END n_p[81]
  PIN n_p[82]
    DIRECTION OUTPUT ;
    USE SIGNAL ;
    PORT
      LAYER M4 ;
        RECT  -0.042 59.28 0.042 59.304 ;
    END
  END n_p[82]
  PIN n_p[83]
    DIRECTION OUTPUT ;
    USE SIGNAL ;
    PORT
      LAYER M4 ;
        RECT  -0.042 59.376 0.042 59.4 ;
    END
  END n_p[83]
  PIN n_p[84]
    DIRECTION OUTPUT ;
    USE SIGNAL ;
    PORT
      LAYER M4 ;
        RECT  -0.042 59.472 0.042 59.496 ;
    END
  END n_p[84]
  PIN n_p[85]
    DIRECTION OUTPUT ;
    USE SIGNAL ;
    PORT
      LAYER M4 ;
        RECT  -0.042 59.568 0.042 59.592 ;
    END
  END n_p[85]
  PIN n_p[86]
    DIRECTION OUTPUT ;
    USE SIGNAL ;
    PORT
      LAYER M4 ;
        RECT  -0.042 59.664 0.042 59.688 ;
    END
  END n_p[86]
  PIN n_p[87]
    DIRECTION OUTPUT ;
    USE SIGNAL ;
    PORT
      LAYER M4 ;
        RECT  -0.042 59.76 0.042 59.784 ;
    END
  END n_p[87]
  PIN n_p[88]
    DIRECTION OUTPUT ;
    USE SIGNAL ;
    PORT
      LAYER M4 ;
        RECT  -0.042 59.856 0.042 59.88 ;
    END
  END n_p[88]
  PIN n_p[89]
    DIRECTION OUTPUT ;
    USE SIGNAL ;
    PORT
      LAYER M4 ;
        RECT  -0.042 59.952 0.042 59.976 ;
    END
  END n_p[89]
  PIN n_p[8]
    DIRECTION OUTPUT ;
    USE SIGNAL ;
    PORT
      LAYER M4 ;
        RECT  -0.042 52.176 0.042 52.2 ;
    END
  END n_p[8]
  PIN n_p[90]
    DIRECTION OUTPUT ;
    USE SIGNAL ;
    PORT
      LAYER M4 ;
        RECT  -0.042 60.048 0.042 60.072 ;
    END
  END n_p[90]
  PIN n_p[91]
    DIRECTION OUTPUT ;
    USE SIGNAL ;
    PORT
      LAYER M4 ;
        RECT  -0.042 60.144 0.042 60.168 ;
    END
  END n_p[91]
  PIN n_p[92]
    DIRECTION OUTPUT ;
    USE SIGNAL ;
    PORT
      LAYER M4 ;
        RECT  -0.042 60.24 0.042 60.264 ;
    END
  END n_p[92]
  PIN n_p[93]
    DIRECTION OUTPUT ;
    USE SIGNAL ;
    PORT
      LAYER M4 ;
        RECT  -0.042 60.336 0.042 60.36 ;
    END
  END n_p[93]
  PIN n_p[94]
    DIRECTION OUTPUT ;
    USE SIGNAL ;
    PORT
      LAYER M4 ;
        RECT  -0.042 60.432 0.042 60.456 ;
    END
  END n_p[94]
  PIN n_p[95]
    DIRECTION OUTPUT ;
    USE SIGNAL ;
    PORT
      LAYER M4 ;
        RECT  -0.042 60.528 0.042 60.552 ;
    END
  END n_p[95]
  PIN n_p[96]
    DIRECTION OUTPUT ;
    USE SIGNAL ;
    PORT
      LAYER M4 ;
        RECT  -0.042 60.624 0.042 60.648 ;
    END
  END n_p[96]
  PIN n_p[97]
    DIRECTION OUTPUT ;
    USE SIGNAL ;
    PORT
      LAYER M4 ;
        RECT  -0.042 60.72 0.042 60.744 ;
    END
  END n_p[97]
  PIN n_p[98]
    DIRECTION OUTPUT ;
    USE SIGNAL ;
    PORT
      LAYER M4 ;
        RECT  -0.042 60.816 0.042 60.84 ;
    END
  END n_p[98]
  PIN n_p[99]
    DIRECTION OUTPUT ;
    USE SIGNAL ;
    PORT
      LAYER M4 ;
        RECT  -0.042 60.912 0.042 60.936 ;
    END
  END n_p[99]
  PIN n_p[9]
    DIRECTION OUTPUT ;
    USE SIGNAL ;
    PORT
      LAYER M4 ;
        RECT  -0.042 52.272 0.042 52.296 ;
    END
  END n_p[9]
  PIN n_v
    DIRECTION OUTPUT ;
    USE SIGNAL ;
    PORT
      LAYER M4 ;
        RECT  -0.042 86.4 0.042 86.424 ;
    END
  END n_v
  PIN rn
    DIRECTION INPUT ;
    USE SIGNAL ;
    PORT
      LAYER M4 ;
        RECT  -0.042 109.44 0.042 109.464 ;
    END
  END rn
  PIN VDD
    DIRECTION INOUT ;
    USE POWER ;
    PORT
      LAYER M5 ;
        RECT  169.992 2.151 170.112 127.449 ;
        RECT  164.592 2.151 164.712 127.449 ;
        RECT  159.192 2.151 159.312 127.449 ;
        RECT  153.792 2.151 153.912 127.449 ;
        RECT  148.392 2.151 148.512 127.449 ;
        RECT  142.992 2.151 143.112 127.449 ;
        RECT  137.592 2.151 137.712 127.449 ;
        RECT  132.192 2.151 132.312 127.449 ;
        RECT  126.792 2.151 126.912 127.449 ;
        RECT  121.392 2.151 121.512 127.449 ;
        RECT  115.992 2.151 116.112 127.449 ;
        RECT  110.592 2.151 110.712 127.449 ;
        RECT  105.192 2.151 105.312 127.449 ;
        RECT  99.792 2.151 99.912 127.449 ;
        RECT  94.392 2.151 94.512 127.449 ;
        RECT  88.992 2.151 89.112 127.449 ;
        RECT  83.592 2.151 83.712 127.449 ;
        RECT  78.192 2.151 78.312 127.449 ;
        RECT  72.792 2.151 72.912 127.449 ;
        RECT  67.392 2.151 67.512 127.449 ;
        RECT  61.992 2.151 62.112 127.449 ;
        RECT  56.592 2.151 56.712 127.449 ;
        RECT  51.192 2.151 51.312 127.449 ;
        RECT  45.792 2.151 45.912 127.449 ;
        RECT  40.392 2.151 40.512 127.449 ;
        RECT  34.992 2.151 35.112 127.449 ;
        RECT  29.592 2.151 29.712 127.449 ;
        RECT  24.192 2.151 24.312 127.449 ;
        RECT  18.792 2.151 18.912 127.449 ;
        RECT  13.392 2.151 13.512 127.449 ;
        RECT  7.992 2.151 8.112 127.449 ;
        RECT  2.592 2.151 2.712 127.449 ;
    END
  END VDD
  PIN VSS
    DIRECTION INOUT ;
    USE GROUND ;
    PORT
      LAYER M5 ;
        RECT  169.8 2.137 169.92 127.463 ;
        RECT  164.4 2.137 164.52 127.463 ;
        RECT  159 2.137 159.12 127.463 ;
        RECT  153.6 2.137 153.72 127.463 ;
        RECT  148.2 2.137 148.32 127.463 ;
        RECT  142.8 2.137 142.92 127.463 ;
        RECT  137.4 2.137 137.52 127.463 ;
        RECT  132 2.137 132.12 127.463 ;
        RECT  126.6 2.137 126.72 127.463 ;
        RECT  121.2 2.137 121.32 127.463 ;
        RECT  115.8 2.137 115.92 127.463 ;
        RECT  110.4 2.137 110.52 127.463 ;
        RECT  105 2.137 105.12 127.463 ;
        RECT  99.6 2.137 99.72 127.463 ;
        RECT  94.2 2.137 94.32 127.463 ;
        RECT  88.8 2.137 88.92 127.463 ;
        RECT  83.4 2.137 83.52 127.463 ;
        RECT  78 2.137 78.12 127.463 ;
        RECT  72.6 2.137 72.72 127.463 ;
        RECT  67.2 2.137 67.32 127.463 ;
        RECT  61.8 2.137 61.92 127.463 ;
        RECT  56.4 2.137 56.52 127.463 ;
        RECT  51 2.137 51.12 127.463 ;
        RECT  45.6 2.137 45.72 127.463 ;
        RECT  40.2 2.137 40.32 127.463 ;
        RECT  34.8 2.137 34.92 127.463 ;
        RECT  29.4 2.137 29.52 127.463 ;
        RECT  24 2.137 24.12 127.463 ;
        RECT  18.6 2.137 18.72 127.463 ;
        RECT  13.2 2.137 13.32 127.463 ;
        RECT  7.8 2.137 7.92 127.463 ;
        RECT  2.4 2.137 2.52 127.463 ;
    END
  END VSS
  OBS
    LAYER RVTN ;
     RECT  2.16 2.16 170.64 2.295 ;
     RECT  2.16 2.565 170.64 2.835 ;
     RECT  2.16 3.105 170.64 3.375 ;
     RECT  2.16 3.645 170.64 3.915 ;
     RECT  2.16 4.185 170.64 4.455 ;
     RECT  2.16 4.725 170.64 4.995 ;
     RECT  2.16 5.265 170.64 5.535 ;
     RECT  2.16 5.805 170.64 6.075 ;
     RECT  2.16 6.345 170.64 6.615 ;
     RECT  2.16 6.885 170.64 7.155 ;
     RECT  2.16 7.425 170.64 7.695 ;
     RECT  2.16 7.965 170.64 8.235 ;
     RECT  2.16 8.505 170.64 8.775 ;
     RECT  2.16 9.045 170.64 9.315 ;
     RECT  2.16 9.585 170.64 9.855 ;
     RECT  2.16 10.125 170.64 10.395 ;
     RECT  2.16 10.665 170.64 10.935 ;
     RECT  2.16 11.205 170.64 11.475 ;
     RECT  2.16 11.745 170.64 12.015 ;
     RECT  2.16 12.285 170.64 12.555 ;
     RECT  2.16 12.825 170.64 13.095 ;
     RECT  2.16 13.365 170.64 13.635 ;
     RECT  2.16 13.905 170.64 14.175 ;
     RECT  2.16 14.445 170.64 14.715 ;
     RECT  2.16 14.985 170.64 15.255 ;
     RECT  2.16 15.525 170.64 15.795 ;
     RECT  2.16 16.065 170.64 16.335 ;
     RECT  2.16 16.605 170.64 16.875 ;
     RECT  2.16 17.145 170.64 17.415 ;
     RECT  2.16 17.685 170.64 17.955 ;
     RECT  2.16 18.225 170.64 18.495 ;
     RECT  2.16 18.765 170.64 19.035 ;
     RECT  2.16 19.305 170.64 19.575 ;
     RECT  2.16 19.845 170.64 20.115 ;
     RECT  2.16 20.385 170.64 20.655 ;
     RECT  2.16 20.925 170.64 21.195 ;
     RECT  2.16 21.465 170.64 21.735 ;
     RECT  2.16 22.005 170.64 22.275 ;
     RECT  2.16 22.545 170.64 22.815 ;
     RECT  2.16 23.085 170.64 23.355 ;
     RECT  2.16 23.625 170.64 23.895 ;
     RECT  2.16 24.165 170.64 24.435 ;
     RECT  2.16 24.705 170.64 24.975 ;
     RECT  2.16 25.245 170.64 25.515 ;
     RECT  2.16 25.785 170.64 26.055 ;
     RECT  2.16 26.325 170.64 26.595 ;
     RECT  2.16 26.865 170.64 27.135 ;
     RECT  2.16 27.405 170.64 27.675 ;
     RECT  2.16 27.945 170.64 28.215 ;
     RECT  2.16 28.485 170.64 28.755 ;
     RECT  2.16 29.025 170.64 29.295 ;
     RECT  2.16 29.565 170.64 29.835 ;
     RECT  2.16 30.105 170.64 30.375 ;
     RECT  2.16 30.645 170.64 30.915 ;
     RECT  2.16 31.185 170.64 31.455 ;
     RECT  2.16 31.725 170.64 31.995 ;
     RECT  2.16 32.265 170.64 32.535 ;
     RECT  2.16 32.805 170.64 33.075 ;
     RECT  2.16 33.345 170.64 33.615 ;
     RECT  2.16 33.885 170.64 34.155 ;
     RECT  2.16 34.425 170.64 34.695 ;
     RECT  2.16 34.965 170.64 35.235 ;
     RECT  2.16 35.505 170.64 35.775 ;
     RECT  2.16 36.045 170.64 36.315 ;
     RECT  2.16 36.585 170.64 36.855 ;
     RECT  2.16 37.125 170.64 37.395 ;
     RECT  2.16 37.665 170.64 37.935 ;
     RECT  2.16 38.205 170.64 38.475 ;
     RECT  2.16 38.745 170.64 39.015 ;
     RECT  2.16 39.285 170.64 39.555 ;
     RECT  2.16 39.825 170.64 40.095 ;
     RECT  2.16 40.365 170.64 40.635 ;
     RECT  2.16 40.905 170.64 41.175 ;
     RECT  2.16 41.445 170.64 41.715 ;
     RECT  2.16 41.985 170.64 42.255 ;
     RECT  2.16 42.525 170.64 42.795 ;
     RECT  2.16 43.065 170.64 43.335 ;
     RECT  2.16 43.605 170.64 43.875 ;
     RECT  2.16 44.145 170.64 44.415 ;
     RECT  2.16 44.685 170.64 44.955 ;
     RECT  2.16 45.225 170.64 45.495 ;
     RECT  2.16 45.765 170.64 46.035 ;
     RECT  2.16 46.305 170.64 46.575 ;
     RECT  2.16 46.845 170.64 47.115 ;
     RECT  2.16 47.385 170.64 47.655 ;
     RECT  2.16 47.925 170.64 48.195 ;
     RECT  2.16 48.465 170.64 48.735 ;
     RECT  2.16 49.005 170.64 49.275 ;
     RECT  2.16 49.545 170.64 49.815 ;
     RECT  2.16 50.085 170.64 50.355 ;
     RECT  2.16 50.625 170.64 50.895 ;
     RECT  2.16 51.165 170.64 51.435 ;
     RECT  2.16 51.705 170.64 51.975 ;
     RECT  2.16 52.245 170.64 52.515 ;
     RECT  2.16 52.785 170.64 53.055 ;
     RECT  2.16 53.325 170.64 53.595 ;
     RECT  2.16 53.865 170.64 54.135 ;
     RECT  2.16 54.405 170.64 54.675 ;
     RECT  2.16 54.945 170.64 55.215 ;
     RECT  2.16 55.485 170.64 55.755 ;
     RECT  2.16 56.025 170.64 56.295 ;
     RECT  2.16 56.565 170.64 56.835 ;
     RECT  2.16 57.105 170.64 57.375 ;
     RECT  2.16 57.645 170.64 57.915 ;
     RECT  2.16 58.185 170.64 58.455 ;
     RECT  2.16 58.725 170.64 58.995 ;
     RECT  2.16 59.265 170.64 59.535 ;
     RECT  2.16 59.805 170.64 60.075 ;
     RECT  2.16 60.345 170.64 60.615 ;
     RECT  2.16 60.885 170.64 61.155 ;
     RECT  2.16 61.425 170.64 61.695 ;
     RECT  2.16 61.965 170.64 62.235 ;
     RECT  2.16 62.505 170.64 62.775 ;
     RECT  2.16 63.045 170.64 63.315 ;
     RECT  2.16 63.585 170.64 63.855 ;
     RECT  2.16 64.125 170.64 64.395 ;
     RECT  2.16 64.665 170.64 64.935 ;
     RECT  2.16 65.205 170.64 65.475 ;
     RECT  2.16 65.745 170.64 66.015 ;
     RECT  2.16 66.285 170.64 66.555 ;
     RECT  2.16 66.825 170.64 67.095 ;
     RECT  2.16 67.365 170.64 67.635 ;
     RECT  2.16 67.905 170.64 68.175 ;
     RECT  2.16 68.445 170.64 68.715 ;
     RECT  2.16 68.985 170.64 69.255 ;
     RECT  2.16 69.525 170.64 69.795 ;
     RECT  2.16 70.065 170.64 70.335 ;
     RECT  2.16 70.605 170.64 70.875 ;
     RECT  2.16 71.145 170.64 71.415 ;
     RECT  2.16 71.685 170.64 71.955 ;
     RECT  2.16 72.225 170.64 72.495 ;
     RECT  2.16 72.765 170.64 73.035 ;
     RECT  2.16 73.305 170.64 73.575 ;
     RECT  2.16 73.845 170.64 74.115 ;
     RECT  2.16 74.385 170.64 74.655 ;
     RECT  2.16 74.925 170.64 75.195 ;
     RECT  2.16 75.465 170.64 75.735 ;
     RECT  2.16 76.005 170.64 76.275 ;
     RECT  2.16 76.545 170.64 76.815 ;
     RECT  2.16 77.085 170.64 77.355 ;
     RECT  2.16 77.625 170.64 77.895 ;
     RECT  2.16 78.165 170.64 78.435 ;
     RECT  2.16 78.705 170.64 78.975 ;
     RECT  2.16 79.245 170.64 79.515 ;
     RECT  2.16 79.785 170.64 80.055 ;
     RECT  2.16 80.325 170.64 80.595 ;
     RECT  2.16 80.865 170.64 81.135 ;
     RECT  2.16 81.405 170.64 81.675 ;
     RECT  2.16 81.945 170.64 82.215 ;
     RECT  2.16 82.485 170.64 82.755 ;
     RECT  2.16 83.025 170.64 83.295 ;
     RECT  2.16 83.565 170.64 83.835 ;
     RECT  2.16 84.105 170.64 84.375 ;
     RECT  2.16 84.645 170.64 84.915 ;
     RECT  2.16 85.185 170.64 85.455 ;
     RECT  2.16 85.725 170.64 85.995 ;
     RECT  2.16 86.265 170.64 86.535 ;
     RECT  2.16 86.805 170.64 87.075 ;
     RECT  2.16 87.345 170.64 87.615 ;
     RECT  2.16 87.885 170.64 88.155 ;
     RECT  2.16 88.425 170.64 88.695 ;
     RECT  2.16 88.965 170.64 89.235 ;
     RECT  2.16 89.505 170.64 89.775 ;
     RECT  2.16 90.045 170.64 90.315 ;
     RECT  2.16 90.585 170.64 90.855 ;
     RECT  2.16 91.125 170.64 91.395 ;
     RECT  2.16 91.665 170.64 91.935 ;
     RECT  2.16 92.205 170.64 92.475 ;
     RECT  2.16 92.745 170.64 93.015 ;
     RECT  2.16 93.285 170.64 93.555 ;
     RECT  2.16 93.825 170.64 94.095 ;
     RECT  2.16 94.365 170.64 94.635 ;
     RECT  2.16 94.905 170.64 95.175 ;
     RECT  2.16 95.445 170.64 95.715 ;
     RECT  2.16 95.985 170.64 96.255 ;
     RECT  2.16 96.525 170.64 96.795 ;
     RECT  2.16 97.065 170.64 97.335 ;
     RECT  2.16 97.605 170.64 97.875 ;
     RECT  2.16 98.145 170.64 98.415 ;
     RECT  2.16 98.685 170.64 98.955 ;
     RECT  2.16 99.225 170.64 99.495 ;
     RECT  2.16 99.765 170.64 100.035 ;
     RECT  2.16 100.305 170.64 100.575 ;
     RECT  2.16 100.845 170.64 101.115 ;
     RECT  2.16 101.385 170.64 101.655 ;
     RECT  2.16 101.925 170.64 102.195 ;
     RECT  2.16 102.465 170.64 102.735 ;
     RECT  2.16 103.005 170.64 103.275 ;
     RECT  2.16 103.545 170.64 103.815 ;
     RECT  2.16 104.085 170.64 104.355 ;
     RECT  2.16 104.625 170.64 104.895 ;
     RECT  2.16 105.165 170.64 105.435 ;
     RECT  2.16 105.705 170.64 105.975 ;
     RECT  2.16 106.245 170.64 106.515 ;
     RECT  2.16 106.785 170.64 107.055 ;
     RECT  2.16 107.325 170.64 107.595 ;
     RECT  2.16 107.865 170.64 108.135 ;
     RECT  2.16 108.405 170.64 108.675 ;
     RECT  2.16 108.945 170.64 109.215 ;
     RECT  2.16 109.485 170.64 109.755 ;
     RECT  2.16 110.025 170.64 110.295 ;
     RECT  2.16 110.565 170.64 110.835 ;
     RECT  2.16 111.105 170.64 111.375 ;
     RECT  2.16 111.645 170.64 111.915 ;
     RECT  2.16 112.185 170.64 112.455 ;
     RECT  2.16 112.725 170.64 112.995 ;
     RECT  2.16 113.265 170.64 113.535 ;
     RECT  2.16 113.805 170.64 114.075 ;
     RECT  2.16 114.345 170.64 114.615 ;
     RECT  2.16 114.885 170.64 115.155 ;
     RECT  2.16 115.425 170.64 115.695 ;
     RECT  2.16 115.965 170.64 116.235 ;
     RECT  2.16 116.505 170.64 116.775 ;
     RECT  2.16 117.045 170.64 117.315 ;
     RECT  2.16 117.585 170.64 117.855 ;
     RECT  2.16 118.125 170.64 118.395 ;
     RECT  2.16 118.665 170.64 118.935 ;
     RECT  2.16 119.205 170.64 119.475 ;
     RECT  2.16 119.745 170.64 120.015 ;
     RECT  2.16 120.285 170.64 120.555 ;
     RECT  2.16 120.825 170.64 121.095 ;
     RECT  2.16 121.365 170.64 121.635 ;
     RECT  2.16 121.905 170.64 122.175 ;
     RECT  2.16 122.445 170.64 122.715 ;
     RECT  2.16 122.985 170.64 123.255 ;
     RECT  2.16 123.525 170.64 123.795 ;
     RECT  2.16 124.065 170.64 124.335 ;
     RECT  2.16 124.605 170.64 124.875 ;
     RECT  2.16 125.145 170.64 125.415 ;
     RECT  2.16 125.685 170.64 125.955 ;
     RECT  2.16 126.225 170.64 126.495 ;
     RECT  2.16 126.765 170.64 127.035 ;
     RECT  2.16 127.305 170.64 127.44 ;
    LAYER RVTP ;
     RECT  2.16 2.295 170.64 2.565 ;
     RECT  2.16 2.835 170.64 3.105 ;
     RECT  2.16 3.375 170.64 3.645 ;
     RECT  2.16 3.915 170.64 4.185 ;
     RECT  2.16 4.455 170.64 4.725 ;
     RECT  2.16 4.995 170.64 5.265 ;
     RECT  2.16 5.535 170.64 5.805 ;
     RECT  2.16 6.075 170.64 6.345 ;
     RECT  2.16 6.615 170.64 6.885 ;
     RECT  2.16 7.155 170.64 7.425 ;
     RECT  2.16 7.695 170.64 7.965 ;
     RECT  2.16 8.235 170.64 8.505 ;
     RECT  2.16 8.775 170.64 9.045 ;
     RECT  2.16 9.315 170.64 9.585 ;
     RECT  2.16 9.855 170.64 10.125 ;
     RECT  2.16 10.395 170.64 10.665 ;
     RECT  2.16 10.935 170.64 11.205 ;
     RECT  2.16 11.475 170.64 11.745 ;
     RECT  2.16 12.015 170.64 12.285 ;
     RECT  2.16 12.555 170.64 12.825 ;
     RECT  2.16 13.095 170.64 13.365 ;
     RECT  2.16 13.635 170.64 13.905 ;
     RECT  2.16 14.175 170.64 14.445 ;
     RECT  2.16 14.715 170.64 14.985 ;
     RECT  2.16 15.255 170.64 15.525 ;
     RECT  2.16 15.795 170.64 16.065 ;
     RECT  2.16 16.335 170.64 16.605 ;
     RECT  2.16 16.875 170.64 17.145 ;
     RECT  2.16 17.415 170.64 17.685 ;
     RECT  2.16 17.955 170.64 18.225 ;
     RECT  2.16 18.495 170.64 18.765 ;
     RECT  2.16 19.035 170.64 19.305 ;
     RECT  2.16 19.575 170.64 19.845 ;
     RECT  2.16 20.115 170.64 20.385 ;
     RECT  2.16 20.655 170.64 20.925 ;
     RECT  2.16 21.195 170.64 21.465 ;
     RECT  2.16 21.735 170.64 22.005 ;
     RECT  2.16 22.275 170.64 22.545 ;
     RECT  2.16 22.815 170.64 23.085 ;
     RECT  2.16 23.355 170.64 23.625 ;
     RECT  2.16 23.895 170.64 24.165 ;
     RECT  2.16 24.435 170.64 24.705 ;
     RECT  2.16 24.975 170.64 25.245 ;
     RECT  2.16 25.515 170.64 25.785 ;
     RECT  2.16 26.055 170.64 26.325 ;
     RECT  2.16 26.595 170.64 26.865 ;
     RECT  2.16 27.135 170.64 27.405 ;
     RECT  2.16 27.675 170.64 27.945 ;
     RECT  2.16 28.215 170.64 28.485 ;
     RECT  2.16 28.755 170.64 29.025 ;
     RECT  2.16 29.295 170.64 29.565 ;
     RECT  2.16 29.835 170.64 30.105 ;
     RECT  2.16 30.375 170.64 30.645 ;
     RECT  2.16 30.915 170.64 31.185 ;
     RECT  2.16 31.455 170.64 31.725 ;
     RECT  2.16 31.995 170.64 32.265 ;
     RECT  2.16 32.535 170.64 32.805 ;
     RECT  2.16 33.075 170.64 33.345 ;
     RECT  2.16 33.615 170.64 33.885 ;
     RECT  2.16 34.155 170.64 34.425 ;
     RECT  2.16 34.695 170.64 34.965 ;
     RECT  2.16 35.235 170.64 35.505 ;
     RECT  2.16 35.775 170.64 36.045 ;
     RECT  2.16 36.315 170.64 36.585 ;
     RECT  2.16 36.855 170.64 37.125 ;
     RECT  2.16 37.395 170.64 37.665 ;
     RECT  2.16 37.935 170.64 38.205 ;
     RECT  2.16 38.475 170.64 38.745 ;
     RECT  2.16 39.015 170.64 39.285 ;
     RECT  2.16 39.555 170.64 39.825 ;
     RECT  2.16 40.095 170.64 40.365 ;
     RECT  2.16 40.635 170.64 40.905 ;
     RECT  2.16 41.175 170.64 41.445 ;
     RECT  2.16 41.715 170.64 41.985 ;
     RECT  2.16 42.255 170.64 42.525 ;
     RECT  2.16 42.795 170.64 43.065 ;
     RECT  2.16 43.335 170.64 43.605 ;
     RECT  2.16 43.875 170.64 44.145 ;
     RECT  2.16 44.415 170.64 44.685 ;
     RECT  2.16 44.955 170.64 45.225 ;
     RECT  2.16 45.495 170.64 45.765 ;
     RECT  2.16 46.035 170.64 46.305 ;
     RECT  2.16 46.575 170.64 46.845 ;
     RECT  2.16 47.115 170.64 47.385 ;
     RECT  2.16 47.655 170.64 47.925 ;
     RECT  2.16 48.195 170.64 48.465 ;
     RECT  2.16 48.735 170.64 49.005 ;
     RECT  2.16 49.275 170.64 49.545 ;
     RECT  2.16 49.815 170.64 50.085 ;
     RECT  2.16 50.355 170.64 50.625 ;
     RECT  2.16 50.895 170.64 51.165 ;
     RECT  2.16 51.435 170.64 51.705 ;
     RECT  2.16 51.975 170.64 52.245 ;
     RECT  2.16 52.515 170.64 52.785 ;
     RECT  2.16 53.055 170.64 53.325 ;
     RECT  2.16 53.595 170.64 53.865 ;
     RECT  2.16 54.135 170.64 54.405 ;
     RECT  2.16 54.675 170.64 54.945 ;
     RECT  2.16 55.215 170.64 55.485 ;
     RECT  2.16 55.755 170.64 56.025 ;
     RECT  2.16 56.295 170.64 56.565 ;
     RECT  2.16 56.835 170.64 57.105 ;
     RECT  2.16 57.375 170.64 57.645 ;
     RECT  2.16 57.915 170.64 58.185 ;
     RECT  2.16 58.455 170.64 58.725 ;
     RECT  2.16 58.995 170.64 59.265 ;
     RECT  2.16 59.535 170.64 59.805 ;
     RECT  2.16 60.075 170.64 60.345 ;
     RECT  2.16 60.615 170.64 60.885 ;
     RECT  2.16 61.155 170.64 61.425 ;
     RECT  2.16 61.695 170.64 61.965 ;
     RECT  2.16 62.235 170.64 62.505 ;
     RECT  2.16 62.775 170.64 63.045 ;
     RECT  2.16 63.315 170.64 63.585 ;
     RECT  2.16 63.855 170.64 64.125 ;
     RECT  2.16 64.395 170.64 64.665 ;
     RECT  2.16 64.935 170.64 65.205 ;
     RECT  2.16 65.475 170.64 65.745 ;
     RECT  2.16 66.015 170.64 66.285 ;
     RECT  2.16 66.555 170.64 66.825 ;
     RECT  2.16 67.095 170.64 67.365 ;
     RECT  2.16 67.635 170.64 67.905 ;
     RECT  2.16 68.175 170.64 68.445 ;
     RECT  2.16 68.715 170.64 68.985 ;
     RECT  2.16 69.255 170.64 69.525 ;
     RECT  2.16 69.795 170.64 70.065 ;
     RECT  2.16 70.335 170.64 70.605 ;
     RECT  2.16 70.875 170.64 71.145 ;
     RECT  2.16 71.415 170.64 71.685 ;
     RECT  2.16 71.955 170.64 72.225 ;
     RECT  2.16 72.495 170.64 72.765 ;
     RECT  2.16 73.035 170.64 73.305 ;
     RECT  2.16 73.575 170.64 73.845 ;
     RECT  2.16 74.115 170.64 74.385 ;
     RECT  2.16 74.655 170.64 74.925 ;
     RECT  2.16 75.195 170.64 75.465 ;
     RECT  2.16 75.735 170.64 76.005 ;
     RECT  2.16 76.275 170.64 76.545 ;
     RECT  2.16 76.815 170.64 77.085 ;
     RECT  2.16 77.355 170.64 77.625 ;
     RECT  2.16 77.895 170.64 78.165 ;
     RECT  2.16 78.435 170.64 78.705 ;
     RECT  2.16 78.975 170.64 79.245 ;
     RECT  2.16 79.515 170.64 79.785 ;
     RECT  2.16 80.055 170.64 80.325 ;
     RECT  2.16 80.595 170.64 80.865 ;
     RECT  2.16 81.135 170.64 81.405 ;
     RECT  2.16 81.675 170.64 81.945 ;
     RECT  2.16 82.215 170.64 82.485 ;
     RECT  2.16 82.755 170.64 83.025 ;
     RECT  2.16 83.295 170.64 83.565 ;
     RECT  2.16 83.835 170.64 84.105 ;
     RECT  2.16 84.375 170.64 84.645 ;
     RECT  2.16 84.915 170.64 85.185 ;
     RECT  2.16 85.455 170.64 85.725 ;
     RECT  2.16 85.995 170.64 86.265 ;
     RECT  2.16 86.535 170.64 86.805 ;
     RECT  2.16 87.075 170.64 87.345 ;
     RECT  2.16 87.615 170.64 87.885 ;
     RECT  2.16 88.155 170.64 88.425 ;
     RECT  2.16 88.695 170.64 88.965 ;
     RECT  2.16 89.235 170.64 89.505 ;
     RECT  2.16 89.775 170.64 90.045 ;
     RECT  2.16 90.315 170.64 90.585 ;
     RECT  2.16 90.855 170.64 91.125 ;
     RECT  2.16 91.395 170.64 91.665 ;
     RECT  2.16 91.935 170.64 92.205 ;
     RECT  2.16 92.475 170.64 92.745 ;
     RECT  2.16 93.015 170.64 93.285 ;
     RECT  2.16 93.555 170.64 93.825 ;
     RECT  2.16 94.095 170.64 94.365 ;
     RECT  2.16 94.635 170.64 94.905 ;
     RECT  2.16 95.175 170.64 95.445 ;
     RECT  2.16 95.715 170.64 95.985 ;
     RECT  2.16 96.255 170.64 96.525 ;
     RECT  2.16 96.795 170.64 97.065 ;
     RECT  2.16 97.335 170.64 97.605 ;
     RECT  2.16 97.875 170.64 98.145 ;
     RECT  2.16 98.415 170.64 98.685 ;
     RECT  2.16 98.955 170.64 99.225 ;
     RECT  2.16 99.495 170.64 99.765 ;
     RECT  2.16 100.035 170.64 100.305 ;
     RECT  2.16 100.575 170.64 100.845 ;
     RECT  2.16 101.115 170.64 101.385 ;
     RECT  2.16 101.655 170.64 101.925 ;
     RECT  2.16 102.195 170.64 102.465 ;
     RECT  2.16 102.735 170.64 103.005 ;
     RECT  2.16 103.275 170.64 103.545 ;
     RECT  2.16 103.815 170.64 104.085 ;
     RECT  2.16 104.355 170.64 104.625 ;
     RECT  2.16 104.895 170.64 105.165 ;
     RECT  2.16 105.435 170.64 105.705 ;
     RECT  2.16 105.975 170.64 106.245 ;
     RECT  2.16 106.515 170.64 106.785 ;
     RECT  2.16 107.055 170.64 107.325 ;
     RECT  2.16 107.595 170.64 107.865 ;
     RECT  2.16 108.135 170.64 108.405 ;
     RECT  2.16 108.675 170.64 108.945 ;
     RECT  2.16 109.215 170.64 109.485 ;
     RECT  2.16 109.755 170.64 110.025 ;
     RECT  2.16 110.295 170.64 110.565 ;
     RECT  2.16 110.835 170.64 111.105 ;
     RECT  2.16 111.375 170.64 111.645 ;
     RECT  2.16 111.915 170.64 112.185 ;
     RECT  2.16 112.455 170.64 112.725 ;
     RECT  2.16 112.995 170.64 113.265 ;
     RECT  2.16 113.535 170.64 113.805 ;
     RECT  2.16 114.075 170.64 114.345 ;
     RECT  2.16 114.615 170.64 114.885 ;
     RECT  2.16 115.155 170.64 115.425 ;
     RECT  2.16 115.695 170.64 115.965 ;
     RECT  2.16 116.235 170.64 116.505 ;
     RECT  2.16 116.775 170.64 117.045 ;
     RECT  2.16 117.315 170.64 117.585 ;
     RECT  2.16 117.855 170.64 118.125 ;
     RECT  2.16 118.395 170.64 118.665 ;
     RECT  2.16 118.935 170.64 119.205 ;
     RECT  2.16 119.475 170.64 119.745 ;
     RECT  2.16 120.015 170.64 120.285 ;
     RECT  2.16 120.555 170.64 120.825 ;
     RECT  2.16 121.095 170.64 121.365 ;
     RECT  2.16 121.635 170.64 121.905 ;
     RECT  2.16 122.175 170.64 122.445 ;
     RECT  2.16 122.715 170.64 122.985 ;
     RECT  2.16 123.255 170.64 123.525 ;
     RECT  2.16 123.795 170.64 124.065 ;
     RECT  2.16 124.335 170.64 124.605 ;
     RECT  2.16 124.875 170.64 125.145 ;
     RECT  2.16 125.415 170.64 125.685 ;
     RECT  2.16 125.955 170.64 126.225 ;
     RECT  2.16 126.495 170.64 126.765 ;
     RECT  2.16 127.035 170.64 127.305 ;
    LAYER M1 ;
     RECT  2.16 2.151 170.64 127.449 ;
    LAYER M2 ;
     RECT  0.031 51.714 0.067 51.732 ;
     RECT  0.031 53.406 0.067 55.242 ;
     RECT  0.031 56.376 0.067 56.394 ;
     RECT  0.031 57.456 0.067 58.644 ;
     RECT  0.031 65.916 0.067 67.284 ;
     RECT  0.031 68.886 0.067 69.174 ;
     RECT  0.067 57.456 0.103 58.986 ;
     RECT  0.067 68.886 0.103 69.516 ;
     RECT  0.031 62.28 0.131 63.54 ;
     RECT  0.031 64.566 0.131 64.584 ;
     RECT  0.067 65.484 0.131 67.284 ;
     RECT  0.031 71.73 0.131 74.574 ;
     RECT  0.031 60.552 0.175 61.182 ;
     RECT  0.175 60.39 0.211 61.182 ;
     RECT  0.067 56.106 0.239 56.394 ;
     RECT  0.131 71.73 0.239 72.954 ;
     RECT  0.031 75.51 0.239 76.644 ;
     RECT  0.031 77.976 0.239 77.994 ;
     RECT  0.067 52.794 0.247 55.242 ;
     RECT  0.239 56.106 0.247 56.124 ;
     RECT  0.239 72.081 0.275 72.099 ;
     RECT  0.239 75.51 0.311 75.528 ;
     RECT  0.067 51.714 0.391 51.804 ;
     RECT  0.247 52.794 0.391 56.124 ;
     RECT  0.391 51.714 0.463 56.124 ;
     RECT  0.103 57.456 0.463 59.094 ;
     RECT  0.211 60.354 0.499 61.182 ;
     RECT  0.131 66.564 0.499 67.284 ;
     RECT  0.463 57.42 0.535 59.094 ;
     RECT  0.131 65.484 0.535 65.502 ;
     RECT  0.499 66.564 0.535 67.662 ;
     RECT  0.103 68.688 0.535 69.516 ;
     RECT  1.147 74.466 1.183 74.484 ;
     RECT  1.147 49.896 1.399 49.914 ;
     RECT  0.463 51.174 1.399 56.124 ;
     RECT  1.399 49.896 1.687 56.124 ;
     RECT  1.183 74.196 1.723 74.484 ;
     RECT  0.239 76.356 1.723 76.644 ;
     RECT  1.219 77.976 1.723 77.994 ;
     RECT  1.723 76.356 1.759 77.184 ;
     RECT  1.723 77.976 1.759 78.462 ;
     RECT  1.759 76.356 2.083 79.074 ;
     RECT  1.399 82.224 2.083 82.242 ;
     RECT  2.083 82.224 2.155 82.404 ;
     RECT  0.031 41.076 2.16 41.094 ;
     RECT  0.031 48.978 2.16 48.996 ;
     RECT  1.687 49.824 2.16 56.124 ;
     RECT  0.535 57.42 2.16 59.562 ;
     RECT  0.499 60.354 2.16 61.416 ;
     RECT  0.131 62.514 2.16 62.604 ;
     RECT  0.535 64.134 2.16 64.152 ;
     RECT  0.535 64.944 2.16 65.502 ;
     RECT  0.535 66.564 2.16 70.092 ;
     RECT  0.239 72.936 2.16 72.954 ;
     RECT  1.723 74.124 2.16 74.484 ;
     RECT  2.083 75.816 2.16 79.074 ;
     RECT  1.147 80.676 2.16 80.694 ;
     RECT  2.155 81.576 2.16 82.404 ;
     RECT  1.975 86.616 2.16 86.634 ;
     RECT  2.16 2.151 170.64 127.449 ;
     RECT  170.64 35.28 170.663 35.298 ;
     RECT  170.64 57.456 170.735 57.708 ;
     RECT  170.64 58.464 170.771 67.158 ;
     RECT  170.771 58.464 170.807 65.889 ;
     RECT  170.64 80.334 170.807 81.468 ;
     RECT  170.64 103.554 170.843 104.112 ;
     RECT  170.771 66.726 170.951 67.158 ;
     RECT  170.64 68.49 170.951 70.668 ;
     RECT  170.807 65.79 170.987 65.889 ;
     RECT  170.64 76.32 170.987 77.346 ;
     RECT  170.64 82.458 170.987 82.476 ;
     RECT  170.807 58.464 171.023 64.89 ;
     RECT  170.64 54.99 171.095 55.584 ;
     RECT  170.64 78.642 171.095 78.66 ;
     RECT  170.735 57.456 171.167 57.636 ;
     RECT  170.64 88.668 171.167 88.956 ;
     RECT  170.64 83.772 171.203 83.79 ;
     RECT  170.64 45.198 171.239 49.374 ;
     RECT  171.023 59.508 171.239 64.89 ;
     RECT  170.64 86.616 171.239 87.102 ;
     RECT  171.167 88.938 171.239 88.956 ;
     RECT  170.64 98.586 171.239 98.604 ;
     RECT  170.64 112.662 171.275 112.68 ;
     RECT  171.239 45.306 171.311 49.374 ;
     RECT  170.64 52.02 171.311 53.928 ;
     RECT  170.64 102.24 171.311 102.258 ;
     RECT  171.023 58.464 171.347 58.482 ;
     RECT  170.951 66.798 171.383 67.158 ;
     RECT  170.843 103.59 171.419 104.112 ;
     RECT  171.239 60.048 171.491 64.89 ;
     RECT  171.311 45.306 171.563 48.564 ;
     RECT  170.987 76.59 171.563 77.346 ;
     RECT  170.807 80.334 171.563 81.432 ;
     RECT  170.64 73.476 171.599 75.294 ;
     RECT  171.095 54.99 171.635 55.512 ;
     RECT  171.491 60.048 171.635 63.576 ;
     RECT  171.635 54.99 171.743 55.17 ;
     RECT  170.64 36.054 171.779 36.612 ;
     RECT  171.239 86.742 171.779 87.102 ;
     RECT  171.563 45.306 171.815 46.332 ;
     RECT  171.491 64.332 171.851 64.89 ;
     RECT  171.383 67.14 171.851 67.158 ;
     RECT  171.563 80.334 171.887 80.892 ;
     RECT  171.563 47.43 171.923 48.564 ;
     RECT  170.64 105.174 171.923 105.426 ;
     RECT  171.851 64.332 171.959 64.764 ;
     RECT  170.951 68.49 171.959 69.516 ;
     RECT  171.311 49.356 171.995 49.374 ;
     RECT  171.959 69.498 172.031 69.516 ;
     RECT  170.64 84.69 172.031 84.708 ;
     RECT  171.923 47.43 172.067 48.024 ;
     RECT  171.311 52.596 172.067 53.928 ;
     RECT  171.887 80.874 172.103 80.892 ;
     RECT  171.815 45.666 172.139 46.332 ;
     RECT  171.635 60.318 172.139 63.576 ;
     RECT  171.923 105.174 172.139 105.192 ;
     RECT  172.139 60.318 172.211 60.336 ;
     RECT  171.599 73.476 172.247 74.88 ;
     RECT  172.247 74.862 172.283 74.88 ;
     RECT  172.219 96.228 172.291 96.246 ;
     RECT  170.64 97.038 172.291 97.362 ;
     RECT  172.219 27.576 172.319 27.594 ;
     RECT  172.291 96.228 172.319 97.362 ;
     RECT  170.64 90.864 172.355 91.458 ;
     RECT  171.959 68.49 172.391 68.544 ;
     RECT  172.355 90.864 172.391 90.882 ;
     RECT  170.64 15.156 172.399 15.174 ;
     RECT  171.959 64.44 172.427 64.764 ;
     RECT  171.779 86.742 172.427 86.76 ;
     RECT  171.779 36.594 172.463 36.612 ;
     RECT  172.219 98.694 172.471 98.712 ;
     RECT  170.64 41.652 172.499 41.67 ;
     RECT  172.139 61.092 172.499 63.576 ;
     RECT  172.319 96.228 172.499 96.444 ;
     RECT  170.64 43.272 172.535 43.29 ;
     RECT  171.743 54.99 172.535 55.008 ;
     RECT  172.255 102.546 172.543 102.564 ;
     RECT  172.139 45.666 172.571 45.684 ;
     RECT  172.499 61.092 172.571 62.298 ;
     RECT  171.419 104.094 172.571 104.112 ;
     RECT  172.399 15.156 172.579 15.669 ;
     RECT  172.399 16.416 172.579 16.974 ;
     RECT  172.399 21.051 172.579 21.069 ;
     RECT  172.399 18.036 172.607 18.054 ;
     RECT  172.067 52.596 172.607 53.586 ;
     RECT  172.499 63.558 172.607 63.576 ;
     RECT  172.319 97.344 172.607 97.362 ;
     RECT  172.471 115.326 172.607 115.344 ;
     RECT  172.067 47.43 172.643 47.448 ;
     RECT  172.571 61.47 172.643 62.298 ;
     RECT  170.64 9.396 172.651 9.414 ;
     RECT  172.579 12.222 172.651 13.509 ;
     RECT  172.471 98.622 172.651 98.712 ;
     RECT  172.543 102.546 172.651 102.726 ;
     RECT  172.607 52.83 172.679 53.388 ;
     RECT  172.579 58.77 172.679 58.788 ;
     RECT  172.579 66.6 172.679 66.618 ;
     RECT  172.615 8.55 172.715 8.568 ;
     RECT  172.651 11.331 172.715 13.509 ;
     RECT  172.579 14.346 172.715 15.669 ;
     RECT  172.579 20.97 172.715 21.069 ;
     RECT  172.643 62.28 172.715 62.298 ;
     RECT  172.427 64.746 172.715 64.764 ;
     RECT  172.651 5.976 172.751 7.614 ;
     RECT  172.651 9.396 172.751 10.044 ;
     RECT  172.715 11.331 172.751 11.934 ;
     RECT  172.715 15.156 172.751 15.174 ;
     RECT  172.579 16.416 172.751 17.136 ;
     RECT  171.167 57.456 172.751 57.474 ;
     RECT  172.643 61.47 172.751 61.488 ;
     RECT  172.651 70.686 172.751 70.794 ;
     RECT  172.247 73.476 172.751 73.908 ;
     RECT  172.499 96.3 172.751 96.444 ;
     RECT  172.651 97.416 172.751 97.749 ;
     RECT  172.651 98.496 172.751 98.784 ;
     RECT  172.651 100.386 172.751 101.034 ;
     RECT  172.651 102.051 172.751 103.104 ;
     RECT  172.651 104.706 172.751 104.724 ;
     RECT  172.651 106.371 172.751 109.044 ;
     RECT  172.651 110.106 172.751 110.709 ;
     RECT  172.651 111.996 172.751 113.364 ;
     RECT  172.651 114.426 172.751 115.029 ;
     RECT  172.651 116.046 172.751 117.684 ;
     RECT  172.651 118.746 172.751 119.349 ;
     RECT  172.651 120.096 172.751 121.014 ;
     RECT  172.651 122.616 172.751 122.634 ;
     RECT  172.363 25.101 172.787 25.119 ;
     RECT  172.391 68.49 172.787 68.508 ;
     RECT  172.751 70.686 172.787 70.704 ;
     RECT  172.751 73.89 172.787 73.908 ;
     RECT  171.563 77.328 172.787 77.346 ;
     RECT  172.751 114.588 172.787 114.606 ;
    LAYER M3 ;
     RECT  2.415 2.143 2.505 2.413 ;
     RECT  7.815 2.143 7.905 2.413 ;
     RECT  13.215 2.143 13.305 2.413 ;
     RECT  18.615 2.143 18.705 2.413 ;
     RECT  24.015 2.143 24.105 2.413 ;
     RECT  29.415 2.143 29.505 2.413 ;
     RECT  34.815 2.143 34.905 2.413 ;
     RECT  40.215 2.143 40.305 2.413 ;
     RECT  45.615 2.143 45.705 2.413 ;
     RECT  51.015 2.143 51.105 2.413 ;
     RECT  56.415 2.143 56.505 2.413 ;
     RECT  61.815 2.143 61.905 2.413 ;
     RECT  67.215 2.143 67.305 2.413 ;
     RECT  72.615 2.143 72.705 2.413 ;
     RECT  78.015 2.143 78.105 2.413 ;
     RECT  83.415 2.143 83.505 2.413 ;
     RECT  88.815 2.143 88.905 2.413 ;
     RECT  94.215 2.143 94.305 2.413 ;
     RECT  99.615 2.143 99.705 2.413 ;
     RECT  105.015 2.143 105.105 2.413 ;
     RECT  110.415 2.143 110.505 2.413 ;
     RECT  115.815 2.143 115.905 2.413 ;
     RECT  121.215 2.143 121.305 2.413 ;
     RECT  126.615 2.143 126.705 2.413 ;
     RECT  132.015 2.143 132.105 2.413 ;
     RECT  137.415 2.143 137.505 2.413 ;
     RECT  142.815 2.143 142.905 2.413 ;
     RECT  148.215 2.143 148.305 2.413 ;
     RECT  153.615 2.143 153.705 2.413 ;
     RECT  159.015 2.143 159.105 2.413 ;
     RECT  164.415 2.143 164.505 2.413 ;
     RECT  169.815 2.143 169.905 2.413 ;
     RECT  169.815 2.413 170.097 5.755 ;
     RECT  172.728 5.947 172.746 5.971 ;
     RECT  167.868 2.875 167.886 5.995 ;
     RECT  167.868 5.995 168.21 6.091 ;
     RECT  164.415 2.413 164.697 6.139 ;
     RECT  167.868 6.091 168.714 6.331 ;
     RECT  171.756 5.851 171.774 6.427 ;
     RECT  172.656 5.971 172.746 6.427 ;
     RECT  167.868 6.331 169.074 6.619 ;
     RECT  169.815 5.755 170.658 6.619 ;
     RECT  164.415 6.139 165.078 6.907 ;
     RECT  166.176 6.043 166.194 6.907 ;
     RECT  164.415 6.907 166.194 7.051 ;
     RECT  164.304 7.051 166.194 7.195 ;
     RECT  160.452 7.051 160.47 7.483 ;
     RECT  164.304 7.195 166.302 7.529 ;
     RECT  163.296 7.339 163.314 7.915 ;
     RECT  159.015 2.413 159.297 7.963 ;
     RECT  158.472 7.963 159.297 8.093 ;
     RECT  164.415 7.529 166.302 8.491 ;
     RECT  162.756 7.915 163.314 8.539 ;
     RECT  167.868 6.619 170.838 9.307 ;
     RECT  167.868 9.307 170.874 9.403 ;
     RECT  171.756 6.427 172.746 9.403 ;
     RECT  164.415 8.491 166.842 9.787 ;
     RECT  167.868 9.403 172.746 9.787 ;
     RECT  162.216 8.539 163.314 9.835 ;
     RECT  164.415 9.787 172.746 10.049 ;
     RECT  164.415 10.049 172.674 10.061 ;
     RECT  164.415 10.061 172.566 10.843 ;
     RECT  162.216 9.835 163.458 11.227 ;
     RECT  164.415 10.843 172.638 11.32 ;
     RECT  158.148 9.391 158.166 11.947 ;
     RECT  153.615 2.413 153.897 11.995 ;
     RECT  154.692 8.155 154.71 11.995 ;
     RECT  153.615 11.995 154.71 12.187 ;
     RECT  158.04 11.947 158.166 12.283 ;
     RECT  160.452 7.483 160.506 12.475 ;
     RECT  159.015 8.093 159.297 12.763 ;
     RECT  160.092 12.475 160.506 12.763 ;
     RECT  156.96 8.059 156.978 12.859 ;
     RECT  158.04 12.283 158.238 12.859 ;
     RECT  156.096 8.251 156.114 13.051 ;
     RECT  156.96 12.859 158.238 13.051 ;
     RECT  153.615 12.187 154.962 13.291 ;
     RECT  164.415 11.32 172.746 13.432 ;
     RECT  153.615 13.291 155.25 13.579 ;
     RECT  162.216 11.227 163.53 13.819 ;
     RECT  164.304 13.432 172.746 13.819 ;
     RECT  162.216 13.819 172.746 14.155 ;
     RECT  153.18 13.579 155.25 14.443 ;
     RECT  156.096 13.051 158.238 14.443 ;
     RECT  153.18 14.443 158.238 15.151 ;
     RECT  162.18 14.155 172.746 15.179 ;
     RECT  162.18 15.179 172.71 16.411 ;
     RECT  162.18 16.411 172.746 16.843 ;
     RECT  161.928 16.843 172.746 17.467 ;
     RECT  153.144 15.151 158.238 17.947 ;
     RECT  159.015 12.763 160.506 20.011 ;
     RECT  161.352 17.467 172.746 20.011 ;
     RECT  152.568 17.947 158.238 24.907 ;
     RECT  159.015 20.011 172.746 25.096 ;
     RECT  0.036 40.315 0.054 41.099 ;
     RECT  152.28 24.907 158.238 41.647 ;
     RECT  159.015 25.096 172.782 41.647 ;
     RECT  152.28 41.647 172.782 41.783 ;
     RECT  152.28 41.783 158.238 46.381 ;
     RECT  159.015 41.783 172.782 46.381 ;
     RECT  2.415 2.413 2.697 47.191 ;
     RECT  2.415 47.191 2.754 47.461 ;
     RECT  2.415 47.461 2.934 47.551 ;
     RECT  2.415 47.551 3.87 47.821 ;
     RECT  34.815 2.413 35.097 48.085 ;
     RECT  110.415 2.413 110.697 48.085 ;
     RECT  2.268 47.821 3.87 48.091 ;
     RECT  13.215 2.413 13.497 48.091 ;
     RECT  24.015 2.413 24.297 48.091 ;
     RECT  45.615 2.413 45.897 48.091 ;
     RECT  56.415 2.413 56.697 48.091 ;
     RECT  67.215 2.413 67.497 48.091 ;
     RECT  78.015 2.413 78.297 48.091 ;
     RECT  88.815 2.413 89.097 48.091 ;
     RECT  99.615 2.413 99.897 48.091 ;
     RECT  121.215 2.413 121.497 48.091 ;
     RECT  126.615 2.413 126.897 48.091 ;
     RECT  34.704 48.085 35.097 48.125 ;
     RECT  110.304 48.085 110.697 48.125 ;
     RECT  13.104 48.091 13.497 48.128 ;
     RECT  23.904 48.091 24.297 48.128 ;
     RECT  45.504 48.091 45.897 48.128 ;
     RECT  56.304 48.091 56.697 48.128 ;
     RECT  67.104 48.091 67.497 48.128 ;
     RECT  77.904 48.091 78.297 48.128 ;
     RECT  88.704 48.091 89.097 48.128 ;
     RECT  99.504 48.091 99.897 48.128 ;
     RECT  121.104 48.091 121.497 48.128 ;
     RECT  125.136 48.091 125.154 48.173 ;
     RECT  2.268 48.091 4.266 48.271 ;
     RECT  124.812 48.271 124.83 48.317 ;
     RECT  126.252 48.091 126.897 48.361 ;
     RECT  2.268 48.271 4.59 48.433 ;
     RECT  148.215 2.413 148.497 48.433 ;
     RECT  125.964 48.361 126.897 48.461 ;
     RECT  2.196 48.433 4.59 48.631 ;
     RECT  6.516 47.191 6.534 48.739 ;
     RECT  96.192 47.857 96.21 48.739 ;
     RECT  6.516 48.739 6.822 48.839 ;
     RECT  146.592 48.235 146.61 48.937 ;
     RECT  2.196 48.631 4.662 49.243 ;
     RECT  13.215 48.128 13.497 49.711 ;
     RECT  24.015 48.128 24.297 49.711 ;
     RECT  34.815 48.125 35.097 49.711 ;
     RECT  45.615 48.128 45.897 49.711 ;
     RECT  56.415 48.128 56.697 49.711 ;
     RECT  67.215 48.128 67.497 49.711 ;
     RECT  78.015 48.128 78.297 49.711 ;
     RECT  88.815 48.128 89.097 49.711 ;
     RECT  99.615 48.128 99.897 49.711 ;
     RECT  110.415 48.125 110.697 49.711 ;
     RECT  121.215 48.128 121.497 49.711 ;
     RECT  126.615 48.461 126.897 49.723 ;
     RECT  2.196 49.243 5.094 49.819 ;
     RECT  1.692 49.819 5.094 49.891 ;
     RECT  6.516 48.839 6.534 49.891 ;
     RECT  126.252 49.723 126.897 49.981 ;
     RECT  96.192 48.739 96.642 50.017 ;
     RECT  13.104 49.711 13.497 50.053 ;
     RECT  125.964 49.981 126.897 50.141 ;
     RECT  34.704 49.711 35.097 50.285 ;
     RECT  110.304 49.711 110.697 50.285 ;
     RECT  13.104 50.053 13.698 50.288 ;
     RECT  23.904 49.711 24.297 50.288 ;
     RECT  45.504 49.711 45.897 50.288 ;
     RECT  56.304 49.711 56.697 50.288 ;
     RECT  67.104 49.711 67.497 50.288 ;
     RECT  77.904 49.711 78.297 50.288 ;
     RECT  88.704 49.711 89.097 50.288 ;
     RECT  99.504 49.711 99.897 50.288 ;
     RECT  121.104 49.711 121.497 50.288 ;
     RECT  1.152 49.891 5.094 50.323 ;
     RECT  97.848 50.089 97.866 50.323 ;
     RECT  1.152 50.323 5.202 50.431 ;
     RECT  125.136 50.251 125.154 50.549 ;
     RECT  6.516 49.891 6.822 50.557 ;
     RECT  126.54 50.141 126.897 50.557 ;
     RECT  147.96 48.433 148.497 50.557 ;
     RECT  6.516 50.557 6.858 50.657 ;
     RECT  124.884 50.557 124.902 50.683 ;
     RECT  126.54 50.557 126.954 50.693 ;
     RECT  124.812 50.683 124.902 50.729 ;
     RECT  96.192 50.017 96.858 51.097 ;
     RECT  0.036 48.973 0.054 51.169 ;
     RECT  1.152 50.431 5.418 51.169 ;
     RECT  145.116 48.703 145.134 51.169 ;
     RECT  126.54 50.693 126.897 51.197 ;
     RECT  95.94 51.097 96.858 51.205 ;
     RECT  97.776 50.323 97.866 51.205 ;
     RECT  95.94 51.205 97.866 51.269 ;
     RECT  146.592 48.937 146.682 51.331 ;
     RECT  13.215 50.288 13.698 51.539 ;
     RECT  125.136 51.403 125.154 51.629 ;
     RECT  6.516 50.657 6.534 51.637 ;
     RECT  142.815 2.413 143.097 51.637 ;
     RECT  146.592 51.331 146.718 51.637 ;
     RECT  96.624 51.269 97.866 51.773 ;
     RECT  6.516 51.637 6.858 51.809 ;
     RECT  124.812 51.781 124.83 51.821 ;
     RECT  99.615 50.288 99.897 51.907 ;
     RECT  0.036 51.169 5.418 51.917 ;
     RECT  6.516 51.809 6.534 51.935 ;
     RECT  146.556 51.637 146.718 51.943 ;
     RECT  147.528 50.557 148.497 51.943 ;
     RECT  0.036 51.917 0.63 52.013 ;
     RECT  99.615 51.907 99.954 52.079 ;
     RECT  146.556 51.943 148.497 52.169 ;
     RECT  146.556 52.169 147.402 52.205 ;
     RECT  96.624 51.773 97.218 52.439 ;
     RECT  144.792 51.169 145.134 52.439 ;
     RECT  146.556 52.205 146.754 52.447 ;
     RECT  98.388 52.321 98.406 52.483 ;
     RECT  98.388 52.483 98.622 52.519 ;
     RECT  146.52 52.447 146.754 52.547 ;
     RECT  146.52 52.547 146.538 52.619 ;
     RECT  1.404 51.917 5.418 52.681 ;
     RECT  126.615 51.197 126.897 52.681 ;
     RECT  0.072 52.013 0.63 52.685 ;
     RECT  138.996 51.943 139.014 52.709 ;
     RECT  1.404 52.681 5.454 52.733 ;
     RECT  126.615 52.681 127.422 52.733 ;
     RECT  150.552 52.717 150.57 52.753 ;
     RECT  126.615 52.733 127.098 52.781 ;
     RECT  152.28 46.381 172.782 52.795 ;
     RECT  142.815 51.637 143.226 52.817 ;
     RECT  132.015 2.413 132.297 52.843 ;
     RECT  142.815 52.817 143.097 52.843 ;
     RECT  150.48 52.753 150.57 52.843 ;
     RECT  98.244 52.519 98.622 52.853 ;
     RECT  150.48 52.843 150.606 52.853 ;
     RECT  98.352 52.853 98.622 52.861 ;
     RECT  131.904 52.843 132.297 52.889 ;
     RECT  142.704 52.843 143.097 52.889 ;
     RECT  98.352 52.861 98.694 52.925 ;
     RECT  97.2 52.439 97.218 52.979 ;
     RECT  98.676 52.925 98.694 53.021 ;
     RECT  150.588 52.853 150.606 53.021 ;
     RECT  99.615 52.079 99.897 53.131 ;
     RECT  151.596 52.795 172.782 53.131 ;
     RECT  1.404 52.733 5.418 53.159 ;
     RECT  126.615 52.781 126.897 53.221 ;
     RECT  126.612 53.221 126.897 53.275 ;
     RECT  2.196 53.159 5.418 53.285 ;
     RECT  126.54 53.275 126.897 53.321 ;
     RECT  0.072 52.685 0.558 53.401 ;
     RECT  145.116 52.439 145.134 53.519 ;
     RECT  151.56 53.131 172.782 53.555 ;
     RECT  97.416 53.293 97.434 53.563 ;
     RECT  97.416 53.563 97.614 53.599 ;
     RECT  0.036 53.401 0.558 53.611 ;
     RECT  1.404 53.159 1.422 53.611 ;
     RECT  2.304 53.285 5.418 53.635 ;
     RECT  0.036 53.611 1.422 53.741 ;
     RECT  94.215 2.413 94.497 53.761 ;
     RECT  95.256 53.329 95.274 53.761 ;
     RECT  97.416 53.599 97.758 53.761 ;
     RECT  146.484 53.635 146.502 53.789 ;
     RECT  2.304 53.635 5.49 53.797 ;
     RECT  97.416 53.761 98.19 53.797 ;
     RECT  98.928 53.131 99.897 53.797 ;
     RECT  97.416 53.797 99.897 53.833 ;
     RECT  1.404 53.741 1.422 53.837 ;
     RECT  97.416 53.833 99.954 53.869 ;
     RECT  6.84 53.329 6.858 53.941 ;
     RECT  2.304 53.797 5.634 54.029 ;
     RECT  151.272 53.635 151.434 54.059 ;
     RECT  97.272 53.869 99.954 54.095 ;
     RECT  151.272 54.059 151.29 54.095 ;
     RECT  97.848 54.095 99.954 54.329 ;
     RECT  141.804 53.527 141.822 54.329 ;
     RECT  6.804 53.941 6.858 54.409 ;
     RECT  6.804 54.409 6.966 54.481 ;
     RECT  150.552 54.409 150.57 54.481 ;
     RECT  150.48 54.481 150.57 54.509 ;
     RECT  34.815 50.285 35.097 54.565 ;
     RECT  110.415 50.285 110.697 54.565 ;
     RECT  2.376 54.029 5.634 54.571 ;
     RECT  13.215 51.539 13.497 54.571 ;
     RECT  24.015 50.288 24.297 54.571 ;
     RECT  45.615 50.288 45.897 54.571 ;
     RECT  56.415 50.288 56.697 54.571 ;
     RECT  67.215 50.288 67.497 54.571 ;
     RECT  78.015 50.288 78.297 54.571 ;
     RECT  88.815 50.288 89.097 54.571 ;
     RECT  121.215 50.288 121.497 54.571 ;
     RECT  94.215 53.761 95.274 54.599 ;
     RECT  34.704 54.565 35.097 54.605 ;
     RECT  110.304 54.565 110.697 54.605 ;
     RECT  90.756 54.409 90.774 54.607 ;
     RECT  13.104 54.571 13.497 54.608 ;
     RECT  23.904 54.571 24.297 54.608 ;
     RECT  45.504 54.571 45.897 54.608 ;
     RECT  56.304 54.571 56.697 54.608 ;
     RECT  67.104 54.571 67.497 54.608 ;
     RECT  77.904 54.571 78.297 54.608 ;
     RECT  88.704 54.571 89.097 54.608 ;
     RECT  99.504 54.329 99.954 54.608 ;
     RECT  121.104 54.571 121.497 54.608 ;
     RECT  125.568 54.571 125.586 54.608 ;
     RECT  94.215 54.599 95.13 54.635 ;
     RECT  2.376 54.571 5.742 54.643 ;
     RECT  6.624 54.481 6.966 54.643 ;
     RECT  2.376 54.643 6.966 54.671 ;
     RECT  90.684 54.607 90.774 54.671 ;
     RECT  97.848 54.329 98.766 54.671 ;
     RECT  90.684 54.671 90.702 54.707 ;
     RECT  125.244 54.667 125.262 54.707 ;
     RECT  143.82 53.365 143.838 54.715 ;
     RECT  142.815 52.889 143.097 54.751 ;
     RECT  99.615 54.608 99.954 54.869 ;
     RECT  142.74 54.751 143.097 54.905 ;
     RECT  2.376 54.671 6.93 54.955 ;
     RECT  102.492 54.985 102.51 55.021 ;
     RECT  2.304 54.955 6.93 55.049 ;
     RECT  138.528 54.877 138.546 55.049 ;
     RECT  98.604 54.671 98.766 55.139 ;
     RECT  143.82 54.715 144.234 55.139 ;
     RECT  145.152 54.913 145.17 55.139 ;
     RECT  143.82 55.139 144.126 55.175 ;
     RECT  137.415 2.413 137.697 55.183 ;
     RECT  102.492 55.021 102.582 55.211 ;
     RECT  146.484 55.111 146.502 55.211 ;
     RECT  137.415 55.183 137.934 55.409 ;
     RECT  146.556 55.381 146.574 55.481 ;
     RECT  150.48 54.509 150.498 55.489 ;
     RECT  94.215 54.635 94.497 55.561 ;
     RECT  95.616 55.525 95.634 55.561 ;
     RECT  150.48 55.489 150.57 55.651 ;
     RECT  0.036 53.741 0.558 55.675 ;
     RECT  95.616 55.561 95.706 55.679 ;
     RECT  95.616 55.679 95.634 55.751 ;
     RECT  150.048 55.651 150.57 55.787 ;
     RECT  98.604 55.139 98.694 55.823 ;
     RECT  0.036 55.675 1.17 55.853 ;
     RECT  94.215 55.561 94.698 55.957 ;
     RECT  150.048 55.787 150.498 55.957 ;
     RECT  2.34 55.049 6.93 56.011 ;
     RECT  142.815 54.905 143.097 56.065 ;
     RECT  143.82 55.175 143.838 56.065 ;
     RECT  152.28 53.555 172.782 56.065 ;
     RECT  94.068 55.957 94.698 56.101 ;
     RECT  97.848 54.671 97.866 56.101 ;
     RECT  152.172 56.065 172.782 56.101 ;
     RECT  0.036 55.853 0.522 56.141 ;
     RECT  124.848 55.963 124.866 56.191 ;
     RECT  132.015 52.889 132.297 56.191 ;
     RECT  142.815 56.065 143.838 56.191 ;
     RECT  124.236 56.191 124.866 56.219 ;
     RECT  96.588 55.561 96.606 56.227 ;
     RECT  131.904 56.191 132.297 56.237 ;
     RECT  142.704 56.191 143.838 56.237 ;
     RECT  94.068 56.101 94.734 56.255 ;
     RECT  97.848 56.101 97.938 56.255 ;
     RECT  96.588 56.227 96.714 56.263 ;
     RECT  0.036 56.141 0.306 56.333 ;
     RECT  124.236 56.219 124.254 56.333 ;
     RECT  0.036 56.333 0.27 56.429 ;
     RECT  94.068 56.255 94.662 56.489 ;
     RECT  142.815 56.237 143.838 56.489 ;
     RECT  96.48 56.263 96.714 56.497 ;
     RECT  96.372 56.497 96.714 56.561 ;
     RECT  149.94 55.957 150.498 56.569 ;
     RECT  94.215 56.489 94.662 56.597 ;
     RECT  149.94 56.569 150.57 56.605 ;
     RECT  0.072 56.429 0.27 56.621 ;
     RECT  97.632 56.569 97.722 56.641 ;
     RECT  142.815 56.489 143.586 56.669 ;
     RECT  34.815 54.605 35.097 56.725 ;
     RECT  110.415 54.605 110.697 56.725 ;
     RECT  13.215 54.608 13.497 56.731 ;
     RECT  24.015 54.608 24.297 56.731 ;
     RECT  45.615 54.608 45.897 56.731 ;
     RECT  56.415 54.608 56.697 56.731 ;
     RECT  67.215 54.608 67.497 56.731 ;
     RECT  78.015 54.608 78.297 56.731 ;
     RECT  88.815 54.608 89.097 56.731 ;
     RECT  99.615 54.869 99.897 56.731 ;
     RECT  121.215 54.608 121.497 56.731 ;
     RECT  34.704 56.725 35.097 56.765 ;
     RECT  110.304 56.725 110.697 56.765 ;
     RECT  122.544 56.641 122.562 56.767 ;
     RECT  125.532 56.731 125.838 56.767 ;
     RECT  126.615 53.321 126.897 56.767 ;
     RECT  13.104 56.731 13.497 56.768 ;
     RECT  23.904 56.731 24.297 56.768 ;
     RECT  45.504 56.731 45.897 56.768 ;
     RECT  56.304 56.731 56.697 56.768 ;
     RECT  67.104 56.731 67.497 56.768 ;
     RECT  77.904 56.731 78.297 56.768 ;
     RECT  88.704 56.731 89.097 56.768 ;
     RECT  99.504 56.731 99.897 56.768 ;
     RECT  121.104 56.731 121.497 56.768 ;
     RECT  125.532 56.767 126.897 56.768 ;
     RECT  125.532 56.768 125.55 56.813 ;
     RECT  97.56 56.641 97.722 56.831 ;
     RECT  126.54 56.768 126.897 56.867 ;
     RECT  98.676 56.767 98.694 56.903 ;
     RECT  96.372 56.561 96.39 56.939 ;
     RECT  126.615 56.867 126.897 57.001 ;
     RECT  126.615 57.001 126.99 57.037 ;
     RECT  149.904 56.605 150.57 57.037 ;
     RECT  151.74 56.101 172.782 57.037 ;
     RECT  151.704 57.037 172.782 57.073 ;
     RECT  2.304 56.011 6.93 57.109 ;
     RECT  126.615 57.037 127.062 57.109 ;
     RECT  122.544 56.767 122.634 57.137 ;
     RECT  144.972 56.839 144.99 57.145 ;
     RECT  2.304 57.109 7.002 57.163 ;
     RECT  142.815 56.669 143.154 57.181 ;
     RECT  144.9 57.145 144.99 57.181 ;
     RECT  2.268 57.163 7.002 57.209 ;
     RECT  126.615 57.109 127.134 57.271 ;
     RECT  97.2 57.001 97.218 57.299 ;
     RECT  142.164 57.181 143.154 57.299 ;
     RECT  144.864 57.181 144.99 57.299 ;
     RECT  2.304 57.209 7.002 57.307 ;
     RECT  7.815 2.413 8.097 57.307 ;
     RECT  144.864 57.299 144.918 57.335 ;
     RECT  122.544 57.137 122.562 57.407 ;
     RECT  0.108 56.621 0.27 57.415 ;
     RECT  144.9 57.335 144.918 57.443 ;
     RECT  0.108 57.415 0.486 57.451 ;
     RECT  148.215 52.169 148.497 57.451 ;
     RECT  149.868 57.037 150.57 57.451 ;
     RECT  151.308 57.073 172.782 57.451 ;
     RECT  2.304 57.307 8.097 57.569 ;
     RECT  140.22 57.109 140.238 57.569 ;
     RECT  147.744 57.451 148.497 57.569 ;
     RECT  126.615 57.271 127.422 57.685 ;
     RECT  132.015 56.237 132.297 57.721 ;
     RECT  126.615 57.685 128.07 57.839 ;
     RECT  131.868 57.721 132.297 57.991 ;
     RECT  149.868 57.451 172.782 57.991 ;
     RECT  126.615 57.839 127.566 58.109 ;
     RECT  149.652 57.991 172.782 58.109 ;
     RECT  2.304 57.569 6.822 58.117 ;
     RECT  131.724 57.991 132.297 58.145 ;
     RECT  2.232 58.117 6.822 58.217 ;
     RECT  146.484 57.847 146.502 58.225 ;
     RECT  0.036 57.451 0.558 58.253 ;
     RECT  146.16 58.225 146.502 58.261 ;
     RECT  142.815 57.299 143.097 58.351 ;
     RECT  142.704 58.351 143.097 58.387 ;
     RECT  131.904 58.145 132.297 58.397 ;
     RECT  146.16 58.261 146.574 58.415 ;
     RECT  146.556 58.415 146.574 58.459 ;
     RECT  122.544 58.387 122.562 58.487 ;
     RECT  142.524 58.387 143.097 58.487 ;
     RECT  2.376 58.217 6.822 58.495 ;
     RECT  126.615 58.109 127.494 58.559 ;
     RECT  139.644 57.835 139.662 58.559 ;
     RECT  146.556 58.459 146.646 58.559 ;
     RECT  2.376 58.495 6.894 58.621 ;
     RECT  128.304 58.411 128.322 58.621 ;
     RECT  128.232 58.621 128.322 58.649 ;
     RECT  149.688 58.109 172.782 58.649 ;
     RECT  150.48 58.649 172.782 58.685 ;
     RECT  0.036 58.253 0.522 58.733 ;
     RECT  151.056 58.685 172.782 58.757 ;
     RECT  0.036 58.733 0.486 58.829 ;
     RECT  2.376 58.621 7.074 58.891 ;
     RECT  7.815 57.569 8.097 58.891 ;
     RECT  128.232 58.649 128.286 58.987 ;
     RECT  0.072 58.829 0.486 59.021 ;
     RECT  2.376 58.891 8.097 59.099 ;
     RECT  0.108 59.021 0.486 59.117 ;
     RECT  2.376 59.099 6.75 59.269 ;
     RECT  2.34 59.269 6.75 59.371 ;
     RECT  151.488 58.757 172.782 59.459 ;
     RECT  0.252 59.117 0.486 59.539 ;
     RECT  2.304 59.371 6.75 59.639 ;
     RECT  127.692 58.987 128.286 59.701 ;
     RECT  126.615 58.559 126.897 59.707 ;
     RECT  149.904 59.575 149.922 59.729 ;
     RECT  150.66 59.611 151.146 59.801 ;
     RECT  124.812 59.701 124.83 59.803 ;
     RECT  126.54 59.707 126.897 59.837 ;
     RECT  127.692 59.701 128.862 59.837 ;
     RECT  124.488 59.803 124.83 59.843 ;
     RECT  137.415 55.409 137.697 59.881 ;
     RECT  150.66 59.801 150.678 59.885 ;
     RECT  127.692 59.837 128.286 59.999 ;
     RECT  2.34 59.639 6.75 60.029 ;
     RECT  128.268 59.999 128.286 60.029 ;
     RECT  0.252 59.539 0.558 60.043 ;
     RECT  150.48 60.007 150.57 60.179 ;
     RECT  124.524 59.843 124.83 60.241 ;
     RECT  139.356 60.151 139.374 60.305 ;
     RECT  6.552 60.029 6.75 60.313 ;
     RECT  124.524 60.241 125.478 60.317 ;
     RECT  124.524 60.317 125.442 60.377 ;
     RECT  137.304 59.881 137.697 60.421 ;
     RECT  142.815 58.487 143.097 60.421 ;
     RECT  152.244 59.459 172.782 60.421 ;
     RECT  2.34 60.029 5.814 60.427 ;
     RECT  13.215 56.768 13.497 60.511 ;
     RECT  24.015 56.768 24.297 60.511 ;
     RECT  34.815 56.765 35.097 60.511 ;
     RECT  45.615 56.768 45.897 60.511 ;
     RECT  56.415 56.768 56.697 60.511 ;
     RECT  67.215 56.768 67.497 60.511 ;
     RECT  78.015 56.768 78.297 60.511 ;
     RECT  88.815 56.768 89.097 60.511 ;
     RECT  99.615 56.768 99.897 60.511 ;
     RECT  110.415 56.765 110.697 60.511 ;
     RECT  121.215 56.768 121.497 60.511 ;
     RECT  142.815 60.421 143.154 60.511 ;
     RECT  0.144 60.043 0.558 60.523 ;
     RECT  2.304 60.427 5.814 60.539 ;
     RECT  136.728 60.421 137.697 60.539 ;
     RECT  6.552 60.313 6.966 60.547 ;
     RECT  7.815 59.099 8.097 60.547 ;
     RECT  124.524 60.377 124.542 60.557 ;
     RECT  122.616 60.547 122.634 60.647 ;
     RECT  125.424 60.377 125.442 60.647 ;
     RECT  138.564 60.547 138.582 60.647 ;
     RECT  150.48 60.179 150.534 60.647 ;
     RECT  151.884 60.421 172.782 60.653 ;
     RECT  142.815 60.511 143.226 60.655 ;
     RECT  94.215 56.597 94.497 60.691 ;
     RECT  124.236 60.619 124.254 60.719 ;
     RECT  136.584 60.619 136.602 60.719 ;
     RECT  2.34 60.539 5.814 60.763 ;
     RECT  6.552 60.547 8.097 60.763 ;
     RECT  94.215 60.691 95.238 60.781 ;
     RECT  129.132 60.571 129.15 60.808 ;
     RECT  90.72 60.691 90.81 60.809 ;
     RECT  126.615 59.837 126.897 60.817 ;
     RECT  128.808 60.808 129.15 60.817 ;
     RECT  148.215 57.569 148.497 60.817 ;
     RECT  93.852 60.781 95.454 60.845 ;
     RECT  150.516 60.647 150.534 60.845 ;
     RECT  98.064 60.691 98.082 60.853 ;
     RECT  10.764 60.781 10.782 60.881 ;
     RECT  126.612 60.817 126.897 60.889 ;
     RECT  128.808 60.817 129.222 60.889 ;
     RECT  93.852 60.845 95.382 60.917 ;
     RECT  148.215 60.817 148.806 60.941 ;
     RECT  93.852 60.917 95.058 60.953 ;
     RECT  97.992 60.853 98.082 60.953 ;
     RECT  90.72 60.809 90.738 60.989 ;
     RECT  126.54 60.889 126.897 60.989 ;
     RECT  128.808 60.889 129.294 60.989 ;
     RECT  34.704 60.511 35.097 61.085 ;
     RECT  110.304 60.511 110.697 61.085 ;
     RECT  13.104 60.511 13.497 61.088 ;
     RECT  23.904 60.511 24.297 61.088 ;
     RECT  45.504 60.511 45.897 61.088 ;
     RECT  56.304 60.511 56.697 61.088 ;
     RECT  67.104 60.511 67.497 61.088 ;
     RECT  77.904 60.511 78.297 61.088 ;
     RECT  88.704 60.511 89.097 61.088 ;
     RECT  99.504 60.511 99.897 61.088 ;
     RECT  121.104 60.511 121.497 61.088 ;
     RECT  151.344 60.955 151.362 61.115 ;
     RECT  10.8 61.051 10.818 61.181 ;
     RECT  97.56 61.123 97.578 61.349 ;
     RECT  142.815 60.655 143.478 61.393 ;
     RECT  2.34 60.763 8.097 61.483 ;
     RECT  142.815 61.393 143.658 61.627 ;
     RECT  2.304 61.483 8.097 61.661 ;
     RECT  142.488 61.627 143.658 61.727 ;
     RECT  2.304 61.661 6.966 61.799 ;
     RECT  7.812 61.661 8.097 61.799 ;
     RECT  94.215 60.953 95.058 61.799 ;
     RECT  149.796 61.699 150.57 61.799 ;
     RECT  0.036 60.523 0.558 61.805 ;
     RECT  126.615 60.989 126.897 61.861 ;
     RECT  128.808 60.989 129.15 61.889 ;
     RECT  142.815 61.727 143.658 61.889 ;
     RECT  128.808 61.889 128.826 61.901 ;
     RECT  152.244 60.653 172.782 61.933 ;
     RECT  126.36 61.861 126.897 61.963 ;
     RECT  151.524 61.933 172.782 61.969 ;
     RECT  149.796 61.799 150.498 62.005 ;
     RECT  126.072 61.963 126.897 62.069 ;
     RECT  0.036 61.805 0.522 62.093 ;
     RECT  146.484 61.771 146.502 62.203 ;
     RECT  146.484 62.203 146.574 62.311 ;
     RECT  145.908 62.311 146.574 62.339 ;
     RECT  126.615 62.069 126.897 62.401 ;
     RECT  151.452 61.969 172.782 62.401 ;
     RECT  0.036 62.093 0.306 62.477 ;
     RECT  145.908 62.339 146.538 62.509 ;
     RECT  2.34 61.799 6.966 62.581 ;
     RECT  145.764 62.509 146.538 62.609 ;
     RECT  0.036 62.477 0.234 62.669 ;
     RECT  2.34 62.581 7.002 62.671 ;
     RECT  7.815 61.799 8.097 62.671 ;
     RECT  149.724 62.005 150.498 62.671 ;
     RECT  18.615 2.413 18.897 62.683 ;
     RECT  51.015 2.413 51.297 62.683 ;
     RECT  67.215 61.088 67.497 62.683 ;
     RECT  78.015 61.088 78.297 62.683 ;
     RECT  94.215 61.799 94.497 62.683 ;
     RECT  142.815 61.889 143.097 62.683 ;
     RECT  146.484 62.609 146.538 62.699 ;
     RECT  29.415 2.413 29.697 62.707 ;
     RECT  34.815 61.085 35.097 62.707 ;
     RECT  106.596 62.683 106.614 62.707 ;
     RECT  137.415 60.539 137.697 62.707 ;
     RECT  29.088 62.707 29.697 62.807 ;
     RECT  60.984 62.707 61.002 62.807 ;
     RECT  106.596 62.707 106.65 62.807 ;
     RECT  10.836 62.683 10.854 62.813 ;
     RECT  18.615 62.683 18.918 62.813 ;
     RECT  22.788 62.683 22.806 62.813 ;
     RECT  26.748 62.683 26.766 62.813 ;
     RECT  34.74 62.707 35.097 62.813 ;
     RECT  38.772 62.683 38.79 62.813 ;
     RECT  42.732 62.683 42.75 62.813 ;
     RECT  46.728 62.683 46.746 62.813 ;
     RECT  50.724 62.683 51.297 62.813 ;
     RECT  58.68 62.683 58.698 62.813 ;
     RECT  66.708 62.683 67.497 62.813 ;
     RECT  74.664 62.683 74.682 62.813 ;
     RECT  78.015 62.683 78.678 62.813 ;
     RECT  82.62 62.683 82.638 62.813 ;
     RECT  86.616 62.683 86.634 62.813 ;
     RECT  90.612 62.683 90.63 62.813 ;
     RECT  94.215 62.683 94.662 62.813 ;
     RECT  98.604 62.683 98.622 62.813 ;
     RECT  102.6 62.683 102.618 62.813 ;
     RECT  106.596 62.807 106.614 62.813 ;
     RECT  114.552 62.683 114.57 62.813 ;
     RECT  118.548 62.683 118.566 62.813 ;
     RECT  122.508 62.683 122.526 62.813 ;
     RECT  130.536 62.683 130.554 62.813 ;
     RECT  134.532 62.683 134.55 62.813 ;
     RECT  138.492 62.683 138.51 62.813 ;
     RECT  142.488 62.683 143.097 62.813 ;
     RECT  2.34 62.671 8.097 62.843 ;
     RECT  137.412 62.707 137.697 62.843 ;
     RECT  139.536 61.771 139.554 62.843 ;
     RECT  34.812 62.813 35.097 62.861 ;
     RECT  140.4 62.581 140.418 62.879 ;
     RECT  126.615 62.401 127.422 63.005 ;
     RECT  2.34 62.843 6.138 63.112 ;
     RECT  2.304 63.112 6.138 63.149 ;
     RECT  149.472 62.671 150.498 63.163 ;
     RECT  151.236 62.401 172.782 63.163 ;
     RECT  126.615 63.005 127.098 63.355 ;
     RECT  129.132 63.307 129.15 63.355 ;
     RECT  128.772 63.355 129.15 63.517 ;
     RECT  137.415 62.843 137.697 63.517 ;
     RECT  138.42 63.391 138.438 63.517 ;
     RECT  0.036 62.669 0.198 63.545 ;
     RECT  137.415 63.517 138.438 63.545 ;
     RECT  146.484 62.699 146.502 63.589 ;
     RECT  128.772 63.517 129.222 63.617 ;
     RECT  132.015 58.397 132.297 63.625 ;
     RECT  2.34 63.149 6.138 63.643 ;
     RECT  6.948 62.843 8.097 63.643 ;
     RECT  142.815 62.813 143.097 63.643 ;
     RECT  126.54 63.355 127.098 63.653 ;
     RECT  131.904 63.625 132.297 63.677 ;
     RECT  142.704 63.643 143.097 63.689 ;
     RECT  0.072 63.545 0.198 63.691 ;
     RECT  128.772 63.617 129.15 63.779 ;
     RECT  0.072 63.691 0.27 63.821 ;
     RECT  122.544 63.517 122.562 64.027 ;
     RECT  126.615 63.653 127.098 64.027 ;
     RECT  149.472 63.163 172.782 64.085 ;
     RECT  126.615 64.027 127.71 64.123 ;
     RECT  0.108 63.821 0.27 64.129 ;
     RECT  122.544 64.027 122.67 64.157 ;
     RECT  2.34 63.643 8.097 64.171 ;
     RECT  2.304 64.171 8.097 64.201 ;
     RECT  2.268 64.201 8.097 64.301 ;
     RECT  124.812 63.979 124.83 64.319 ;
     RECT  126.615 64.123 128.61 64.319 ;
     RECT  137.415 63.545 137.934 64.319 ;
     RECT  149.472 64.085 149.634 64.319 ;
     RECT  146.484 63.589 146.574 64.355 ;
     RECT  122.544 64.157 122.562 64.397 ;
     RECT  124.488 64.357 124.506 64.397 ;
     RECT  0.108 64.129 0.558 64.552 ;
     RECT  0.036 64.552 0.558 64.589 ;
     RECT  2.304 64.301 8.097 64.589 ;
     RECT  126.615 64.319 128.286 64.589 ;
     RECT  128.268 64.589 128.286 64.637 ;
     RECT  13.215 61.088 13.497 64.831 ;
     RECT  24.015 61.088 24.297 64.831 ;
     RECT  34.815 62.861 35.097 64.831 ;
     RECT  45.615 61.088 45.897 64.831 ;
     RECT  56.415 61.088 56.697 64.831 ;
     RECT  67.215 62.813 67.497 64.831 ;
     RECT  78.015 62.813 78.297 64.831 ;
     RECT  88.815 61.088 89.097 64.831 ;
     RECT  99.615 61.088 99.897 64.831 ;
     RECT  110.415 61.085 110.697 64.831 ;
     RECT  121.215 61.088 121.497 64.831 ;
     RECT  126.615 64.589 127.494 64.831 ;
     RECT  135.792 64.741 135.81 64.859 ;
     RECT  148.215 60.941 148.497 64.867 ;
     RECT  126.504 64.831 127.494 64.877 ;
     RECT  146.484 64.355 146.502 64.967 ;
     RECT  148.212 64.867 148.497 65.039 ;
     RECT  0.108 64.589 0.558 65.069 ;
     RECT  150.444 64.085 172.782 65.129 ;
     RECT  122.544 65.137 122.562 65.179 ;
     RECT  122.544 65.179 122.598 65.227 ;
     RECT  147.42 65.173 147.438 65.245 ;
     RECT  132.015 63.677 132.297 65.272 ;
     RECT  131.904 65.272 132.297 65.309 ;
     RECT  150.48 65.129 172.782 65.309 ;
     RECT  34.704 64.831 35.097 65.405 ;
     RECT  110.304 64.831 110.697 65.405 ;
     RECT  122.544 65.227 122.67 65.405 ;
     RECT  128.592 65.131 128.61 65.407 ;
     RECT  13.104 64.831 13.497 65.408 ;
     RECT  23.904 64.831 24.297 65.408 ;
     RECT  45.504 64.831 45.897 65.408 ;
     RECT  56.304 64.831 56.697 65.408 ;
     RECT  67.104 64.831 67.497 65.408 ;
     RECT  77.904 64.831 78.297 65.408 ;
     RECT  88.704 64.831 89.097 65.408 ;
     RECT  99.504 64.831 99.897 65.408 ;
     RECT  121.104 64.831 121.497 65.408 ;
     RECT  150.552 65.309 172.782 65.435 ;
     RECT  128.592 65.407 128.682 65.443 ;
     RECT  0.108 65.069 0.126 65.479 ;
     RECT  122.544 65.405 122.598 65.501 ;
     RECT  126.615 64.877 127.494 65.501 ;
     RECT  122.544 65.501 122.562 65.507 ;
     RECT  138.528 65.179 138.546 65.507 ;
     RECT  142.815 63.689 143.097 65.515 ;
     RECT  150.876 65.435 172.782 65.549 ;
     RECT  142.38 65.515 143.097 65.693 ;
     RECT  128.268 65.443 128.682 65.755 ;
     RECT  2.304 64.589 6.966 65.803 ;
     RECT  147.276 65.245 147.438 65.821 ;
     RECT  2.268 65.803 6.966 65.849 ;
     RECT  0.072 65.479 0.126 65.899 ;
     RECT  128.232 65.755 128.682 65.911 ;
     RECT  146.628 65.821 147.438 65.939 ;
     RECT  126.615 65.501 126.897 65.947 ;
     RECT  127.692 65.911 128.682 65.947 ;
     RECT  146.628 65.939 147.294 65.975 ;
     RECT  125.172 65.911 125.19 66.029 ;
     RECT  127.692 65.947 128.898 66.029 ;
     RECT  128.232 66.029 128.898 66.047 ;
     RECT  124.884 66.043 124.902 66.119 ;
     RECT  142.524 65.693 143.097 66.119 ;
     RECT  94.215 62.813 94.497 66.181 ;
     RECT  150.552 66.181 150.57 66.317 ;
     RECT  142.56 66.119 143.097 66.353 ;
     RECT  95.868 66.283 95.886 66.361 ;
     RECT  126.54 65.947 126.897 66.365 ;
     RECT  0.036 65.899 0.126 66.379 ;
     RECT  128.232 66.047 128.862 66.479 ;
     RECT  128.232 66.479 128.25 66.557 ;
     RECT  147.132 65.975 147.15 66.659 ;
     RECT  95.724 66.361 95.886 66.721 ;
     RECT  2.304 65.849 6.966 66.793 ;
     RECT  7.815 64.589 8.097 66.793 ;
     RECT  90.756 66.721 90.774 66.829 ;
     RECT  95.724 66.721 96.03 66.829 ;
     RECT  95.724 66.829 96.534 66.865 ;
     RECT  90.684 66.829 90.774 66.893 ;
     RECT  0.036 66.379 0.27 66.901 ;
     RECT  95.724 66.865 96.678 66.901 ;
     RECT  151.38 65.549 172.782 66.901 ;
     RECT  94.215 66.181 94.698 66.991 ;
     RECT  90.684 66.893 90.738 67.027 ;
     RECT  94.215 66.991 94.734 67.027 ;
     RECT  95.724 66.901 96.822 67.027 ;
     RECT  94.215 67.027 96.822 67.055 ;
     RECT  151.272 66.901 172.782 67.055 ;
     RECT  150.48 66.361 150.498 67.099 ;
     RECT  2.304 66.793 8.097 67.163 ;
     RECT  90.648 67.027 90.738 67.163 ;
     RECT  94.215 67.055 95.418 67.163 ;
     RECT  147.204 66.901 147.222 67.163 ;
     RECT  96.48 67.055 96.822 67.199 ;
     RECT  0.036 66.901 0.558 67.289 ;
     RECT  98.568 67.333 98.586 67.469 ;
     RECT  0.072 67.289 0.558 67.565 ;
     RECT  99.615 65.408 99.897 67.567 ;
     RECT  0.504 67.565 0.558 67.627 ;
     RECT  96.48 67.199 96.498 67.631 ;
     RECT  99.18 67.567 99.897 67.739 ;
     RECT  0.504 67.627 0.666 67.757 ;
     RECT  94.215 67.163 94.986 67.829 ;
     RECT  138.924 67.675 138.942 67.829 ;
     RECT  0.504 67.757 0.558 67.853 ;
     RECT  138.816 67.837 138.87 67.873 ;
     RECT  2.304 67.163 6.966 67.981 ;
     RECT  2.268 67.981 6.966 68.045 ;
     RECT  2.304 68.045 6.966 68.099 ;
     RECT  95.94 67.945 95.958 68.135 ;
     RECT  141.984 67.981 142.002 68.135 ;
     RECT  150.48 67.099 150.57 68.237 ;
     RECT  138.528 67.873 138.87 68.251 ;
     RECT  94.215 67.829 94.878 68.369 ;
     RECT  134.532 68.251 134.55 68.369 ;
     RECT  138.42 68.251 138.87 68.405 ;
     RECT  7.815 67.163 8.097 68.449 ;
     RECT  151.524 67.055 172.782 68.513 ;
     RECT  137.415 64.319 137.697 68.521 ;
     RECT  138.42 68.405 138.762 68.521 ;
     RECT  126.615 66.365 126.897 68.611 ;
     RECT  0.54 67.853 0.558 68.621 ;
     RECT  126.615 68.611 127.422 68.635 ;
     RECT  128.592 68.611 128.61 68.669 ;
     RECT  150.48 68.237 150.498 68.747 ;
     RECT  135.036 68.755 135.054 68.791 ;
     RECT  126.54 68.635 127.422 68.813 ;
     RECT  0.108 68.683 0.27 68.881 ;
     RECT  135.036 68.791 135.162 68.909 ;
     RECT  135.036 68.909 135.054 68.945 ;
     RECT  98.46 68.215 98.622 69.017 ;
     RECT  2.304 68.099 6.642 69.061 ;
     RECT  7.488 68.449 8.097 69.061 ;
     RECT  151.524 68.513 172.746 69.061 ;
     RECT  137.415 68.521 138.762 69.151 ;
     RECT  140.004 68.683 140.022 69.151 ;
     RECT  2.304 69.061 8.097 69.179 ;
     RECT  134.532 69.187 134.55 69.287 ;
     RECT  137.415 69.151 138.906 69.287 ;
     RECT  0.036 68.881 0.27 69.293 ;
     RECT  10.8 69.187 10.818 69.323 ;
     RECT  124.344 69.307 124.362 69.421 ;
     RECT  124.344 69.421 124.65 69.449 ;
     RECT  146.484 69.331 146.502 69.449 ;
     RECT  0.036 69.293 0.162 69.485 ;
     RECT  124.632 69.449 124.65 69.485 ;
     RECT  140.004 69.151 140.418 69.521 ;
     RECT  126.615 68.813 127.422 69.533 ;
     RECT  0.072 69.485 0.162 69.581 ;
     RECT  128.268 68.755 128.286 69.691 ;
     RECT  132.015 65.309 132.297 69.691 ;
     RECT  142.815 66.353 143.097 69.691 ;
     RECT  150.84 69.061 172.746 69.691 ;
     RECT  131.904 69.691 132.297 69.728 ;
     RECT  142.704 69.691 143.097 69.728 ;
     RECT  126.615 69.533 126.897 69.961 ;
     RECT  128.268 69.691 128.61 69.961 ;
     RECT  139.104 69.871 139.122 69.989 ;
     RECT  2.304 69.179 6.894 69.997 ;
     RECT  127.692 69.961 128.61 69.997 ;
     RECT  127.692 69.997 128.898 70.013 ;
     RECT  0.108 69.581 0.162 70.069 ;
     RECT  126.324 69.961 126.897 70.069 ;
     RECT  128.232 70.013 128.898 70.097 ;
     RECT  126 70.069 126.897 70.109 ;
     RECT  137.415 69.287 138.366 70.133 ;
     RECT  98.46 69.017 98.478 70.169 ;
     RECT  0.108 70.069 0.558 70.253 ;
     RECT  128.232 70.097 128.862 70.301 ;
     RECT  126.615 70.109 126.897 70.315 ;
     RECT  128.232 70.301 128.25 70.349 ;
     RECT  2.304 69.997 6.93 70.501 ;
     RECT  140.004 69.521 140.022 70.529 ;
     RECT  146.484 70.411 146.502 70.529 ;
     RECT  2.304 70.501 7.074 70.537 ;
     RECT  7.815 69.179 8.097 70.537 ;
     RECT  125.424 70.501 125.73 70.541 ;
     RECT  0.108 70.253 0.126 70.589 ;
     RECT  125.424 70.541 125.442 70.589 ;
     RECT  122.616 70.537 122.634 70.637 ;
     RECT  126.615 70.315 127.494 70.637 ;
     RECT  141.876 70.411 141.894 70.645 ;
     RECT  150.48 69.691 172.746 70.681 ;
     RECT  141.804 70.645 141.894 70.709 ;
     RECT  2.304 70.537 8.097 70.807 ;
     RECT  2.268 70.807 8.097 70.943 ;
     RECT  142.815 69.728 143.097 70.951 ;
     RECT  142.164 70.951 143.097 71.069 ;
     RECT  150.012 70.681 172.782 71.069 ;
     RECT  146.556 71.149 146.574 71.249 ;
     RECT  139.896 70.537 139.914 71.347 ;
     RECT  139.356 71.347 140.022 71.455 ;
     RECT  139.284 71.455 140.022 71.519 ;
     RECT  150.48 71.069 172.782 71.519 ;
     RECT  139.284 71.519 139.302 71.581 ;
     RECT  138.96 71.581 139.302 71.608 ;
     RECT  0.288 71.563 0.306 71.611 ;
     RECT  138.636 71.608 139.302 71.645 ;
     RECT  0.216 71.611 0.306 71.659 ;
     RECT  0.144 71.659 0.306 71.725 ;
     RECT  138.96 71.645 139.302 71.741 ;
     RECT  2.304 70.943 8.097 71.752 ;
     RECT  139.032 71.741 139.302 71.753 ;
     RECT  2.268 71.752 8.097 71.789 ;
     RECT  96.084 71.419 96.102 71.789 ;
     RECT  34.815 65.405 35.097 71.845 ;
     RECT  110.415 65.405 110.697 71.845 ;
     RECT  13.215 65.408 13.497 71.851 ;
     RECT  24.015 65.408 24.297 71.851 ;
     RECT  45.615 65.408 45.897 71.851 ;
     RECT  56.415 65.408 56.697 71.851 ;
     RECT  67.215 65.408 67.497 71.851 ;
     RECT  78.015 65.408 78.297 71.851 ;
     RECT  88.815 65.408 89.097 71.851 ;
     RECT  94.215 68.369 94.497 71.851 ;
     RECT  99.615 67.739 99.897 71.851 ;
     RECT  121.215 65.408 121.497 71.851 ;
     RECT  132.015 69.728 132.297 71.851 ;
     RECT  142.815 71.069 143.097 71.851 ;
     RECT  34.704 71.845 35.097 71.885 ;
     RECT  110.304 71.845 110.697 71.885 ;
     RECT  94.215 71.851 94.698 71.887 ;
     RECT  13.104 71.851 13.497 71.888 ;
     RECT  23.904 71.851 24.297 71.888 ;
     RECT  45.504 71.851 45.897 71.888 ;
     RECT  56.304 71.851 56.697 71.888 ;
     RECT  67.104 71.851 67.497 71.888 ;
     RECT  77.904 71.851 78.297 71.888 ;
     RECT  88.704 71.851 89.097 71.888 ;
     RECT  121.104 71.851 121.497 71.888 ;
     RECT  131.904 71.851 132.297 71.888 ;
     RECT  139.032 71.753 139.158 71.915 ;
     RECT  0.036 71.725 0.306 71.981 ;
     RECT  139.14 71.915 139.158 71.981 ;
     RECT  2.304 71.789 8.097 71.987 ;
     RECT  94.215 71.887 95.886 71.987 ;
     RECT  98.532 71.923 98.55 72.023 ;
     RECT  0.036 71.981 0.27 72.173 ;
     RECT  90.648 71.959 90.666 72.193 ;
     RECT  98.208 72.031 98.226 72.221 ;
     RECT  1.152 72.043 1.17 72.235 ;
     RECT  0.036 72.173 0.234 72.257 ;
     RECT  94.215 71.987 95.49 72.257 ;
     RECT  0.036 72.257 0.162 72.269 ;
     RECT  136.656 71.995 136.674 72.293 ;
     RECT  90.648 72.193 90.738 72.329 ;
     RECT  94.215 72.257 94.914 72.329 ;
     RECT  145.872 71.995 145.89 72.329 ;
     RECT  1.152 72.235 1.314 72.365 ;
     RECT  142.524 71.851 143.097 72.391 ;
     RECT  99.504 71.851 99.897 72.427 ;
     RECT  151.02 71.519 172.782 72.427 ;
     RECT  150.552 72.427 172.782 72.499 ;
     RECT  146.484 72.391 146.502 72.563 ;
     RECT  99.144 72.427 99.897 72.599 ;
     RECT  126.615 70.637 126.897 72.667 ;
     RECT  126.615 72.667 126.99 72.715 ;
     RECT  97.632 72.661 97.65 72.761 ;
     RECT  126.54 72.715 126.99 72.761 ;
     RECT  2.304 71.987 6.966 72.769 ;
     RECT  134.532 71.311 134.55 72.797 ;
     RECT  122.544 72.697 122.562 72.833 ;
     RECT  2.304 72.769 7.038 72.869 ;
     RECT  139.032 72.697 139.05 72.869 ;
     RECT  150.48 72.499 172.782 72.869 ;
     RECT  2.304 72.869 6.858 72.931 ;
     RECT  94.215 72.329 94.698 72.959 ;
     RECT  142.056 72.391 143.097 72.967 ;
     RECT  97.488 72.805 97.506 73.031 ;
     RECT  138.6 72.967 138.618 73.039 ;
     RECT  138.528 73.039 138.618 73.067 ;
     RECT  141.948 72.967 143.097 73.067 ;
     RECT  126.615 72.761 126.99 73.099 ;
     RECT  141.948 73.067 141.966 73.139 ;
     RECT  126.615 73.099 127.062 73.201 ;
     RECT  150.552 72.869 172.782 73.229 ;
     RECT  150.588 73.229 172.782 73.265 ;
     RECT  139.572 73.111 139.59 73.381 ;
     RECT  1.152 72.365 1.206 73.387 ;
     RECT  2.232 72.931 6.858 73.387 ;
     RECT  13.215 71.888 13.497 73.471 ;
     RECT  24.015 71.888 24.297 73.471 ;
     RECT  34.815 71.885 35.097 73.471 ;
     RECT  45.615 71.888 45.897 73.471 ;
     RECT  56.415 71.888 56.697 73.471 ;
     RECT  67.215 71.888 67.497 73.471 ;
     RECT  78.015 71.888 78.297 73.471 ;
     RECT  88.815 71.888 89.097 73.471 ;
     RECT  110.415 71.885 110.697 73.471 ;
     RECT  121.215 71.888 121.497 73.471 ;
     RECT  132.015 71.888 132.297 73.471 ;
     RECT  126.615 73.201 127.422 73.499 ;
     RECT  13.104 73.471 13.497 73.517 ;
     RECT  23.904 73.471 24.297 73.517 ;
     RECT  34.704 73.471 35.097 73.517 ;
     RECT  45.504 73.471 45.897 73.517 ;
     RECT  56.304 73.471 56.697 73.517 ;
     RECT  67.104 73.471 67.497 73.517 ;
     RECT  77.904 73.471 78.297 73.517 ;
     RECT  88.704 73.471 89.097 73.517 ;
     RECT  110.304 73.471 110.697 73.517 ;
     RECT  121.104 73.471 121.497 73.517 ;
     RECT  131.904 73.471 132.297 73.517 ;
     RECT  142.704 73.067 143.097 73.517 ;
     RECT  126.615 73.499 126.897 73.531 ;
     RECT  138.528 73.067 138.546 73.535 ;
     RECT  139.572 73.381 139.662 73.535 ;
     RECT  98.424 72.805 98.622 73.565 ;
     RECT  98.424 73.565 98.442 73.571 ;
     RECT  99.396 72.599 99.897 73.607 ;
     RECT  151.056 73.265 172.782 73.607 ;
     RECT  126.288 73.531 126.897 73.769 ;
     RECT  126.576 73.769 126.897 73.805 ;
     RECT  139.392 73.651 139.41 73.805 ;
     RECT  0.036 72.269 0.126 73.819 ;
     RECT  151.524 73.607 172.782 73.913 ;
     RECT  134.532 73.813 134.55 73.949 ;
     RECT  0.036 73.819 0.162 74.093 ;
     RECT  1.152 73.387 6.858 74.147 ;
     RECT  148.215 65.039 148.497 74.155 ;
     RECT  132.015 73.517 132.297 74.191 ;
     RECT  1.152 74.147 1.206 74.219 ;
     RECT  132.015 74.191 132.534 74.309 ;
     RECT  148.068 74.155 148.497 74.309 ;
     RECT  150.552 74.353 150.57 74.453 ;
     RECT  142.815 73.517 143.097 74.461 ;
     RECT  1.152 74.219 1.17 74.489 ;
     RECT  2.232 74.147 6.858 74.489 ;
     RECT  130.536 74.317 130.554 74.489 ;
     RECT  0.036 74.093 0.126 74.579 ;
     RECT  2.232 74.489 6.57 74.615 ;
     RECT  145.296 74.425 145.314 74.615 ;
     RECT  142.164 74.461 143.097 74.687 ;
     RECT  137.415 70.133 137.697 74.731 ;
     RECT  126.615 73.805 126.897 74.875 ;
     RECT  137.415 74.731 138.114 74.921 ;
     RECT  134.568 74.893 134.586 75.029 ;
     RECT  2.268 74.615 6.57 75.053 ;
     RECT  147.096 74.857 147.114 75.271 ;
     RECT  149.796 74.929 149.814 75.271 ;
     RECT  0.108 74.579 0.126 75.307 ;
     RECT  94.215 72.959 94.497 75.361 ;
     RECT  148.215 74.309 148.497 75.361 ;
     RECT  149.472 75.271 149.814 75.361 ;
     RECT  126.54 74.875 126.897 75.389 ;
     RECT  145.8 75.271 147.114 75.389 ;
     RECT  148.215 75.361 149.814 75.389 ;
     RECT  2.304 75.053 6.57 75.397 ;
     RECT  96.732 74.695 96.75 75.397 ;
     RECT  146.484 75.389 147.114 75.425 ;
     RECT  148.215 75.389 149.67 75.425 ;
     RECT  126.612 75.389 126.897 75.437 ;
     RECT  150.552 75.235 150.57 75.469 ;
     RECT  0.108 75.307 0.27 75.496 ;
     RECT  150.552 75.469 150.642 75.497 ;
     RECT  0.036 75.496 0.27 75.505 ;
     RECT  94.215 75.361 94.698 75.541 ;
     RECT  146.556 75.425 147.114 75.659 ;
     RECT  150.624 75.497 150.642 75.659 ;
     RECT  0.036 75.505 0.306 75.725 ;
     RECT  102.528 75.541 102.546 75.731 ;
     RECT  145.656 75.505 145.674 75.731 ;
     RECT  148.215 75.425 149.166 75.767 ;
     RECT  2.304 75.397 6.822 75.811 ;
     RECT  1.224 75.595 1.242 75.883 ;
     RECT  2.088 75.811 6.822 75.883 ;
     RECT  1.224 75.883 6.822 75.901 ;
     RECT  96.408 75.397 96.966 75.901 ;
     RECT  147.096 75.659 147.114 76.199 ;
     RECT  142.815 74.687 143.097 76.207 ;
     RECT  96.336 75.901 97.11 76.235 ;
     RECT  142.56 76.207 143.097 76.343 ;
     RECT  97.092 76.235 97.11 76.351 ;
     RECT  1.224 75.901 6.858 76.477 ;
     RECT  97.092 76.351 97.29 76.505 ;
     RECT  94.215 75.541 95.31 76.513 ;
     RECT  96.336 76.235 96.354 76.513 ;
     RECT  1.224 76.477 6.894 76.577 ;
     RECT  6.84 76.577 6.894 76.649 ;
     RECT  13.215 73.517 13.497 76.711 ;
     RECT  6.876 76.649 6.894 76.739 ;
     RECT  94.215 76.513 96.354 76.919 ;
     RECT  94.215 76.919 95.31 77.009 ;
     RECT  94.215 77.009 95.202 77.045 ;
     RECT  0.036 75.725 0.27 77.069 ;
     RECT  150.48 76.987 150.498 77.117 ;
     RECT  97.092 76.505 97.182 77.251 ;
     RECT  121.215 73.517 121.497 77.251 ;
     RECT  146.304 77.161 146.322 77.251 ;
     RECT  121.215 77.251 121.842 77.309 ;
     RECT  146.304 77.251 146.466 77.315 ;
     RECT  151.524 73.913 172.746 77.323 ;
     RECT  121.215 77.309 121.554 77.357 ;
     RECT  126.615 75.437 126.897 77.512 ;
     RECT  151.524 77.323 172.782 77.521 ;
     RECT  126 77.512 126.897 77.549 ;
     RECT  96.156 76.919 96.354 77.593 ;
     RECT  97.092 77.251 97.326 77.593 ;
     RECT  150.876 77.521 172.782 77.597 ;
     RECT  90.648 77.521 90.666 77.621 ;
     RECT  13.215 76.711 13.95 77.791 ;
     RECT  24.015 73.517 24.297 77.791 ;
     RECT  34.815 73.517 35.097 77.791 ;
     RECT  45.615 73.517 45.897 77.791 ;
     RECT  56.415 73.517 56.697 77.791 ;
     RECT  67.215 73.517 67.497 77.791 ;
     RECT  78.015 73.517 78.297 77.791 ;
     RECT  88.815 73.517 89.097 77.791 ;
     RECT  94.215 77.045 94.662 77.791 ;
     RECT  99.615 73.607 99.897 77.791 ;
     RECT  110.415 73.517 110.697 77.791 ;
     RECT  121.215 77.357 121.497 77.791 ;
     RECT  0.108 77.069 0.126 77.803 ;
     RECT  126.324 77.549 126.897 77.837 ;
     RECT  1.224 76.577 6.03 77.851 ;
     RECT  98.676 77.665 98.694 77.854 ;
     RECT  94.215 77.791 94.698 77.927 ;
     RECT  0.108 77.803 0.306 77.933 ;
     RECT  98.676 77.854 98.73 77.963 ;
     RECT  0.108 77.933 0.234 77.971 ;
     RECT  96.156 77.593 97.326 77.971 ;
     RECT  0.036 77.971 0.234 77.999 ;
     RECT  0.036 77.999 0.162 78.029 ;
     RECT  94.215 77.927 94.662 78.089 ;
     RECT  34.704 77.791 35.097 78.365 ;
     RECT  110.304 77.791 110.697 78.365 ;
     RECT  13.104 77.791 13.95 78.368 ;
     RECT  23.904 77.791 24.297 78.368 ;
     RECT  45.504 77.791 45.897 78.368 ;
     RECT  56.304 77.791 56.697 78.368 ;
     RECT  67.104 77.791 67.497 78.368 ;
     RECT  77.904 77.791 78.297 78.368 ;
     RECT  88.704 77.791 89.097 78.368 ;
     RECT  99.504 77.791 99.897 78.368 ;
     RECT  121.104 77.791 121.497 78.368 ;
     RECT  124.02 78.331 124.326 78.368 ;
     RECT  124.02 78.368 124.038 78.413 ;
     RECT  122.616 78.367 122.634 78.467 ;
     RECT  125.208 78.367 125.226 78.467 ;
     RECT  98.568 78.367 98.658 78.503 ;
     RECT  146.448 77.315 146.466 78.511 ;
     RECT  150.012 78.475 150.03 78.511 ;
     RECT  98.64 78.503 98.658 78.629 ;
     RECT  150.012 78.511 150.21 78.664 ;
     RECT  146.448 78.511 146.574 78.665 ;
     RECT  149.868 78.664 150.21 78.669 ;
     RECT  149.868 78.669 150.174 78.701 ;
     RECT  146.448 78.665 146.502 78.773 ;
     RECT  150.156 78.701 150.174 78.773 ;
     RECT  95.904 77.971 97.326 78.971 ;
     RECT  1.152 77.851 6.03 79.169 ;
     RECT  20.52 78.943 20.538 79.349 ;
     RECT  1.152 79.169 4.914 79.439 ;
     RECT  6.012 79.169 6.03 79.483 ;
     RECT  96.336 78.971 97.326 79.511 ;
     RECT  124.236 79.243 124.254 79.681 ;
     RECT  124.236 79.681 124.866 79.709 ;
     RECT  124.848 79.709 124.866 79.757 ;
     RECT  6.012 79.483 6.282 79.781 ;
     RECT  6.264 79.781 6.282 80.059 ;
     RECT  96.336 79.511 96.354 80.087 ;
     RECT  146.448 78.773 146.466 80.123 ;
     RECT  6.264 80.059 6.318 80.159 ;
     RECT  63.54 77.899 63.558 80.393 ;
     RECT  1.152 79.439 4.41 80.491 ;
     RECT  97.2 79.511 97.326 80.663 ;
     RECT  1.152 80.491 4.59 80.671 ;
     RECT  1.152 80.671 5.022 80.699 ;
     RECT  97.2 80.663 97.218 80.699 ;
     RECT  124.236 80.923 124.254 81.067 ;
     RECT  1.404 80.699 5.022 81.131 ;
     RECT  4.536 81.131 5.022 81.167 ;
     RECT  13.215 78.368 13.95 81.211 ;
     RECT  13.215 81.211 14.274 81.239 ;
     RECT  124.236 81.067 124.866 81.329 ;
     RECT  1.404 81.131 3.69 81.599 ;
     RECT  14.256 81.239 14.274 81.671 ;
     RECT  1.404 81.599 3.546 81.941 ;
     RECT  1.404 81.941 3.474 82.139 ;
     RECT  4.536 81.167 4.554 82.211 ;
     RECT  1.404 82.139 3.402 82.247 ;
     RECT  6.3 80.159 6.318 82.319 ;
     RECT  2.088 82.247 3.402 82.409 ;
     RECT  13.215 81.239 13.497 82.651 ;
     RECT  24.015 78.368 24.297 82.651 ;
     RECT  34.815 78.365 35.097 82.651 ;
     RECT  45.615 78.368 45.897 82.651 ;
     RECT  56.415 78.368 56.697 82.651 ;
     RECT  67.215 78.368 67.497 82.651 ;
     RECT  78.015 78.368 78.297 82.651 ;
     RECT  88.815 78.368 89.097 82.651 ;
     RECT  99.615 78.368 99.897 82.651 ;
     RECT  110.415 78.365 110.697 82.651 ;
     RECT  121.215 78.368 121.497 82.651 ;
     RECT  2.415 82.409 3.402 82.688 ;
     RECT  13.104 82.651 13.497 82.688 ;
     RECT  23.904 82.651 24.297 82.688 ;
     RECT  34.704 82.651 35.097 82.688 ;
     RECT  45.504 82.651 45.897 82.688 ;
     RECT  56.304 82.651 56.697 82.688 ;
     RECT  67.104 82.651 67.497 82.688 ;
     RECT  77.904 82.651 78.297 82.688 ;
     RECT  88.704 82.651 89.097 82.688 ;
     RECT  99.504 82.651 99.897 82.688 ;
     RECT  110.304 82.651 110.697 82.688 ;
     RECT  121.104 82.651 121.497 82.688 ;
     RECT  2.415 82.688 3.294 82.859 ;
     RECT  125.136 82.651 125.154 82.939 ;
     RECT  124.812 82.939 125.154 82.949 ;
     RECT  124.812 82.949 124.83 82.985 ;
     RECT  126.615 77.837 126.897 84.955 ;
     RECT  2.415 82.859 2.697 85.351 ;
     RECT  3.636 85.261 3.654 85.351 ;
     RECT  126.615 84.955 127.17 85.351 ;
     RECT  4.5 85.261 4.518 85.379 ;
     RECT  126.615 85.351 127.458 85.421 ;
     RECT  2.415 85.351 3.654 85.459 ;
     RECT  2.415 85.459 4.194 85.469 ;
     RECT  2.415 85.469 2.697 86.161 ;
     RECT  2.34 86.161 2.697 86.341 ;
     RECT  60.624 82.021 60.642 86.369 ;
     RECT  2.304 86.341 2.898 86.611 ;
     RECT  1.98 86.611 2.898 86.729 ;
     RECT  3.636 85.469 4.194 86.881 ;
     RECT  3.636 86.881 4.266 86.909 ;
     RECT  3.852 86.909 4.266 87.413 ;
     RECT  3.852 87.413 4.23 87.575 ;
     RECT  83.415 2.413 83.697 87.781 ;
     RECT  83.412 87.781 83.697 87.835 ;
     RECT  3.852 87.575 4.086 87.845 ;
     RECT  83.34 87.835 83.697 87.881 ;
     RECT  3.852 87.845 3.87 87.917 ;
     RECT  83.412 87.881 83.697 87.965 ;
     RECT  151.524 77.597 172.782 104.573 ;
     RECT  151.524 104.573 155.43 106.493 ;
     RECT  151.524 106.493 155.358 106.877 ;
     RECT  151.524 106.877 155.322 107.117 ;
     RECT  151.524 107.117 153.897 107.885 ;
     RECT  151.776 107.885 153.897 108.365 ;
     RECT  151.776 108.365 152.658 108.413 ;
     RECT  152.1 108.413 152.658 108.461 ;
     RECT  152.64 108.461 152.658 108.653 ;
     RECT  156.42 104.573 172.782 108.989 ;
     RECT  1.98 86.729 2.697 109.469 ;
     RECT  157.032 108.989 172.782 110.333 ;
     RECT  158.184 110.333 172.782 112.493 ;
     RECT  154.728 107.117 155.322 112.541 ;
     RECT  158.364 112.493 172.782 113.549 ;
     RECT  157.032 110.333 157.086 113.837 ;
     RECT  154.728 112.541 154.854 114.077 ;
     RECT  154.836 114.077 154.854 114.125 ;
     RECT  158.364 113.549 160.398 114.413 ;
     RECT  161.172 113.549 172.782 114.611 ;
     RECT  157.032 113.837 157.05 114.653 ;
     RECT  158.364 114.413 159.39 114.701 ;
     RECT  158.364 114.701 159.297 114.893 ;
     RECT  161.172 114.611 172.746 115.037 ;
     RECT  161.172 115.037 172.71 115.901 ;
     RECT  161.568 115.901 172.71 116.041 ;
     RECT  161.568 116.041 172.746 116.573 ;
     RECT  161.568 116.573 163.422 117.341 ;
     RECT  163.404 117.341 163.422 117.629 ;
     RECT  164.415 116.573 172.746 117.725 ;
     RECT  160.38 114.413 160.398 118.397 ;
     RECT  164.415 117.725 172.674 118.733 ;
     RECT  167.436 118.733 172.674 118.741 ;
     RECT  164.415 118.733 166.23 119.165 ;
     RECT  164.415 119.165 165.222 119.309 ;
     RECT  167.436 118.741 172.746 119.357 ;
     RECT  167.436 119.357 172.674 119.453 ;
     RECT  161.568 117.341 162.63 119.789 ;
     RECT  167.436 119.453 167.454 120.029 ;
     RECT  168.732 119.453 172.674 120.091 ;
     RECT  161.568 119.789 161.874 120.221 ;
     RECT  168.732 120.091 172.746 120.365 ;
     RECT  162.612 119.789 162.63 120.893 ;
     RECT  169.056 120.365 172.746 121.019 ;
     RECT  169.056 121.019 172.674 121.277 ;
     RECT  164.415 119.309 164.697 121.432 ;
     RECT  161.568 120.221 161.658 121.469 ;
     RECT  164.304 121.432 164.697 121.469 ;
     RECT  166.212 119.165 166.23 121.949 ;
     RECT  169.056 121.277 172.602 122.045 ;
     RECT  169.056 122.045 171.918 122.141 ;
     RECT  161.64 121.469 161.658 122.189 ;
     RECT  169.815 122.141 171.918 122.237 ;
     RECT  169.056 122.141 169.074 122.429 ;
     RECT  169.815 122.237 170.838 122.525 ;
     RECT  172.656 122.155 172.674 122.587 ;
     RECT  172.656 122.587 172.746 122.639 ;
     RECT  172.656 122.639 172.674 122.669 ;
     RECT  170.82 122.525 170.838 122.717 ;
     RECT  171.9 122.237 171.918 126.749 ;
     RECT  2.415 109.469 2.697 127.187 ;
     RECT  7.815 71.987 8.097 127.187 ;
     RECT  13.215 82.688 13.497 127.187 ;
     RECT  18.615 62.813 18.897 127.187 ;
     RECT  24.015 82.688 24.297 127.187 ;
     RECT  29.415 62.807 29.697 127.187 ;
     RECT  34.815 82.688 35.097 127.187 ;
     RECT  40.215 2.413 40.497 127.187 ;
     RECT  45.615 82.688 45.897 127.187 ;
     RECT  51.015 62.813 51.297 127.187 ;
     RECT  56.415 82.688 56.697 127.187 ;
     RECT  61.815 2.413 62.097 127.187 ;
     RECT  67.215 82.688 67.497 127.187 ;
     RECT  72.615 2.413 72.897 127.187 ;
     RECT  78.015 82.688 78.297 127.187 ;
     RECT  83.415 87.965 83.697 127.187 ;
     RECT  88.815 82.688 89.097 127.187 ;
     RECT  94.215 78.089 94.497 127.187 ;
     RECT  99.615 82.688 99.897 127.187 ;
     RECT  105.015 2.413 105.297 127.187 ;
     RECT  110.415 82.688 110.697 127.187 ;
     RECT  115.815 2.413 116.097 127.187 ;
     RECT  121.215 82.688 121.497 127.187 ;
     RECT  126.615 85.421 126.897 127.187 ;
     RECT  132.015 74.309 132.297 127.187 ;
     RECT  137.415 74.921 137.697 127.187 ;
     RECT  142.815 76.343 143.097 127.187 ;
     RECT  148.215 75.767 148.497 127.187 ;
     RECT  153.615 108.365 153.897 127.187 ;
     RECT  159.015 114.893 159.297 127.187 ;
     RECT  164.415 121.469 164.697 127.187 ;
     RECT  169.815 122.525 170.097 127.187 ;
     RECT  2.415 127.187 2.505 127.457 ;
     RECT  7.815 127.187 7.905 127.457 ;
     RECT  13.215 127.187 13.305 127.457 ;
     RECT  18.615 127.187 18.705 127.457 ;
     RECT  24.015 127.187 24.105 127.457 ;
     RECT  29.415 127.187 29.505 127.457 ;
     RECT  34.815 127.187 34.905 127.457 ;
     RECT  40.215 127.187 40.305 127.457 ;
     RECT  45.615 127.187 45.705 127.457 ;
     RECT  51.015 127.187 51.105 127.457 ;
     RECT  56.415 127.187 56.505 127.457 ;
     RECT  61.815 127.187 61.905 127.457 ;
     RECT  67.215 127.187 67.305 127.457 ;
     RECT  72.615 127.187 72.705 127.457 ;
     RECT  78.015 127.187 78.105 127.457 ;
     RECT  83.415 127.187 83.505 127.457 ;
     RECT  88.815 127.187 88.905 127.457 ;
     RECT  94.215 127.187 94.305 127.457 ;
     RECT  99.615 127.187 99.705 127.457 ;
     RECT  105.015 127.187 105.105 127.457 ;
     RECT  110.415 127.187 110.505 127.457 ;
     RECT  115.815 127.187 115.905 127.457 ;
     RECT  121.215 127.187 121.305 127.457 ;
     RECT  126.615 127.187 126.705 127.457 ;
     RECT  132.015 127.187 132.105 127.457 ;
     RECT  137.415 127.187 137.505 127.457 ;
     RECT  142.815 127.187 142.905 127.457 ;
     RECT  148.215 127.187 148.305 127.457 ;
     RECT  153.615 127.187 153.705 127.457 ;
     RECT  159.015 127.187 159.105 127.457 ;
     RECT  164.415 127.187 164.505 127.457 ;
     RECT  169.815 127.187 169.905 127.457 ;
    LAYER M4 ;
     RECT  0.012 40.32 0.065 40.344 ;
     RECT  0.012 112.32 0.227 112.344 ;
     RECT  0.012 51.408 2.293 78.12 ;
     RECT  2.293 51.408 2.408 78.168 ;
     RECT  2.293 79.44 2.408 80.856 ;
     RECT  0.012 86.4 2.408 86.424 ;
     RECT  0.181 87.84 2.408 87.864 ;
     RECT  0.012 109.44 2.408 109.464 ;
     RECT  2.408 2.148 2.512 127.452 ;
     RECT  2.512 2.418 2.704 127.182 ;
     RECT  2.704 80.832 2.765 81.528 ;
     RECT  2.704 79.008 2.819 79.848 ;
     RECT  2.819 79.728 2.845 79.848 ;
     RECT  2.704 49.728 2.867 77.688 ;
     RECT  2.867 49.728 2.945 77.64 ;
     RECT  2.945 49.728 3.053 77.4 ;
     RECT  3.053 51.408 3.521 77.4 ;
     RECT  2.765 80.928 3.673 81.528 ;
     RECT  3.521 52.464 4.025 77.4 ;
     RECT  4.025 54.384 4.061 77.4 ;
     RECT  2.704 48.144 4.237 48.168 ;
     RECT  4.025 52.464 4.277 53.4 ;
     RECT  2.845 79.728 4.381 79.752 ;
     RECT  3.673 80.928 4.381 81.096 ;
     RECT  4.061 54.432 4.385 71.16 ;
     RECT  4.061 72.432 4.501 77.4 ;
     RECT  4.277 52.464 4.529 53.352 ;
     RECT  4.381 79.728 4.547 81.096 ;
     RECT  4.529 52.464 4.565 53.256 ;
     RECT  4.385 54.432 4.565 66.024 ;
     RECT  4.501 72.432 4.601 78.36 ;
     RECT  4.385 67.008 4.637 71.16 ;
     RECT  3.053 49.728 4.669 50.28 ;
     RECT  3.521 51.408 4.669 51.432 ;
     RECT  4.565 55.68 4.673 66.024 ;
     RECT  4.637 67.008 4.781 70.968 ;
     RECT  4.781 67.248 4.817 70.968 ;
     RECT  4.817 68.016 5.213 70.968 ;
     RECT  4.601 72.432 5.245 74.328 ;
     RECT  5.245 72.384 5.249 74.328 ;
     RECT  5.213 68.688 5.465 70.968 ;
     RECT  4.673 55.968 5.537 66.024 ;
     RECT  5.537 55.968 5.645 60.888 ;
     RECT  5.465 68.688 5.681 70.632 ;
     RECT  5.249 72.384 5.753 73.656 ;
     RECT  5.537 61.872 6.217 66.024 ;
     RECT  5.785 67.152 6.217 67.704 ;
     RECT  6.217 61.872 6.289 67.704 ;
     RECT  5.681 68.688 6.289 70.536 ;
     RECT  6.289 61.872 6.293 70.536 ;
     RECT  5.753 72.816 6.433 73.656 ;
     RECT  6.289 71.712 6.721 71.736 ;
     RECT  6.433 72.816 6.721 73.848 ;
     RECT  4.565 54.576 6.829 54.6 ;
     RECT  6.293 67.68 6.865 70.536 ;
     RECT  6.721 71.712 6.865 73.848 ;
     RECT  5.645 55.968 7.009 60.792 ;
     RECT  7.009 55.968 7.189 60.888 ;
     RECT  6.293 61.872 7.189 66.264 ;
     RECT  4.237 48.096 7.808 48.168 ;
     RECT  4.669 49.728 7.808 51.432 ;
     RECT  4.565 52.704 7.808 53.256 ;
     RECT  6.829 54.576 7.808 54.84 ;
     RECT  7.189 55.968 7.808 66.264 ;
     RECT  6.865 67.68 7.808 73.848 ;
     RECT  4.601 75.408 7.808 75.432 ;
     RECT  4.601 76.992 7.808 78.36 ;
     RECT  4.547 79.728 7.808 79.752 ;
     RECT  4.547 81.072 7.808 81.096 ;
     RECT  2.704 82.656 7.808 82.68 ;
     RECT  2.704 85.392 7.808 85.464 ;
     RECT  2.704 87.84 7.808 87.864 ;
     RECT  7.808 2.148 7.912 127.452 ;
     RECT  7.912 2.418 8.104 127.182 ;
     RECT  8.104 48.096 13.208 48.168 ;
     RECT  8.104 49.728 13.208 51.432 ;
     RECT  8.104 52.704 13.208 53.256 ;
     RECT  8.104 54.576 13.208 54.6 ;
     RECT  8.104 55.968 13.208 66.264 ;
     RECT  8.104 67.68 13.208 73.848 ;
     RECT  8.104 75.408 13.208 75.432 ;
     RECT  8.104 76.992 13.208 78.36 ;
     RECT  8.104 79.728 13.208 79.752 ;
     RECT  8.104 81.072 13.208 81.096 ;
     RECT  8.104 82.656 13.208 82.68 ;
     RECT  8.104 85.392 13.208 85.464 ;
     RECT  8.104 87.84 13.208 87.864 ;
     RECT  13.208 2.148 13.312 127.452 ;
     RECT  13.312 2.418 13.504 127.182 ;
     RECT  13.504 48.096 18.608 48.168 ;
     RECT  13.504 49.728 18.608 51.432 ;
     RECT  13.504 52.704 18.608 53.256 ;
     RECT  13.504 54.576 18.608 54.6 ;
     RECT  13.504 55.968 18.608 66.264 ;
     RECT  13.504 67.68 18.608 73.848 ;
     RECT  13.504 75.408 18.608 75.432 ;
     RECT  13.504 76.992 18.608 78.36 ;
     RECT  13.504 79.728 18.608 79.752 ;
     RECT  13.504 81.072 18.608 81.096 ;
     RECT  13.504 82.656 18.608 82.68 ;
     RECT  13.504 85.392 18.608 85.464 ;
     RECT  13.504 87.84 18.608 87.864 ;
     RECT  18.608 2.148 18.712 127.452 ;
     RECT  18.712 2.418 18.904 127.182 ;
     RECT  18.904 48.096 24.008 48.168 ;
     RECT  18.904 49.728 24.008 51.432 ;
     RECT  18.904 52.704 24.008 53.256 ;
     RECT  18.904 54.576 24.008 54.6 ;
     RECT  18.904 55.968 24.008 66.264 ;
     RECT  18.904 67.68 24.008 73.848 ;
     RECT  18.904 75.408 24.008 75.432 ;
     RECT  18.904 76.992 24.008 78.36 ;
     RECT  18.904 79.728 24.008 79.752 ;
     RECT  18.904 81.072 24.008 81.096 ;
     RECT  18.904 82.656 24.008 82.68 ;
     RECT  18.904 85.392 24.008 85.464 ;
     RECT  18.904 87.84 24.008 87.864 ;
     RECT  24.008 2.148 24.112 127.452 ;
     RECT  24.112 2.418 24.304 127.182 ;
     RECT  24.304 48.096 29.408 48.168 ;
     RECT  24.304 49.728 29.408 51.432 ;
     RECT  24.304 52.704 29.408 53.256 ;
     RECT  24.304 54.576 29.408 54.6 ;
     RECT  24.304 55.968 29.408 66.264 ;
     RECT  24.304 67.68 29.408 73.848 ;
     RECT  24.304 75.408 29.408 75.432 ;
     RECT  24.304 76.992 29.408 78.36 ;
     RECT  24.304 79.728 29.408 79.752 ;
     RECT  24.304 81.072 29.408 81.096 ;
     RECT  24.304 82.656 29.408 82.68 ;
     RECT  24.304 85.392 29.408 85.464 ;
     RECT  24.304 87.84 29.408 87.864 ;
     RECT  29.408 2.148 29.512 127.452 ;
     RECT  29.512 2.418 29.704 127.182 ;
     RECT  29.704 48.096 34.808 48.168 ;
     RECT  29.704 49.728 34.808 51.432 ;
     RECT  29.704 52.704 34.808 53.256 ;
     RECT  29.704 54.576 34.808 54.6 ;
     RECT  29.704 55.968 34.808 66.264 ;
     RECT  29.704 67.68 34.808 73.848 ;
     RECT  29.704 75.408 34.808 75.432 ;
     RECT  29.704 76.992 34.808 78.36 ;
     RECT  29.704 79.728 34.808 79.752 ;
     RECT  29.704 81.072 34.808 81.096 ;
     RECT  29.704 82.656 34.808 82.68 ;
     RECT  29.704 85.392 34.808 85.464 ;
     RECT  29.704 87.84 34.808 87.864 ;
     RECT  34.808 2.148 34.912 127.452 ;
     RECT  34.912 2.418 35.104 127.182 ;
     RECT  35.104 48.096 40.208 48.168 ;
     RECT  35.104 49.728 40.208 51.432 ;
     RECT  35.104 52.704 40.208 53.256 ;
     RECT  35.104 54.576 40.208 54.6 ;
     RECT  35.104 55.968 40.208 66.264 ;
     RECT  35.104 67.68 40.208 73.848 ;
     RECT  35.104 75.408 40.208 75.432 ;
     RECT  35.104 76.992 40.208 78.36 ;
     RECT  35.104 79.728 40.208 79.752 ;
     RECT  35.104 81.072 40.208 81.096 ;
     RECT  35.104 82.656 40.208 82.68 ;
     RECT  35.104 85.392 40.208 85.464 ;
     RECT  35.104 87.84 40.208 87.864 ;
     RECT  40.208 2.148 40.312 127.452 ;
     RECT  40.312 2.418 40.504 127.182 ;
     RECT  40.504 48.096 45.608 48.168 ;
     RECT  40.504 49.728 45.608 51.432 ;
     RECT  40.504 52.704 45.608 53.256 ;
     RECT  40.504 54.576 45.608 54.6 ;
     RECT  40.504 55.968 45.608 66.264 ;
     RECT  40.504 67.68 45.608 73.848 ;
     RECT  40.504 75.408 45.608 75.432 ;
     RECT  40.504 76.992 45.608 78.36 ;
     RECT  40.504 79.728 45.608 79.752 ;
     RECT  40.504 81.072 45.608 81.096 ;
     RECT  40.504 82.656 45.608 82.68 ;
     RECT  40.504 85.392 45.608 85.464 ;
     RECT  40.504 87.84 45.608 87.864 ;
     RECT  45.608 2.148 45.712 127.452 ;
     RECT  45.712 2.418 45.904 127.182 ;
     RECT  45.904 48.096 51.008 48.168 ;
     RECT  45.904 49.728 51.008 51.432 ;
     RECT  45.904 52.704 51.008 53.256 ;
     RECT  45.904 54.576 51.008 54.6 ;
     RECT  45.904 55.968 51.008 66.264 ;
     RECT  45.904 67.68 51.008 73.848 ;
     RECT  45.904 75.408 51.008 75.432 ;
     RECT  45.904 76.992 51.008 78.36 ;
     RECT  45.904 79.728 51.008 79.752 ;
     RECT  45.904 81.072 51.008 81.096 ;
     RECT  45.904 82.656 51.008 82.68 ;
     RECT  45.904 85.392 51.008 85.464 ;
     RECT  45.904 87.84 51.008 87.864 ;
     RECT  51.008 2.148 51.112 127.452 ;
     RECT  51.112 2.418 51.304 127.182 ;
     RECT  51.304 48.096 56.408 48.168 ;
     RECT  51.304 49.728 56.408 51.432 ;
     RECT  51.304 52.704 56.408 53.256 ;
     RECT  51.304 54.576 56.408 54.6 ;
     RECT  51.304 55.968 56.408 66.264 ;
     RECT  51.304 67.68 56.408 73.848 ;
     RECT  51.304 75.408 56.408 75.432 ;
     RECT  51.304 76.992 56.408 78.36 ;
     RECT  51.304 79.728 56.408 79.752 ;
     RECT  51.304 81.072 56.408 81.096 ;
     RECT  51.304 82.656 56.408 82.68 ;
     RECT  51.304 85.392 56.408 85.464 ;
     RECT  51.304 87.84 56.408 87.864 ;
     RECT  56.408 2.148 56.512 127.452 ;
     RECT  56.512 2.418 56.704 127.182 ;
     RECT  56.704 48.096 61.808 48.168 ;
     RECT  56.704 49.728 61.808 51.432 ;
     RECT  56.704 52.704 61.808 53.256 ;
     RECT  56.704 54.576 61.808 54.6 ;
     RECT  56.704 55.968 61.808 66.264 ;
     RECT  56.704 67.68 61.808 73.848 ;
     RECT  56.704 75.408 61.808 75.432 ;
     RECT  56.704 76.992 61.808 78.36 ;
     RECT  56.704 79.728 61.808 79.752 ;
     RECT  56.704 81.072 61.808 81.096 ;
     RECT  56.704 82.656 61.808 82.68 ;
     RECT  56.704 85.392 61.808 85.464 ;
     RECT  56.704 87.84 61.808 87.864 ;
     RECT  61.808 2.148 61.912 127.452 ;
     RECT  61.912 2.418 62.104 127.182 ;
     RECT  62.104 48.096 67.208 48.168 ;
     RECT  62.104 49.728 67.208 51.432 ;
     RECT  62.104 52.704 67.208 53.256 ;
     RECT  62.104 54.576 67.208 54.6 ;
     RECT  62.104 55.968 67.208 66.264 ;
     RECT  62.104 67.68 67.208 73.848 ;
     RECT  62.104 75.408 67.208 75.432 ;
     RECT  62.104 76.992 67.208 78.36 ;
     RECT  62.104 79.728 67.208 79.752 ;
     RECT  62.104 81.072 67.208 81.096 ;
     RECT  62.104 82.656 67.208 82.68 ;
     RECT  62.104 85.392 67.208 85.464 ;
     RECT  62.104 87.84 67.208 87.864 ;
     RECT  67.208 2.148 67.312 127.452 ;
     RECT  67.312 2.418 67.504 127.182 ;
     RECT  67.504 48.096 72.608 48.168 ;
     RECT  67.504 49.728 72.608 51.432 ;
     RECT  67.504 52.704 72.608 53.256 ;
     RECT  67.504 54.576 72.608 54.6 ;
     RECT  67.504 55.968 72.608 66.264 ;
     RECT  67.504 67.68 72.608 73.848 ;
     RECT  67.504 75.408 72.608 75.432 ;
     RECT  67.504 76.992 72.608 78.36 ;
     RECT  67.504 79.728 72.608 79.752 ;
     RECT  67.504 81.072 72.608 81.096 ;
     RECT  67.504 82.656 72.608 82.68 ;
     RECT  67.504 85.392 72.608 85.464 ;
     RECT  67.504 87.84 72.608 87.864 ;
     RECT  72.608 2.148 72.712 127.452 ;
     RECT  72.712 2.418 72.904 127.182 ;
     RECT  72.904 48.096 78.008 48.168 ;
     RECT  72.904 49.728 78.008 51.432 ;
     RECT  72.904 52.704 78.008 53.256 ;
     RECT  72.904 54.576 78.008 54.6 ;
     RECT  72.904 55.968 78.008 66.264 ;
     RECT  72.904 67.68 78.008 73.848 ;
     RECT  72.904 75.408 78.008 75.432 ;
     RECT  72.904 76.992 78.008 78.36 ;
     RECT  72.904 79.728 78.008 79.752 ;
     RECT  72.904 81.072 78.008 81.096 ;
     RECT  72.904 82.656 78.008 82.68 ;
     RECT  72.904 85.392 78.008 85.464 ;
     RECT  72.904 87.84 78.008 87.864 ;
     RECT  78.008 2.148 78.112 127.452 ;
     RECT  78.112 2.418 78.304 127.182 ;
     RECT  78.304 87.84 83.221 87.864 ;
     RECT  78.304 48.096 83.408 48.168 ;
     RECT  78.304 49.728 83.408 51.432 ;
     RECT  78.304 52.704 83.408 53.256 ;
     RECT  78.304 54.576 83.408 54.6 ;
     RECT  78.304 55.968 83.408 66.264 ;
     RECT  78.304 67.68 83.408 73.848 ;
     RECT  78.304 75.408 83.408 75.432 ;
     RECT  78.304 76.992 83.408 78.36 ;
     RECT  78.304 79.728 83.408 79.752 ;
     RECT  78.304 81.072 83.408 81.096 ;
     RECT  78.304 82.656 83.408 82.68 ;
     RECT  78.304 85.392 83.408 85.464 ;
     RECT  83.221 87.84 83.408 87.96 ;
     RECT  83.408 2.148 83.512 127.452 ;
     RECT  83.512 2.418 83.704 127.182 ;
     RECT  83.704 48.096 88.808 48.168 ;
     RECT  83.704 49.728 88.808 51.432 ;
     RECT  83.704 52.704 88.808 53.256 ;
     RECT  83.704 54.576 88.808 54.6 ;
     RECT  83.704 55.968 88.808 66.264 ;
     RECT  83.704 67.68 88.808 73.848 ;
     RECT  83.704 75.408 88.808 75.432 ;
     RECT  83.704 76.992 88.808 78.36 ;
     RECT  83.704 79.728 88.808 79.752 ;
     RECT  83.704 81.072 88.808 81.096 ;
     RECT  83.704 82.656 88.808 82.68 ;
     RECT  83.704 85.392 88.808 85.464 ;
     RECT  88.808 2.148 88.912 127.452 ;
     RECT  88.912 2.418 89.104 127.182 ;
     RECT  89.104 48.096 94.208 48.168 ;
     RECT  89.104 49.728 94.208 51.432 ;
     RECT  89.104 52.704 94.208 53.256 ;
     RECT  89.104 54.576 94.208 54.6 ;
     RECT  89.104 55.968 94.208 66.264 ;
     RECT  89.104 67.68 94.208 73.848 ;
     RECT  89.104 75.408 94.208 75.432 ;
     RECT  89.104 76.992 94.208 78.36 ;
     RECT  89.104 79.728 94.208 79.752 ;
     RECT  89.104 81.072 94.208 81.096 ;
     RECT  89.104 82.656 94.208 82.68 ;
     RECT  89.104 85.392 94.208 85.464 ;
     RECT  94.208 2.148 94.312 127.452 ;
     RECT  94.312 2.418 94.504 127.182 ;
     RECT  94.504 52.704 97.585 53.256 ;
     RECT  94.504 49.728 97.693 51.432 ;
     RECT  97.585 52.704 97.693 53.592 ;
     RECT  97.693 49.728 98.341 53.592 ;
     RECT  94.504 54.576 98.341 54.6 ;
     RECT  94.504 48.096 99.608 48.168 ;
     RECT  98.341 49.728 99.608 54.6 ;
     RECT  94.504 55.968 99.608 73.848 ;
     RECT  94.504 75.408 99.608 75.432 ;
     RECT  94.504 76.848 99.608 78.36 ;
     RECT  94.504 79.728 99.608 79.752 ;
     RECT  94.504 81.072 99.608 81.096 ;
     RECT  94.504 82.656 99.608 82.68 ;
     RECT  94.504 85.392 99.608 85.464 ;
     RECT  99.608 2.148 99.712 127.452 ;
     RECT  99.712 2.418 99.904 127.182 ;
     RECT  99.904 48.096 105.008 48.168 ;
     RECT  99.904 49.728 105.008 54.6 ;
     RECT  99.904 55.968 105.008 73.848 ;
     RECT  99.904 75.408 105.008 75.432 ;
     RECT  99.904 76.848 105.008 78.36 ;
     RECT  99.904 79.728 105.008 79.752 ;
     RECT  99.904 81.072 105.008 81.096 ;
     RECT  99.904 82.656 105.008 82.68 ;
     RECT  99.904 85.392 105.008 85.464 ;
     RECT  105.008 2.148 105.112 127.452 ;
     RECT  105.112 2.418 105.304 127.182 ;
     RECT  105.304 48.096 110.408 48.168 ;
     RECT  105.304 49.728 110.408 54.6 ;
     RECT  105.304 55.968 110.408 73.848 ;
     RECT  105.304 75.408 110.408 75.432 ;
     RECT  105.304 76.848 110.408 78.36 ;
     RECT  105.304 79.728 110.408 79.752 ;
     RECT  105.304 81.072 110.408 81.096 ;
     RECT  105.304 82.656 110.408 82.68 ;
     RECT  105.304 85.392 110.408 85.464 ;
     RECT  110.408 2.148 110.512 127.452 ;
     RECT  110.512 2.418 110.704 127.182 ;
     RECT  110.704 48.096 115.808 48.168 ;
     RECT  110.704 49.728 115.808 54.6 ;
     RECT  110.704 55.968 115.808 73.848 ;
     RECT  110.704 75.408 115.808 75.432 ;
     RECT  110.704 76.848 115.808 78.36 ;
     RECT  110.704 79.728 115.808 79.752 ;
     RECT  110.704 81.072 115.808 81.096 ;
     RECT  110.704 82.656 115.808 82.68 ;
     RECT  110.704 85.392 115.808 85.464 ;
     RECT  115.808 2.148 115.912 127.452 ;
     RECT  115.912 2.418 116.104 127.182 ;
     RECT  116.104 48.096 121.208 48.168 ;
     RECT  116.104 49.728 121.208 54.6 ;
     RECT  116.104 55.968 121.208 73.848 ;
     RECT  116.104 75.408 121.208 75.432 ;
     RECT  116.104 76.848 121.208 78.36 ;
     RECT  116.104 79.728 121.208 79.752 ;
     RECT  116.104 81.072 121.208 81.096 ;
     RECT  116.104 82.656 121.208 82.68 ;
     RECT  116.104 85.392 121.208 85.464 ;
     RECT  121.208 2.148 121.312 127.452 ;
     RECT  121.312 2.418 121.504 127.182 ;
     RECT  121.504 76.848 124.009 78.36 ;
     RECT  121.504 75.408 124.165 75.432 ;
     RECT  124.009 76.848 124.165 78.408 ;
     RECT  121.504 79.728 124.165 79.752 ;
     RECT  121.504 81.072 124.181 81.096 ;
     RECT  124.165 75.408 124.265 79.752 ;
     RECT  124.181 80.928 124.265 81.096 ;
     RECT  121.504 49.728 124.741 54.6 ;
     RECT  121.504 48.096 124.789 48.168 ;
     RECT  121.504 82.656 124.801 82.68 ;
     RECT  124.789 48.096 124.876 48.312 ;
     RECT  121.504 55.968 124.877 73.848 ;
     RECT  124.265 79.728 124.877 79.752 ;
     RECT  124.265 81.072 124.877 81.096 ;
     RECT  124.801 82.656 125.165 82.968 ;
     RECT  124.876 48.096 125.953 48.168 ;
     RECT  124.265 75.408 126.529 78.408 ;
     RECT  125.953 48.096 126.608 48.456 ;
     RECT  124.741 49.728 126.608 54.984 ;
     RECT  124.877 56.304 126.608 73.848 ;
     RECT  126.529 74.88 126.608 78.408 ;
     RECT  125.165 82.944 126.608 82.968 ;
     RECT  121.504 85.392 126.608 85.464 ;
     RECT  126.608 2.148 126.712 127.452 ;
     RECT  126.712 2.418 126.904 127.182 ;
     RECT  126.904 84.96 127.225 85.464 ;
     RECT  127.225 85.392 127.469 85.464 ;
     RECT  126.904 50.592 132.008 54.984 ;
     RECT  126.904 56.208 132.008 73.896 ;
     RECT  126.904 74.88 132.008 74.904 ;
     RECT  126.904 75.936 132.008 78.408 ;
     RECT  126.904 82.944 132.008 82.968 ;
     RECT  127.469 85.44 132.008 85.464 ;
     RECT  132.008 2.148 132.112 127.452 ;
     RECT  132.112 2.418 132.304 127.182 ;
     RECT  132.304 50.592 137.408 54.984 ;
     RECT  132.304 56.208 137.408 73.896 ;
     RECT  132.304 74.88 137.408 74.904 ;
     RECT  132.304 75.936 137.408 78.408 ;
     RECT  132.304 82.944 137.408 82.968 ;
     RECT  132.304 85.44 137.408 85.464 ;
     RECT  137.408 2.148 137.512 127.452 ;
     RECT  137.512 2.418 137.704 127.182 ;
     RECT  137.704 50.592 142.808 54.984 ;
     RECT  137.704 56.208 142.808 73.896 ;
     RECT  137.704 74.88 142.808 74.904 ;
     RECT  137.704 75.936 142.808 78.408 ;
     RECT  137.704 82.944 142.808 82.968 ;
     RECT  137.704 85.44 142.808 85.464 ;
     RECT  142.808 2.148 142.912 127.452 ;
     RECT  142.912 2.418 143.104 127.182 ;
     RECT  143.104 50.592 148.208 54.984 ;
     RECT  143.104 56.208 148.208 73.896 ;
     RECT  143.104 74.88 148.208 74.904 ;
     RECT  143.104 75.936 148.208 78.408 ;
     RECT  143.104 82.944 148.208 82.968 ;
     RECT  143.104 85.44 148.208 85.464 ;
     RECT  148.208 2.148 148.312 127.452 ;
     RECT  148.312 2.418 148.504 127.182 ;
     RECT  148.504 75.936 149.857 78.408 ;
     RECT  149.857 75.936 150.149 78.696 ;
     RECT  148.504 50.592 150.509 54.984 ;
     RECT  150.149 75.936 150.905 78.408 ;
     RECT  151.513 107.856 151.765 107.88 ;
     RECT  148.504 56.208 151.837 73.896 ;
     RECT  148.504 74.88 151.837 74.904 ;
     RECT  151.765 107.856 152.089 108.408 ;
     RECT  150.509 50.592 152.525 54.888 ;
     RECT  152.089 107.856 152.629 108.456 ;
     RECT  152.557 17.952 152.845 17.976 ;
     RECT  152.845 17.952 152.917 18.264 ;
     RECT  152.629 107.856 153.061 108.648 ;
     RECT  151.837 56.208 153.169 74.904 ;
     RECT  152.269 24.912 153.241 24.936 ;
     RECT  152.525 51.744 153.349 54.888 ;
     RECT  153.169 56.016 153.349 74.904 ;
     RECT  153.169 13.584 153.608 13.608 ;
     RECT  152.917 17.952 153.608 18.84 ;
     RECT  153.241 24.384 153.608 24.936 ;
     RECT  152.525 50.592 153.608 50.616 ;
     RECT  153.349 51.744 153.608 74.904 ;
     RECT  150.905 75.936 153.608 77.352 ;
     RECT  150.905 78.384 153.608 78.408 ;
     RECT  148.504 82.944 153.608 82.968 ;
     RECT  148.504 85.44 153.608 85.464 ;
     RECT  153.061 107.52 153.608 108.648 ;
     RECT  153.608 2.148 153.712 127.452 ;
     RECT  153.712 2.418 153.904 127.182 ;
     RECT  153.904 75.936 154.835 78.552 ;
     RECT  153.904 85.44 154.835 85.464 ;
     RECT  154.835 75.936 154.901 78.504 ;
     RECT  153.904 12 154.933 12.024 ;
     RECT  153.904 13.152 154.933 13.464 ;
     RECT  153.904 22.272 155.149 24.936 ;
     RECT  153.904 51.744 155.149 74.904 ;
     RECT  154.901 75.936 155.149 76.872 ;
     RECT  153.904 106.704 155.401 108.6 ;
     RECT  155.437 98.16 155.653 98.184 ;
     RECT  153.904 50.592 155.987 50.616 ;
     RECT  153.904 8.16 156.085 8.184 ;
     RECT  155.149 51.744 156.337 76.872 ;
     RECT  154.901 77.952 156.337 78.504 ;
     RECT  155.401 106.464 156.409 108.6 ;
     RECT  155.653 97.632 156.445 98.184 ;
     RECT  153.904 20.064 156.805 20.088 ;
     RECT  156.085 8.16 156.949 8.28 ;
     RECT  154.933 12 157.021 13.464 ;
     RECT  155.905 14.448 157.021 14.472 ;
     RECT  153.904 114.048 157.021 114.12 ;
     RECT  155.905 104.544 157.045 104.568 ;
     RECT  157.021 114.048 157.057 114.648 ;
     RECT  153.904 82.944 157.187 82.968 ;
     RECT  156.445 97.584 157.237 98.184 ;
     RECT  157.045 103.824 157.597 104.568 ;
     RECT  157.165 102.384 157.633 102.408 ;
     RECT  157.237 97.536 157.741 98.184 ;
     RECT  157.021 12 158.029 14.472 ;
     RECT  157.633 102.384 158.101 102.696 ;
     RECT  155.293 112.512 158.173 112.536 ;
     RECT  157.741 97.536 158.197 98.472 ;
     RECT  157.561 110.304 158.281 110.328 ;
     RECT  157.057 113.808 158.353 114.648 ;
     RECT  158.101 102.384 158.389 102.792 ;
     RECT  156.949 8.064 158.461 8.28 ;
     RECT  156.409 106.464 158.713 108.984 ;
     RECT  158.281 110.064 158.713 110.328 ;
     RECT  158.461 7.968 159.008 8.28 ;
     RECT  158.029 11.952 159.008 14.472 ;
     RECT  155.941 16.608 159.008 16.632 ;
     RECT  153.904 17.952 159.008 18.84 ;
     RECT  156.805 19.872 159.008 20.088 ;
     RECT  155.149 22.272 159.008 25.176 ;
     RECT  156.337 51.744 159.008 78.504 ;
     RECT  158.197 96.576 159.008 98.472 ;
     RECT  158.389 102.144 159.008 102.792 ;
     RECT  157.597 103.824 159.008 104.664 ;
     RECT  158.713 106.464 159.008 110.328 ;
     RECT  158.173 112.464 159.008 112.536 ;
     RECT  158.353 113.808 159.008 114.888 ;
     RECT  159.008 2.148 159.112 127.452 ;
     RECT  159.112 2.418 159.304 127.182 ;
     RECT  159.304 11.952 159.401 14.472 ;
     RECT  159.304 80.112 160.163 80.136 ;
     RECT  159.304 46.752 160.229 46.776 ;
     RECT  159.304 17.952 160.405 18.84 ;
     RECT  159.304 19.872 160.405 20.088 ;
     RECT  159.304 6.816 160.441 6.84 ;
     RECT  159.304 7.968 160.441 8.28 ;
     RECT  159.304 96.576 160.549 98.472 ;
     RECT  159.304 106.464 160.693 110.808 ;
     RECT  159.304 51.744 160.697 78.504 ;
     RECT  160.697 51.744 160.837 74.232 ;
     RECT  160.697 75.264 160.837 78.504 ;
     RECT  160.405 17.952 160.945 20.088 ;
     RECT  159.304 113.808 160.945 114.984 ;
     RECT  160.837 75.264 161.053 79.08 ;
     RECT  160.837 51.6 161.089 74.232 ;
     RECT  159.304 102.144 161.089 102.792 ;
     RECT  159.304 103.824 161.089 104.664 ;
     RECT  159.304 22.176 161.161 25.176 ;
     RECT  160.945 113.52 161.161 114.984 ;
     RECT  159.304 16.608 161.341 16.632 ;
     RECT  160.945 17.952 161.341 20.472 ;
     RECT  160.621 27.36 161.377 27.384 ;
     RECT  161.089 51.456 161.417 74.232 ;
     RECT  161.417 51.456 161.561 68.904 ;
     RECT  159.304 32.064 161.629 32.088 ;
     RECT  161.557 121.44 161.629 121.464 ;
     RECT  159.304 112.464 161.701 112.536 ;
     RECT  161.161 113.52 161.701 115.896 ;
     RECT  161.665 82.608 161.777 82.632 ;
     RECT  161.161 22.176 161.809 25.56 ;
     RECT  160.441 6.816 162.205 8.28 ;
     RECT  161.845 120.192 162.241 120.216 ;
     RECT  159.401 11.952 162.349 14.376 ;
     RECT  161.417 70.08 162.349 74.232 ;
     RECT  161.053 75.264 162.349 79.176 ;
     RECT  161.089 102.144 162.385 104.664 ;
     RECT  161.341 16.608 162.421 20.472 ;
     RECT  162.349 70.08 162.461 79.176 ;
     RECT  161.809 22.176 162.601 25.608 ;
     RECT  161.561 51.6 162.601 68.904 ;
     RECT  162.241 119.76 162.601 120.216 ;
     RECT  161.629 121.44 162.601 122.184 ;
     RECT  162.601 51.6 162.673 69 ;
     RECT  159.304 100.512 162.673 100.536 ;
     RECT  162.385 101.664 162.673 104.664 ;
     RECT  162.673 51.6 162.853 69.096 ;
     RECT  162.461 70.08 162.853 79.128 ;
     RECT  162.781 86.592 162.865 86.616 ;
     RECT  162.853 51.6 162.965 79.128 ;
     RECT  162.965 51.6 162.988 79.08 ;
     RECT  162.817 49.104 163.001 49.128 ;
     RECT  162.529 28.8 163.213 28.824 ;
     RECT  161.701 112.464 163.357 115.896 ;
     RECT  163.321 117.312 163.393 117.336 ;
     RECT  160.369 118.368 163.393 118.392 ;
     RECT  162.349 11.952 163.501 14.712 ;
     RECT  162.988 51.6 163.501 69.048 ;
     RECT  161.377 27.072 163.537 27.384 ;
     RECT  163.213 28.416 163.537 28.824 ;
     RECT  162.421 16.512 163.645 20.472 ;
     RECT  163.645 15.936 163.681 20.472 ;
     RECT  162.673 100.512 163.717 104.664 ;
     RECT  163.681 15.84 163.753 20.472 ;
     RECT  160.693 106.32 163.789 110.808 ;
     RECT  163.357 112.464 163.789 116.28 ;
     RECT  163.753 15.792 163.969 20.472 ;
     RECT  162.601 22.176 163.969 26.088 ;
     RECT  163.789 106.32 164.041 116.28 ;
     RECT  163.393 117.312 164.041 118.392 ;
     RECT  163.501 51.168 164.213 69.048 ;
     RECT  162.988 70.08 164.401 79.08 ;
     RECT  162.205 6.816 164.408 8.568 ;
     RECT  163.429 9.84 164.408 9.864 ;
     RECT  163.501 11.232 164.408 14.712 ;
     RECT  163.969 15.792 164.408 26.088 ;
     RECT  163.537 27.072 164.408 28.824 ;
     RECT  162.133 30.096 164.408 30.12 ;
     RECT  161.629 31.2 164.408 32.088 ;
     RECT  164.213 50.736 164.408 69.048 ;
     RECT  164.401 70.08 164.408 79.224 ;
     RECT  164.185 80.64 164.408 80.664 ;
     RECT  163.069 81.744 164.408 81.768 ;
     RECT  164.077 88.32 164.408 88.344 ;
     RECT  160.549 96.576 164.408 98.712 ;
     RECT  163.717 100.224 164.408 104.664 ;
     RECT  164.041 106.32 164.408 118.392 ;
     RECT  162.601 119.76 164.408 122.184 ;
     RECT  164.408 2.148 164.512 127.452 ;
     RECT  164.512 2.418 164.704 127.182 ;
     RECT  164.704 51.12 164.729 69.048 ;
     RECT  164.729 51.12 164.837 68.712 ;
     RECT  164.704 70.608 164.909 80.952 ;
     RECT  164.909 70.608 165.017 73.272 ;
     RECT  164.909 74.64 165.017 80.952 ;
     RECT  164.837 51.696 165.053 68.712 ;
     RECT  165.017 77.424 165.269 80.952 ;
     RECT  165.017 70.704 165.305 73.272 ;
     RECT  165.269 77.424 165.388 80.136 ;
     RECT  165.053 51.744 165.557 68.712 ;
     RECT  165.305 70.704 165.593 72.984 ;
     RECT  165.557 51.744 165.629 63.096 ;
     RECT  165.629 60.336 165.737 63.096 ;
     RECT  165.593 72.768 165.773 72.984 ;
     RECT  164.704 82.56 165.773 82.584 ;
     RECT  165.697 49.008 165.845 49.032 ;
     RECT  164.704 100.224 166.021 104.952 ;
     RECT  164.704 105.984 166.021 122.184 ;
     RECT  165.017 74.64 166.057 76.296 ;
     RECT  165.388 77.424 166.057 79.56 ;
     RECT  165.629 51.744 166.061 59.304 ;
     RECT  165.949 69.696 166.097 69.72 ;
     RECT  164.704 6.144 166.165 8.712 ;
     RECT  166.057 74.64 166.201 79.56 ;
     RECT  165.593 70.704 166.205 71.64 ;
     RECT  166.021 100.224 166.237 122.184 ;
     RECT  164.704 31.2 166.357 32.088 ;
     RECT  164.704 9.84 166.381 9.864 ;
     RECT  166.201 74.592 166.417 79.56 ;
     RECT  166.093 49.056 166.421 49.08 ;
     RECT  166.165 6.048 166.489 8.712 ;
     RECT  165.557 64.08 166.489 68.712 ;
     RECT  166.417 74.304 166.489 79.896 ;
     RECT  165.773 72.816 166.493 72.984 ;
     RECT  166.061 51.744 166.499 54.696 ;
     RECT  166.493 72.912 166.525 72.984 ;
     RECT  166.489 74.112 166.525 79.896 ;
     RECT  164.704 96.576 166.525 98.712 ;
     RECT  166.453 80.88 166.537 81.528 ;
     RECT  166.525 72.912 166.604 79.896 ;
     RECT  166.537 80.88 166.604 81.048 ;
     RECT  166.604 72.912 166.717 81.048 ;
     RECT  166.489 64.08 166.813 69.24 ;
     RECT  166.717 72.912 166.817 80.424 ;
     RECT  165.737 60.336 166.885 63 ;
     RECT  166.813 64.032 166.885 69.24 ;
     RECT  166.525 96.576 166.885 98.76 ;
     RECT  166.237 99.744 166.885 122.184 ;
     RECT  166.885 60.336 166.979 69.24 ;
     RECT  166.061 56.352 166.997 59.304 ;
     RECT  166.979 64.032 167.069 69.24 ;
     RECT  166.205 70.704 167.101 71.4 ;
     RECT  166.817 73.632 167.177 80.424 ;
     RECT  166.499 51.744 167.209 54.408 ;
     RECT  164.704 30.096 167.269 30.12 ;
     RECT  166.997 56.736 167.281 59.304 ;
     RECT  166.979 60.336 167.281 63.048 ;
     RECT  167.101 70.272 167.281 71.4 ;
     RECT  166.381 9.84 167.353 10.104 ;
     RECT  164.704 11.136 167.353 28.824 ;
     RECT  167.209 51.168 167.425 54.408 ;
     RECT  167.281 70.176 167.425 71.4 ;
     RECT  167.353 9.84 167.461 28.824 ;
     RECT  167.269 29.808 167.461 30.12 ;
     RECT  167.425 51.072 167.461 54.408 ;
     RECT  166.489 6.048 167.497 8.856 ;
     RECT  167.461 9.84 167.497 30.12 ;
     RECT  166.597 42.72 167.573 42.744 ;
     RECT  166.885 96.576 167.797 122.184 ;
     RECT  167.497 6.048 168.037 30.12 ;
     RECT  166.357 31.2 168.037 32.232 ;
     RECT  167.461 51.072 168.073 54.696 ;
     RECT  168.037 55.68 168.073 55.704 ;
     RECT  167.281 56.736 168.073 63.048 ;
     RECT  167.069 64.032 168.073 69.096 ;
     RECT  167.177 73.632 168.113 80.328 ;
     RECT  168.073 51.072 168.14 55.704 ;
     RECT  168.037 6.048 168.181 32.328 ;
     RECT  168.145 86.784 168.181 86.808 ;
     RECT  168.073 56.736 168.217 69.096 ;
     RECT  167.425 70.176 168.217 71.496 ;
     RECT  168.113 74.256 168.277 80.328 ;
     RECT  168.277 74.256 168.289 80.856 ;
     RECT  168.289 74.256 168.323 80.952 ;
     RECT  168.323 80.832 168.401 80.952 ;
     RECT  168.217 56.736 168.689 71.496 ;
     RECT  168.689 56.736 168.761 64.968 ;
     RECT  168.761 56.736 168.797 63.816 ;
     RECT  168.14 50.784 168.829 55.704 ;
     RECT  167.797 96.576 168.997 122.664 ;
     RECT  168.829 50.736 169.081 55.704 ;
     RECT  168.797 56.736 169.081 59.88 ;
     RECT  168.323 74.256 169.297 79.512 ;
     RECT  169.297 74.256 169.333 80.376 ;
     RECT  169.333 73.296 169.369 80.376 ;
     RECT  169.369 73.296 169.429 80.712 ;
     RECT  169.429 73.296 169.525 80.952 ;
     RECT  168.689 66.096 169.549 71.496 ;
     RECT  168.997 96.528 169.621 122.664 ;
     RECT  167.857 2.88 169.808 2.904 ;
     RECT  168.181 6 169.808 32.328 ;
     RECT  168.505 38.736 169.808 38.76 ;
     RECT  169.081 50.736 169.808 59.88 ;
     RECT  168.797 60.96 169.808 63.816 ;
     RECT  168.761 64.944 169.808 64.968 ;
     RECT  169.549 66.096 169.808 71.928 ;
     RECT  169.525 73.296 169.808 81 ;
     RECT  168.793 82.608 169.808 82.632 ;
     RECT  168.181 86.64 169.808 86.808 ;
     RECT  169.621 96.192 169.808 122.664 ;
     RECT  169.808 2.148 169.912 127.452 ;
     RECT  169.912 2.418 170.104 127.182 ;
     RECT  170.104 76.56 170.201 79.224 ;
     RECT  170.104 52.272 170.291 53.016 ;
     RECT  170.104 54.144 170.309 55.56 ;
     RECT  170.201 76.608 170.309 78.984 ;
     RECT  170.309 54.144 170.339 54.168 ;
     RECT  170.104 67.824 170.339 70.392 ;
     RECT  170.104 50.736 170.381 50.76 ;
     RECT  170.339 69.552 170.387 70.392 ;
     RECT  170.291 52.992 170.435 53.016 ;
     RECT  170.104 61.008 170.435 61.032 ;
     RECT  170.104 5.76 170.453 32.472 ;
     RECT  170.104 56.736 170.675 59.928 ;
     RECT  170.104 62.208 170.723 65.592 ;
     RECT  170.723 62.448 170.741 65.592 ;
     RECT  170.675 58.128 170.771 59.928 ;
     RECT  170.771 58.128 170.819 59.784 ;
     RECT  170.104 46.128 170.867 46.728 ;
     RECT  170.104 71.904 170.867 71.928 ;
     RECT  170.339 67.824 170.929 68.424 ;
     RECT  170.104 74.688 170.963 74.712 ;
     RECT  170.929 68.4 171.011 68.424 ;
     RECT  170.104 94.656 171.011 94.68 ;
     RECT  170.741 62.544 171.037 65.592 ;
     RECT  170.104 96.192 171.277 122.712 ;
     RECT  170.819 58.128 171.299 59.592 ;
     RECT  171.037 62.544 171.299 64.2 ;
     RECT  171.299 58.128 171.347 59.544 ;
     RECT  171.037 65.52 171.395 65.592 ;
     RECT  171.299 62.736 171.443 64.2 ;
     RECT  170.387 70.368 171.443 70.392 ;
     RECT  170.104 38.736 171.491 38.76 ;
     RECT  170.867 46.128 171.565 46.152 ;
     RECT  171.565 45.552 171.587 46.152 ;
     RECT  171.443 64.176 171.587 64.2 ;
     RECT  170.453 5.76 171.709 32.376 ;
     RECT  171.529 70.656 171.875 70.68 ;
     RECT  170.309 76.608 171.923 77.88 ;
     RECT  170.675 56.736 171.971 56.76 ;
     RECT  171.923 77.52 171.971 77.88 ;
     RECT  171.347 58.704 172.019 59.544 ;
     RECT  170.309 78.96 172.019 78.984 ;
     RECT  171.601 42.72 172.067 42.744 ;
     RECT  170.104 66.768 172.069 66.792 ;
     RECT  171.587 45.552 172.115 45.576 ;
     RECT  171.601 84.96 172.115 84.984 ;
     RECT  172.069 66.768 172.285 67.272 ;
     RECT  171.395 65.52 172.403 65.544 ;
     RECT  172.285 66.672 172.451 67.272 ;
     RECT  170.104 86.88 172.451 86.904 ;
     RECT  172.249 37.008 172.499 37.032 ;
     RECT  171.443 62.736 172.499 63.048 ;
     RECT  172.213 68.928 172.547 68.952 ;
     RECT  171.971 77.856 172.547 77.88 ;
     RECT  172.499 62.976 172.573 63.048 ;
     RECT  170.309 55.536 172.595 55.56 ;
     RECT  172.573 62.976 172.595 63.288 ;
     RECT  172.177 90.048 172.643 90.072 ;
     RECT  172.595 63.264 172.657 63.288 ;
     RECT  172.019 58.704 172.685 58.728 ;
     RECT  172.451 66.672 172.685 66.792 ;
     RECT  172.685 66.768 172.691 66.792 ;
     RECT  171.097 88.368 172.691 88.392 ;
     RECT  170.104 2.88 172.8 2.904 ;
     RECT  171.709 5.76 172.8 32.472 ;
     RECT  172.717 73.44 172.8 73.56 ;
     RECT  171.277 96 172.8 122.712 ;
     RECT  171.889 126.72 172.8 126.744 ;
    LAYER M5 ;
     RECT  2.4 2.137 2.52 2.151 ;
     RECT  7.8 2.137 7.92 2.151 ;
     RECT  13.2 2.137 13.32 2.151 ;
     RECT  18.6 2.137 18.72 2.151 ;
     RECT  24 2.137 24.12 2.151 ;
     RECT  29.4 2.137 29.52 2.151 ;
     RECT  34.8 2.137 34.92 2.151 ;
     RECT  40.2 2.137 40.32 2.151 ;
     RECT  45.6 2.137 45.72 2.151 ;
     RECT  51 2.137 51.12 2.151 ;
     RECT  56.4 2.137 56.52 2.151 ;
     RECT  61.8 2.137 61.92 2.151 ;
     RECT  67.2 2.137 67.32 2.151 ;
     RECT  72.6 2.137 72.72 2.151 ;
     RECT  78 2.137 78.12 2.151 ;
     RECT  83.4 2.137 83.52 2.151 ;
     RECT  88.8 2.137 88.92 2.151 ;
     RECT  94.2 2.137 94.32 2.151 ;
     RECT  99.6 2.137 99.72 2.151 ;
     RECT  105 2.137 105.12 2.151 ;
     RECT  110.4 2.137 110.52 2.151 ;
     RECT  115.8 2.137 115.92 2.151 ;
     RECT  121.2 2.137 121.32 2.151 ;
     RECT  126.6 2.137 126.72 2.151 ;
     RECT  132 2.137 132.12 2.151 ;
     RECT  137.4 2.137 137.52 2.151 ;
     RECT  142.8 2.137 142.92 2.151 ;
     RECT  148.2 2.137 148.32 2.151 ;
     RECT  153.6 2.137 153.72 2.151 ;
     RECT  159 2.137 159.12 2.151 ;
     RECT  164.4 2.137 164.52 2.151 ;
     RECT  169.8 2.137 169.92 2.151 ;
     RECT  171.552 14.581 171.576 15.253 ;
     RECT  171.456 15.253 171.576 17.077 ;
     RECT  171.456 17.077 172.536 17.173 ;
     RECT  171.456 17.173 172.632 17.219 ;
     RECT  172.56 17.219 172.632 17.651 ;
     RECT  169.8 2.151 170.112 17.653 ;
     RECT  169.536 17.653 170.112 18.037 ;
     RECT  171.456 17.219 171.576 18.037 ;
     RECT  172.56 17.651 172.584 18.179 ;
     RECT  169.536 18.037 171.576 19.093 ;
     RECT  169.536 19.093 171.96 19.477 ;
     RECT  169.536 19.477 172.632 21.589 ;
     RECT  169.536 21.589 172.68 21.733 ;
     RECT  169.392 21.733 172.68 22.019 ;
     RECT  164.4 2.151 164.712 27.157 ;
     RECT  164.4 27.157 164.808 27.347 ;
     RECT  169.488 22.019 172.68 28.789 ;
     RECT  169.344 28.789 172.68 28.979 ;
     RECT  166.704 17.941 166.728 29.797 ;
     RECT  167.76 19.813 167.784 29.797 ;
     RECT  166.704 29.797 167.784 30.373 ;
     RECT  166.704 30.373 168.072 31.669 ;
     RECT  166.416 31.669 168.072 32.197 ;
     RECT  126.6 2.151 126.912 48.421 ;
     RECT  2.4 2.151 2.712 50.245 ;
     RECT  124.8 48.277 124.824 50.677 ;
     RECT  164.4 27.347 164.712 50.725 ;
     RECT  166.368 32.197 168.072 50.773 ;
     RECT  166.368 50.773 168.216 50.821 ;
     RECT  169.488 28.979 172.68 50.821 ;
     RECT  2.4 50.245 2.808 50.965 ;
     RECT  126 48.421 126.912 51.157 ;
     RECT  2.4 50.965 3 51.539 ;
     RECT  160.848 51.589 160.872 51.781 ;
     RECT  126 51.157 127.032 52.211 ;
     RECT  160.848 51.781 161.4 52.405 ;
     RECT  164.256 50.725 164.712 52.453 ;
     RECT  153.6 2.151 153.912 52.741 ;
     RECT  160.848 52.405 162.36 52.741 ;
     RECT  124.752 50.677 124.824 52.787 ;
     RECT  155.952 50.581 155.976 52.885 ;
     RECT  160.848 52.741 163.224 52.933 ;
     RECT  164.256 52.453 164.808 52.933 ;
     RECT  126 52.211 126.912 53.027 ;
     RECT  150.48 52.693 150.504 53.027 ;
     RECT  155.808 52.885 156.456 53.027 ;
     RECT  159 2.151 159.312 53.029 ;
     RECT  160.848 52.933 164.808 53.029 ;
     RECT  155.952 53.027 156.456 53.269 ;
     RECT  166.368 50.821 172.68 53.315 ;
     RECT  159 53.029 164.808 53.365 ;
     RECT  155.952 53.269 156.792 53.555 ;
     RECT  158.208 53.365 164.808 53.557 ;
     RECT  166.416 53.315 172.68 53.651 ;
     RECT  158.208 53.557 165.288 53.699 ;
     RECT  126.048 53.027 126.912 53.843 ;
     RECT  162.336 53.699 165.288 54.083 ;
     RECT  98.352 52.885 98.376 54.131 ;
     RECT  166.464 53.651 172.68 54.227 ;
     RECT  124.752 52.787 124.776 54.661 ;
     RECT  0.144 54.421 0.168 54.707 ;
     RECT  166.464 54.227 168.264 54.707 ;
     RECT  155.952 53.555 155.976 54.947 ;
     RECT  124.752 54.661 125.304 54.995 ;
     RECT  158.208 53.699 161.304 55.045 ;
     RECT  162.336 54.083 164.712 55.045 ;
     RECT  158.208 55.045 164.712 55.187 ;
     RECT  153.6 52.741 154.056 55.237 ;
     RECT  164.208 55.187 164.712 55.331 ;
     RECT  167.28 54.707 168.168 55.427 ;
     RECT  164.256 55.331 164.712 55.429 ;
     RECT  164.256 55.429 165.48 55.907 ;
     RECT  158.208 55.187 163.224 55.955 ;
     RECT  153.6 55.237 154.968 56.243 ;
     RECT  169.488 54.227 172.68 56.341 ;
     RECT  157.152 54.661 157.176 56.483 ;
     RECT  126.6 53.843 126.912 56.485 ;
     RECT  5.904 54.565 5.928 56.725 ;
     RECT  153.6 56.243 154.824 56.869 ;
     RECT  164.256 55.907 165.048 57.011 ;
     RECT  5.088 56.725 5.928 57.059 ;
     RECT  152.688 56.869 154.824 57.107 ;
     RECT  164.256 57.011 164.808 57.107 ;
     RECT  125.28 54.995 125.304 57.155 ;
     RECT  169.344 56.341 172.68 57.347 ;
     RECT  5.088 57.059 5.112 57.635 ;
     RECT  6.24 57.061 6.264 57.635 ;
     RECT  128.208 57.061 128.232 57.731 ;
     RECT  151.344 57.589 151.368 57.779 ;
     RECT  7.8 2.151 8.112 57.925 ;
     RECT  156.528 57.637 156.552 58.211 ;
     RECT  126.6 56.485 127.08 58.499 ;
     RECT  153.264 57.107 154.824 58.501 ;
     RECT  153.12 58.501 154.824 58.691 ;
     RECT  6.816 57.925 8.112 58.739 ;
     RECT  162.384 55.955 163.224 58.837 ;
     RECT  162.144 58.837 163.224 58.883 ;
     RECT  153.12 58.691 153.912 58.933 ;
     RECT  158.208 55.955 160.824 59.029 ;
     RECT  152.976 58.933 153.912 59.075 ;
     RECT  167.28 55.427 167.784 59.269 ;
     RECT  169.488 57.347 172.68 59.269 ;
     RECT  158.112 59.029 160.824 59.747 ;
     RECT  4.512 59.749 4.536 60.277 ;
     RECT  158.112 59.747 160.776 60.325 ;
     RECT  167.28 59.269 172.68 60.373 ;
     RECT  153.072 59.075 153.912 60.613 ;
     RECT  152.784 60.613 153.912 60.899 ;
     RECT  158.064 60.325 160.776 60.997 ;
     RECT  162.144 58.883 162.168 60.997 ;
     RECT  4.512 60.277 5.208 61.043 ;
     RECT  158.064 60.997 162.168 61.043 ;
     RECT  158.064 61.043 161.256 61.139 ;
     RECT  124.512 59.797 124.536 61.187 ;
     RECT  163.2 58.883 163.224 61.189 ;
     RECT  164.256 57.107 164.712 61.189 ;
     RECT  158.064 61.139 160.248 61.235 ;
     RECT  166.464 60.373 172.68 61.571 ;
     RECT  157.056 59.029 157.08 62.005 ;
     RECT  153.072 60.899 153.912 62.293 ;
     RECT  152.208 62.293 153.912 62.483 ;
     RECT  156.768 62.005 157.08 62.579 ;
     RECT  163.2 61.189 164.712 62.627 ;
     RECT  5.184 61.043 5.208 62.675 ;
     RECT  158.064 61.235 160.008 62.675 ;
     RECT  7.8 58.739 8.112 62.677 ;
     RECT  45.6 2.151 45.912 62.677 ;
     RECT  51 2.151 51.312 62.677 ;
     RECT  67.2 2.151 67.512 62.677 ;
     RECT  78 2.151 78.312 62.677 ;
     RECT  83.4 2.151 83.712 62.677 ;
     RECT  137.4 2.151 137.712 62.677 ;
     RECT  142.8 2.151 143.112 62.677 ;
     RECT  153.456 62.483 153.912 62.723 ;
     RECT  6.816 62.677 8.112 62.819 ;
     RECT  10.8 62.677 10.824 62.819 ;
     RECT  22.8 62.677 22.824 62.819 ;
     RECT  26.784 62.677 26.808 62.819 ;
     RECT  42.768 62.677 42.792 62.819 ;
     RECT  45.6 62.677 46.776 62.819 ;
     RECT  50.688 62.677 51.312 62.819 ;
     RECT  58.704 62.677 58.728 62.819 ;
     RECT  66.672 62.677 67.512 62.819 ;
     RECT  74.64 62.677 74.664 62.819 ;
     RECT  78 62.677 78.648 62.819 ;
     RECT  82.656 62.677 83.712 62.819 ;
     RECT  86.64 62.677 86.664 62.819 ;
     RECT  90.624 62.677 90.648 62.819 ;
     RECT  98.592 62.677 98.616 62.819 ;
     RECT  102.576 62.677 102.6 62.819 ;
     RECT  106.56 62.677 106.584 62.819 ;
     RECT  114.576 62.677 114.6 62.819 ;
     RECT  118.56 62.677 118.584 62.819 ;
     RECT  122.544 62.677 122.568 62.819 ;
     RECT  130.512 62.677 130.536 62.819 ;
     RECT  134.496 62.677 134.52 62.819 ;
     RECT  137.4 62.677 138.552 62.819 ;
     RECT  142.512 62.677 143.112 62.819 ;
     RECT  146.448 62.677 146.472 62.819 ;
     RECT  150.432 62.581 150.456 62.819 ;
     RECT  38.736 62.677 38.76 62.867 ;
     RECT  126.6 58.499 126.912 63.157 ;
     RECT  152.208 62.483 152.232 63.299 ;
     RECT  166.944 61.571 172.68 63.299 ;
     RECT  126.6 63.157 127.08 63.683 ;
     RECT  153.6 62.723 153.912 63.781 ;
     RECT  161.232 61.139 161.256 64.213 ;
     RECT  83.4 62.819 83.712 64.357 ;
     RECT  124.608 64.261 124.632 64.357 ;
     RECT  164.256 62.627 164.712 64.357 ;
     RECT  124.512 64.357 124.632 64.403 ;
     RECT  128.784 63.685 128.808 64.499 ;
     RECT  161.232 64.213 161.88 64.501 ;
     RECT  153.6 63.781 154.824 64.739 ;
     RECT  161.04 64.501 161.88 64.741 ;
     RECT  164.256 64.357 165.432 64.885 ;
     RECT  160.992 64.741 161.88 64.979 ;
     RECT  3.936 64.117 3.96 65.027 ;
     RECT  164.256 64.885 166.104 65.029 ;
     RECT  167.664 63.299 172.68 65.029 ;
     RECT  5.184 64.933 5.208 65.219 ;
     RECT  124.512 64.403 124.536 65.219 ;
     RECT  164.256 65.029 172.68 65.267 ;
     RECT  161.04 64.979 161.88 65.315 ;
     RECT  164.256 65.267 165.912 65.363 ;
     RECT  152.448 65.365 152.472 65.509 ;
     RECT  152.208 65.509 152.472 65.555 ;
     RECT  165.888 65.363 165.912 66.275 ;
     RECT  167.664 65.267 172.68 66.515 ;
     RECT  164.256 65.363 164.712 66.517 ;
     RECT  161.04 65.315 161.4 66.707 ;
     RECT  168.672 66.515 172.68 66.803 ;
     RECT  163.2 62.627 163.224 66.853 ;
     RECT  164.256 66.517 165.576 66.853 ;
     RECT  167.664 66.515 167.688 66.949 ;
     RECT  166.992 66.949 167.688 67.091 ;
     RECT  163.2 66.853 165.576 67.331 ;
     RECT  157.056 62.579 157.08 67.621 ;
     RECT  158.112 62.675 160.008 67.621 ;
     RECT  153.6 64.739 153.912 67.717 ;
     RECT  157.056 67.621 160.008 67.765 ;
     RECT  155.616 66.661 155.64 67.859 ;
     RECT  161.904 67.237 161.928 68.003 ;
     RECT  152.208 65.555 152.232 68.099 ;
     RECT  153.6 67.717 154.584 68.387 ;
     RECT  167.664 67.091 167.688 68.389 ;
     RECT  168.672 66.803 172.584 68.389 ;
     RECT  167.664 68.389 172.584 68.531 ;
     RECT  126.6 63.683 126.912 68.773 ;
     RECT  163.2 67.331 163.224 69.109 ;
     RECT  162.912 69.109 163.224 69.251 ;
     RECT  157.056 67.765 160.152 69.253 ;
     RECT  153.6 68.387 153.912 69.541 ;
     RECT  157.056 69.253 160.728 69.587 ;
     RECT  158.112 69.587 160.728 70.211 ;
     RECT  155.136 69.541 155.16 70.547 ;
     RECT  158.112 70.211 160.632 70.691 ;
     RECT  126.6 68.773 127.08 71.459 ;
     RECT  163.2 69.251 163.224 71.749 ;
     RECT  164.256 67.331 165.576 71.749 ;
     RECT  7.8 62.819 8.112 71.797 ;
     RECT  139.056 71.173 139.08 71.843 ;
     RECT  152.784 69.541 153.912 71.843 ;
     RECT  158.112 70.691 160.392 71.941 ;
     RECT  153.6 71.843 153.912 72.517 ;
     RECT  157.056 69.587 157.08 72.565 ;
     RECT  158.112 71.941 160.584 72.565 ;
     RECT  163.2 71.749 165.576 72.661 ;
     RECT  153.6 72.517 154.488 72.755 ;
     RECT  126.6 71.459 126.912 72.757 ;
     RECT  153.6 72.755 153.912 72.901 ;
     RECT  157.056 72.565 160.584 73.091 ;
     RECT  162.48 72.661 165.576 73.091 ;
     RECT  163.152 73.091 165.576 73.187 ;
     RECT  154.944 73.141 154.968 73.331 ;
     RECT  2.4 51.539 2.712 73.477 ;
     RECT  157.056 73.091 160.152 73.523 ;
     RECT  126.48 72.757 126.912 73.571 ;
     RECT  157.056 73.523 160.008 73.571 ;
     RECT  153.024 72.901 153.912 73.667 ;
     RECT  2.4 73.477 2.808 73.669 ;
     RECT  6.816 71.797 8.112 73.811 ;
     RECT  126.6 73.571 126.912 73.861 ;
     RECT  2.304 73.669 2.808 74.147 ;
     RECT  2.4 74.147 2.808 74.483 ;
     RECT  163.2 73.187 165.576 74.723 ;
     RECT  163.824 74.723 165.576 75.107 ;
     RECT  167.664 68.531 167.688 75.157 ;
     RECT  168.672 68.531 172.584 75.157 ;
     RECT  161.856 73.477 161.88 75.253 ;
     RECT  157.056 73.571 159.96 75.875 ;
     RECT  161.328 75.253 161.88 75.877 ;
     RECT  161.328 75.877 162.072 76.069 ;
     RECT  2.4 74.483 2.712 76.213 ;
     RECT  167.664 75.157 172.584 76.261 ;
     RECT  167.184 76.261 172.584 76.499 ;
     RECT  157.056 75.875 159.312 76.693 ;
     RECT  167.424 76.499 172.584 76.883 ;
     RECT  2.4 76.213 2.856 76.885 ;
     RECT  156.576 76.693 159.312 76.931 ;
     RECT  161.328 76.069 162.744 76.931 ;
     RECT  2.4 76.885 3.048 76.981 ;
     RECT  126.6 73.861 127.176 77.029 ;
     RECT  167.664 76.883 167.688 77.075 ;
     RECT  162.432 76.931 162.744 77.267 ;
     RECT  126.48 77.029 127.176 77.555 ;
     RECT  124.176 75.925 124.2 77.557 ;
     RECT  157.056 76.931 159.312 77.701 ;
     RECT  168.672 76.883 172.584 77.941 ;
     RECT  161.328 76.931 161.352 77.987 ;
     RECT  162.432 77.267 162.456 77.989 ;
     RECT  157.056 77.701 159.48 78.035 ;
     RECT  161.376 77.989 162.456 78.131 ;
     RECT  161.376 78.131 161.88 78.179 ;
     RECT  2.4 76.981 3.672 78.325 ;
     RECT  153.6 73.667 153.912 78.517 ;
     RECT  161.856 78.179 161.88 78.851 ;
     RECT  168.096 77.941 172.584 79.091 ;
     RECT  124.176 77.557 124.248 79.283 ;
     RECT  2.4 78.325 4.536 79.429 ;
     RECT  157.056 78.035 159.312 80.101 ;
     RECT  2.304 79.429 4.536 80.339 ;
     RECT  2.4 80.339 4.536 80.435 ;
     RECT  167.136 80.005 167.16 80.435 ;
     RECT  168.288 79.091 172.584 80.867 ;
     RECT  164.4 75.107 165.576 80.869 ;
     RECT  166.656 80.437 166.68 80.869 ;
     RECT  2.4 80.435 3.672 80.963 ;
     RECT  124.224 79.283 124.248 80.963 ;
     RECT  164.4 80.869 166.68 81.059 ;
     RECT  2.4 80.963 3.624 81.539 ;
     RECT  164.4 81.059 166.488 81.539 ;
     RECT  157.056 80.101 160.152 82.979 ;
     RECT  126.6 77.555 127.176 84.995 ;
     RECT  153.6 78.517 154.824 85.475 ;
     RECT  83.232 64.357 83.712 87.971 ;
     RECT  164.4 81.539 165.576 88.309 ;
     RECT  168.672 80.867 172.584 88.357 ;
     RECT  168.672 88.357 172.68 99.299 ;
     RECT  158.112 82.979 160.152 100.547 ;
     RECT  164.112 88.309 165.576 100.645 ;
     RECT  168.96 99.299 172.68 101.075 ;
     RECT  158.112 100.547 159.312 102.803 ;
     RECT  169.056 101.075 172.68 103.331 ;
     RECT  157.056 82.979 157.08 103.859 ;
     RECT  169.056 103.331 172.584 103.907 ;
     RECT  164.112 100.645 166.536 104.051 ;
     RECT  162.816 86.581 162.84 104.435 ;
     RECT  168.48 104.149 168.504 104.677 ;
     RECT  164.4 104.051 166.536 104.723 ;
     RECT  169.8 103.907 172.584 105.731 ;
     RECT  172.56 105.731 172.584 106.211 ;
     RECT  169.8 105.731 171.576 107.363 ;
     RECT  169.8 107.363 170.856 111.011 ;
     RECT  0.192 87.829 0.216 112.355 ;
     RECT  167.808 104.677 168.504 119.555 ;
     RECT  166.512 104.723 166.536 121.091 ;
     RECT  167.808 119.555 167.832 122.675 ;
     RECT  2.4 81.539 2.712 127.449 ;
     RECT  7.8 73.811 8.112 127.449 ;
     RECT  13.2 2.151 13.512 127.449 ;
     RECT  18.6 2.151 18.912 127.449 ;
     RECT  24 2.151 24.312 127.449 ;
     RECT  29.4 2.151 29.712 127.449 ;
     RECT  34.8 2.151 35.112 127.449 ;
     RECT  40.2 2.151 40.512 127.449 ;
     RECT  45.6 62.819 45.912 127.449 ;
     RECT  51 62.819 51.312 127.449 ;
     RECT  56.4 2.151 56.712 127.449 ;
     RECT  61.8 2.151 62.112 127.449 ;
     RECT  67.2 62.819 67.512 127.449 ;
     RECT  72.6 2.151 72.912 127.449 ;
     RECT  78 62.819 78.312 127.449 ;
     RECT  83.4 87.971 83.712 127.449 ;
     RECT  88.8 2.151 89.112 127.449 ;
     RECT  94.2 2.151 94.512 127.449 ;
     RECT  99.6 2.151 99.912 127.449 ;
     RECT  105 2.151 105.312 127.449 ;
     RECT  110.4 2.151 110.712 127.449 ;
     RECT  115.8 2.151 116.112 127.449 ;
     RECT  121.2 2.151 121.512 127.449 ;
     RECT  126.6 84.995 126.912 127.449 ;
     RECT  132 2.151 132.312 127.449 ;
     RECT  137.4 62.819 137.712 127.449 ;
     RECT  142.8 62.819 143.112 127.449 ;
     RECT  148.2 2.151 148.512 127.449 ;
     RECT  153.6 85.475 153.912 127.449 ;
     RECT  159 102.803 159.312 127.449 ;
     RECT  164.4 104.723 164.712 127.449 ;
     RECT  169.8 111.011 170.112 127.449 ;
     RECT  2.4 127.449 2.52 127.463 ;
     RECT  7.8 127.449 7.92 127.463 ;
     RECT  13.2 127.449 13.32 127.463 ;
     RECT  18.6 127.449 18.72 127.463 ;
     RECT  24 127.449 24.12 127.463 ;
     RECT  29.4 127.449 29.52 127.463 ;
     RECT  34.8 127.449 34.92 127.463 ;
     RECT  40.2 127.449 40.32 127.463 ;
     RECT  45.6 127.449 45.72 127.463 ;
     RECT  51 127.449 51.12 127.463 ;
     RECT  56.4 127.449 56.52 127.463 ;
     RECT  61.8 127.449 61.92 127.463 ;
     RECT  67.2 127.449 67.32 127.463 ;
     RECT  72.6 127.449 72.72 127.463 ;
     RECT  78 127.449 78.12 127.463 ;
     RECT  83.4 127.449 83.52 127.463 ;
     RECT  88.8 127.449 88.92 127.463 ;
     RECT  94.2 127.449 94.32 127.463 ;
     RECT  99.6 127.449 99.72 127.463 ;
     RECT  105 127.449 105.12 127.463 ;
     RECT  110.4 127.449 110.52 127.463 ;
     RECT  115.8 127.449 115.92 127.463 ;
     RECT  121.2 127.449 121.32 127.463 ;
     RECT  126.6 127.449 126.72 127.463 ;
     RECT  132 127.449 132.12 127.463 ;
     RECT  137.4 127.449 137.52 127.463 ;
     RECT  142.8 127.449 142.92 127.463 ;
     RECT  148.2 127.449 148.32 127.463 ;
     RECT  153.6 127.449 153.72 127.463 ;
     RECT  159 127.449 159.12 127.463 ;
     RECT  164.4 127.449 164.52 127.463 ;
     RECT  169.8 127.449 169.92 127.463 ;
  END
END ot_hgi_sm_pub_vmcore
END LIBRARY
